# Scaled down LEF created by ScaleLEFMacro.pl
# Original LEF: 16nm/HD_1024X32M8B2.lef
# Don't forget to change metal layer LEF separately!

# Copyright (c) 1993 - 2021 ARM Limited. All Rights Reserved.
# Use of this Software is subject to the terms and conditions of the
# applicable license agreement with ARM Limited.

# PhyVGen V 8.22.0
# ARM Version r3p2
# Creation Date: Thu Sep  9 16:08:25 2021


# Memory Configuration:
# ~~~~~~~~~~~~~~~~~~~~~
#  -activity_factor 50 -atf off -back_biasing off -bits 32 -bmux on
# -bus_notation on -check_instname on -compiler_type sp -diodes on -drive 6
# -ema on -flexible_banking 2 -frequency 1000 -instname HD_1024X32M8B2
# -left_bus_delim "[" -lren_bankmask off -metal_stack 2Xa1Xd -mux 8 -mvt LP
# -name_case upper -pipeline off -power_gating off -power_type otc -prefix ""
# -pwr_gnd_rename vddpe:VDDPE,vddce:VDDCE,vsse:VSSE -rcols 2 -redundancy off
# -retention on -right_bus_delim "]" -rows_p_bl 256 -rrows 0 -scan on -ser none
# -site_def off -top_layer m5-m10 -vmin_assist on -words 1024 -write_mask on
# -write_thru off -corners
# ffgnp_0p88v_0p88v_0c,ffgnp_0p88v_0p88v_125c,ffgnp_0p88v_0p88v_m40c,ssgnp_0p72v_0p72v_0c,ssgnp_0p72v_0p72v_125c,ssgnp_0p72v_0p72v_m40c,tt_0p72v_0p72v_0c,tt_0p80v_0p80v_25c,tt_0p80v_0p80v_85c
# 

VERSION 5.7 ;
BUSBITCHARS "[]" ;
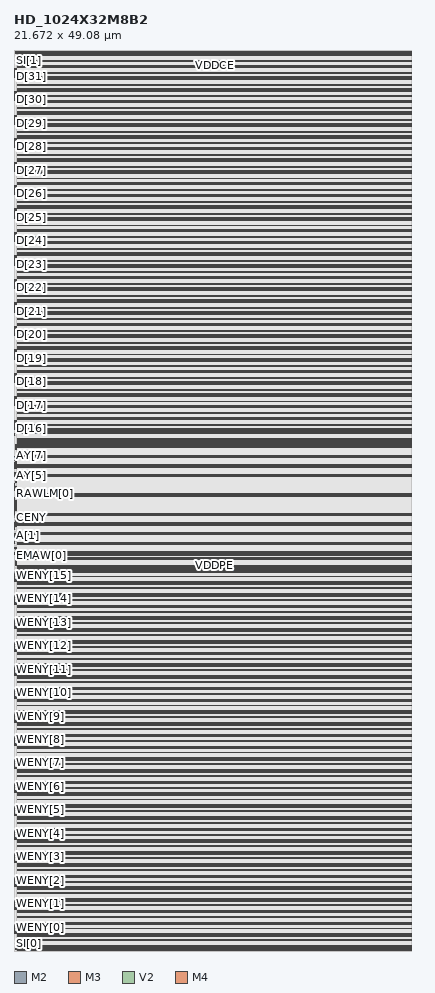
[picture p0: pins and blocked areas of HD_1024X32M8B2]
MACRO HD_1024X32M8B2
	FOREIGN HD_1024X32M8B2 0 0 ;
	SYMMETRY X Y ;
	SIZE 21.672 BY 49.08 ;
	CLASS BLOCK ;
	PIN AY[0]
		USE SIGNAL ;
		DIRECTION OUTPUT ;
		SHAPE ABUTMENT ;
		PORT
			 LAYER M2 ;
			RECT 0.0714 24.0314 0.1097 24.069 ;
			 LAYER M3 ;
			RECT 0.0714 24.0314 0.1097 24.1318 ;
			 LAYER V2 ;
			RECT 0.0831 24.0435 0.098 24.0561 ;
		END

		ANTENNADIFFAREA 0.00194719 ;
		ANTENNAPARTIALMETALAREA 0.00195671 ;
	END AY[0]

	PIN AY[1]
		USE SIGNAL ;
		DIRECTION OUTPUT ;
		SHAPE ABUTMENT ;
		PORT
			 LAYER M2 ;
			RECT 0.0714 24.3325 0.1097 24.3702 ;
			 LAYER M3 ;
			RECT 0.0714 24.3325 0.1097 24.4329 ;
			 LAYER V2 ;
			RECT 0.0831 24.3447 0.098 24.3573 ;
		END

		ANTENNADIFFAREA 0.00194719 ;
		ANTENNAPARTIALMETALAREA 0.00195671 ;
	END AY[1]

	PIN AY[2]
		USE SIGNAL ;
		DIRECTION OUTPUT ;
		SHAPE ABUTMENT ;
		PORT
			 LAYER M2 ;
			RECT 0.0714 24.4831 0.1097 24.5208 ;
			 LAYER M3 ;
			RECT 0.0714 24.4831 0.1097 24.5835 ;
			 LAYER V2 ;
			RECT 0.0831 24.4953 0.098 24.5078 ;
		END

		ANTENNADIFFAREA 0.00194719 ;
		ANTENNAPARTIALMETALAREA 0.00195671 ;
	END AY[2]

	PIN AY[3]
		USE SIGNAL ;
		DIRECTION OUTPUT ;
		SHAPE ABUTMENT ;
		PORT
			 LAYER M2 ;
			RECT 0.0098 25.1482 0.0481 25.1859 ;
			 LAYER M3 ;
			RECT 0.0098 25.0855 0.0481 25.1859 ;
			 LAYER V2 ;
			RECT 0.0215 25.1604 0.0364 25.1729 ;
		END

		ANTENNADIFFAREA 0.00194719 ;
		ANTENNAPARTIALMETALAREA 0.00195671 ;
	END AY[3]

	PIN AY[4]
		USE SIGNAL ;
		DIRECTION OUTPUT ;
		SHAPE ABUTMENT ;
		PORT
			 LAYER M2 ;
			RECT 0.0098 24.2447 0.0481 24.2824 ;
			 LAYER M3 ;
			RECT 0.0098 24.182 0.0481 24.2824 ;
			 LAYER V2 ;
			RECT 0.0215 24.2569 0.0364 24.2694 ;
		END

		ANTENNADIFFAREA 0.00194719 ;
		ANTENNAPARTIALMETALAREA 0.00195671 ;
	END AY[4]

	PIN AY[5]
		USE SIGNAL ;
		DIRECTION OUTPUT ;
		SHAPE ABUTMENT ;
		PORT
			 LAYER M2 ;
			RECT 0.0098 25.9012 0.0481 25.9388 ;
		END

		ANTENNADIFFAREA 0.00194719 ;
		ANTENNAPARTIALMETALAREA 0.00195671 ;
	END AY[5]

	PIN AY[6]
		USE SIGNAL ;
		DIRECTION OUTPUT ;
		SHAPE ABUTMENT ;
		PORT
			 LAYER M2 ;
			RECT 0.0714 25.6878 0.1097 25.7255 ;
			 LAYER M3 ;
			RECT 0.0714 25.6878 0.1097 25.7882 ;
			 LAYER V2 ;
			RECT 0.0831 25.7 0.098 25.7125 ;
		END

		ANTENNADIFFAREA 0.00194719 ;
		ANTENNAPARTIALMETALAREA 0.00195671 ;
	END AY[6]

	PIN AY[7]
		USE SIGNAL ;
		DIRECTION OUTPUT ;
		SHAPE ABUTMENT ;
		PORT
			 LAYER M2 ;
			RECT 0.0098 26.5914 0.0481 26.629 ;
		END

		ANTENNADIFFAREA 0.00194719 ;
		ANTENNAPARTIALMETALAREA 0.00195671 ;
	END AY[7]

	PIN AY[8]
		USE SIGNAL ;
		DIRECTION OUTPUT ;
		SHAPE ABUTMENT ;
		PORT
			 LAYER M2 ;
			RECT 0.0714 26.8925 0.1097 26.9302 ;
			 LAYER M3 ;
			RECT 0.0714 26.8925 0.1097 26.9929 ;
			 LAYER V2 ;
			RECT 0.0831 26.9047 0.098 26.9173 ;
		END

		ANTENNADIFFAREA 0.00194719 ;
		ANTENNAPARTIALMETALAREA 0.00195671 ;
	END AY[8]

	PIN AY[9]
		USE SIGNAL ;
		DIRECTION OUTPUT ;
		SHAPE ABUTMENT ;
		PORT
			 LAYER M3 ;
			RECT 0.0714 26.5914 0.1097 26.6918 ;
		END

		ANTENNADIFFAREA 0.00194719 ;
		ANTENNAPARTIALMETALAREA 0.00195671 ;
	END AY[9]

	PIN A[0]
		USE SIGNAL ;
		DIRECTION INPUT ;
		SHAPE ABUTMENT ;
		PORT
			 LAYER M2 ;
			RECT 0.0098 23.7929 0.0481 23.8306 ;
			 LAYER M3 ;
			RECT 0.0098 23.7302 0.0481 23.8306 ;
			 LAYER V2 ;
			RECT 0.0215 23.8051 0.0364 23.8176 ;
		END

		ANTENNAGATEAREA 0.00027817 ;
		ANTENNADIFFAREA 0.00194719 ;
		ANTENNAPARTIALMETALAREA 0.00195671 ;
	END A[0]

	PIN A[1]
		USE SIGNAL ;
		DIRECTION INPUT ;
		SHAPE ABUTMENT ;
		PORT
			 LAYER M2 ;
			RECT 0.0098 23.04 0.0481 23.0776 ;
			 LAYER M3 ;
			RECT 0.0098 22.9773 0.0481 23.0776 ;
			 LAYER V2 ;
			RECT 0.0215 23.0522 0.0364 23.0647 ;
		END

		ANTENNAGATEAREA 0.00027817 ;
		ANTENNADIFFAREA 0.00194719 ;
		ANTENNAPARTIALMETALAREA 0.00195671 ;
	END A[1]

	PIN A[2]
		USE SIGNAL ;
		DIRECTION INPUT ;
		SHAPE ABUTMENT ;
		PORT
			 LAYER M2 ;
			RECT 0.0714 26.4408 0.1097 26.4784 ;
			 LAYER M3 ;
			RECT 0.0714 26.4408 0.1097 26.5412 ;
			 LAYER V2 ;
			RECT 0.0831 26.4529 0.098 26.4655 ;
		END

		ANTENNAGATEAREA 0.00027817 ;
		ANTENNADIFFAREA 0.00194719 ;
		ANTENNAPARTIALMETALAREA 0.00195671 ;
	END A[2]

	PIN A[3]
		USE SIGNAL ;
		DIRECTION INPUT ;
		SHAPE ABUTMENT ;
		PORT
			 LAYER M2 ;
			RECT 0.0098 25.2988 0.0481 25.3365 ;
			 LAYER M3 ;
			RECT 0.0098 25.2361 0.0481 25.3365 ;
			 LAYER V2 ;
			RECT 0.0215 25.311 0.0364 25.3235 ;
		END

		ANTENNAGATEAREA 0.00027817 ;
		ANTENNADIFFAREA 0.00194719 ;
		ANTENNAPARTIALMETALAREA 0.00195671 ;
	END A[3]

	PIN A[4]
		USE SIGNAL ;
		DIRECTION INPUT ;
		SHAPE ABUTMENT ;
		PORT
			 LAYER M2 ;
			RECT 0.0098 24.6965 0.0481 24.7341 ;
			 LAYER M3 ;
			RECT 0.0098 24.6337 0.0481 24.7341 ;
			 LAYER V2 ;
			RECT 0.0215 24.7086 0.0364 24.7212 ;
		END

		ANTENNAGATEAREA 0.00027817 ;
		ANTENNADIFFAREA 0.00194719 ;
		ANTENNAPARTIALMETALAREA 0.00195671 ;
	END A[4]

	PIN A[5]
		USE SIGNAL ;
		DIRECTION INPUT ;
		SHAPE ABUTMENT ;
		PORT
			 LAYER M2 ;
			RECT 0.0098 25.4494 0.0481 25.4871 ;
			 LAYER M3 ;
			RECT 0.0098 25.3867 0.0481 25.4871 ;
			 LAYER V2 ;
			RECT 0.0215 25.4616 0.0364 25.4741 ;
		END

		ANTENNAGATEAREA 0.00027817 ;
		ANTENNADIFFAREA 0.00194719 ;
		ANTENNAPARTIALMETALAREA 0.00195671 ;
	END A[5]

	PIN A[6]
		USE SIGNAL ;
		DIRECTION INPUT ;
		SHAPE ABUTMENT ;
		PORT
			 LAYER M2 ;
			RECT 0.0098 26.0518 0.0481 26.0894 ;
		END

		ANTENNAGATEAREA 0.00027817 ;
		ANTENNADIFFAREA 0.00194719 ;
		ANTENNAPARTIALMETALAREA 0.00195671 ;
	END A[6]

	PIN A[7]
		USE SIGNAL ;
		DIRECTION INPUT ;
		SHAPE ABUTMENT ;
		PORT
			 LAYER M2 ;
			RECT 0.0098 26.3529 0.0481 26.3906 ;
			 LAYER M3 ;
			RECT 0.0098 26.2902 0.0481 26.3906 ;
			 LAYER V2 ;
			RECT 0.0215 26.3651 0.0364 26.3776 ;
		END

		ANTENNAGATEAREA 0.00027817 ;
		ANTENNADIFFAREA 0.00194719 ;
		ANTENNAPARTIALMETALAREA 0.00195671 ;
	END A[7]

	PIN A[8]
		USE SIGNAL ;
		DIRECTION INPUT ;
		SHAPE ABUTMENT ;
		PORT
			 LAYER M2 ;
			RECT 0.0098 26.5035 0.0481 26.5412 ;
			 LAYER M3 ;
			RECT 0.0098 26.4408 0.0481 26.5412 ;
			 LAYER V2 ;
			RECT 0.0215 26.5157 0.0364 26.5282 ;
		END

		ANTENNAGATEAREA 0.00027817 ;
		ANTENNADIFFAREA 0.00194719 ;
		ANTENNAPARTIALMETALAREA 0.00195671 ;
	END A[8]

	PIN A[9]
		USE SIGNAL ;
		DIRECTION INPUT ;
		SHAPE ABUTMENT ;
		PORT
			 LAYER M2 ;
			RECT 0.0098 26.9553 0.0481 26.9929 ;
			 LAYER M3 ;
			RECT 0.0098 26.8925 0.0481 26.9929 ;
			 LAYER V2 ;
			RECT 0.0215 26.9675 0.0364 26.98 ;
		END

		ANTENNAGATEAREA 0.00027817 ;
		ANTENNADIFFAREA 0.00194719 ;
		ANTENNAPARTIALMETALAREA 0.00195671 ;
	END A[9]

	PIN CEN
		USE SIGNAL ;
		DIRECTION INPUT ;
		SHAPE ABUTMENT ;
		PORT
			 LAYER M2 ;
			RECT 0.0714 27.4949 0.1097 27.5325 ;
			 LAYER M3 ;
			RECT 0.0714 27.4949 0.1097 27.5953 ;
			 LAYER V2 ;
			RECT 0.0831 27.5071 0.098 27.5196 ;
		END

		ANTENNAGATEAREA 0.00027817 ;
		ANTENNADIFFAREA 0.00194719 ;
		ANTENNAPARTIALMETALAREA 0.00195671 ;
	END CEN

	PIN CENY
		USE SIGNAL ;
		DIRECTION OUTPUT ;
		SHAPE ABUTMENT ;
		PORT
			 LAYER M2 ;
			RECT 0.0098 23.6424 0.0481 23.68 ;
		END

		ANTENNADIFFAREA 0.00194719 ;
		ANTENNAPARTIALMETALAREA 0.00195671 ;
	END CENY

	PIN CLK
		USE SIGNAL ;
		DIRECTION INPUT ;
		SHAPE ABUTMENT ;
		PORT
			 LAYER M2 ;
			RECT 0.0098 24.0941 0.0481 24.1318 ;
			 LAYER M3 ;
			RECT 0.0098 24.0314 0.0481 24.1318 ;
			 LAYER V2 ;
			RECT 0.0215 24.1063 0.0364 24.1188 ;
		END

		ANTENNAGATEAREA 0.00027817 ;
		ANTENNADIFFAREA 0.00194719 ;
		ANTENNAPARTIALMETALAREA 0.00195671 ;
	END CLK

	PIN DFTRAMBYP
		USE SIGNAL ;
		DIRECTION INPUT ;
		SHAPE ABUTMENT ;
		PORT
			 LAYER M2 ;
			RECT 0.0714 22.5255 0.1097 22.5631 ;
			 LAYER M3 ;
			RECT 0.0714 22.5255 0.1097 22.6259 ;
			 LAYER V2 ;
			RECT 0.0831 22.5376 0.098 22.5502 ;
		END

		ANTENNAGATEAREA 0.00027817 ;
		ANTENNADIFFAREA 0.00194719 ;
		ANTENNAPARTIALMETALAREA 0.00195671 ;
	END DFTRAMBYP

	PIN D[0]
		USE SIGNAL ;
		DIRECTION INPUT ;
		SHAPE ABUTMENT ;
		PORT
			 LAYER M2 ;
			RECT 0.0098 1.3678 0.0481 1.4055 ;
			 LAYER M3 ;
			RECT 0.0098 1.3678 0.0481 1.4682 ;
			 LAYER V2 ;
			RECT 0.0215 1.3808 0.0364 1.3933 ;
		END

		ANTENNAGATEAREA 0.00027817 ;
		ANTENNADIFFAREA 0.00194719 ;
		ANTENNAPARTIALMETALAREA 0.00195671 ;
	END D[0]

	PIN D[10]
		USE SIGNAL ;
		DIRECTION INPUT ;
		SHAPE ABUTMENT ;
		PORT
			 LAYER M2 ;
			RECT 0.0098 14.1678 0.0481 14.2055 ;
			 LAYER M3 ;
			RECT 0.0098 14.1678 0.0481 14.2682 ;
			 LAYER V2 ;
			RECT 0.0215 14.1808 0.0364 14.1933 ;
		END

		ANTENNAGATEAREA 0.00027817 ;
		ANTENNADIFFAREA 0.00194719 ;
		ANTENNAPARTIALMETALAREA 0.00195671 ;
	END D[10]

	PIN D[11]
		USE SIGNAL ;
		DIRECTION INPUT ;
		SHAPE ABUTMENT ;
		PORT
			 LAYER M2 ;
			RECT 0.0098 15.4478 0.0481 15.4855 ;
			 LAYER M3 ;
			RECT 0.0098 15.4478 0.0481 15.5482 ;
			 LAYER V2 ;
			RECT 0.0215 15.4608 0.0364 15.4733 ;
		END

		ANTENNAGATEAREA 0.00027817 ;
		ANTENNADIFFAREA 0.00194719 ;
		ANTENNAPARTIALMETALAREA 0.00195671 ;
	END D[11]

	PIN D[12]
		USE SIGNAL ;
		DIRECTION INPUT ;
		SHAPE ABUTMENT ;
		PORT
			 LAYER M2 ;
			RECT 0.0098 16.7278 0.0481 16.7655 ;
			 LAYER M3 ;
			RECT 0.0098 16.7278 0.0481 16.8282 ;
			 LAYER V2 ;
			RECT 0.0215 16.7408 0.0364 16.7533 ;
		END

		ANTENNAGATEAREA 0.00027817 ;
		ANTENNADIFFAREA 0.00194719 ;
		ANTENNAPARTIALMETALAREA 0.00195671 ;
	END D[12]

	PIN D[13]
		USE SIGNAL ;
		DIRECTION INPUT ;
		SHAPE ABUTMENT ;
		PORT
			 LAYER M2 ;
			RECT 0.0098 18.0078 0.0481 18.0455 ;
			 LAYER M3 ;
			RECT 0.0098 18.0078 0.0481 18.1082 ;
			 LAYER V2 ;
			RECT 0.0215 18.0208 0.0364 18.0333 ;
		END

		ANTENNAGATEAREA 0.00027817 ;
		ANTENNADIFFAREA 0.00194719 ;
		ANTENNAPARTIALMETALAREA 0.00195671 ;
	END D[13]

	PIN D[14]
		USE SIGNAL ;
		DIRECTION INPUT ;
		SHAPE ABUTMENT ;
		PORT
			 LAYER M2 ;
			RECT 0.0098 19.2878 0.0481 19.3255 ;
			 LAYER M3 ;
			RECT 0.0098 19.2878 0.0481 19.3882 ;
			 LAYER V2 ;
			RECT 0.0215 19.3008 0.0364 19.3133 ;
		END

		ANTENNAGATEAREA 0.00027817 ;
		ANTENNADIFFAREA 0.00194719 ;
		ANTENNAPARTIALMETALAREA 0.00195671 ;
	END D[14]

	PIN D[15]
		USE SIGNAL ;
		DIRECTION INPUT ;
		SHAPE ABUTMENT ;
		PORT
			 LAYER M2 ;
			RECT 0.0098 20.5678 0.0481 20.6055 ;
			 LAYER M3 ;
			RECT 0.0098 20.5678 0.0481 20.6682 ;
			 LAYER V2 ;
			RECT 0.0215 20.5808 0.0364 20.5933 ;
		END

		ANTENNAGATEAREA 0.00027817 ;
		ANTENNADIFFAREA 0.00194719 ;
		ANTENNAPARTIALMETALAREA 0.00195671 ;
	END D[15]

	PIN D[16]
		USE SIGNAL ;
		DIRECTION INPUT ;
		SHAPE ABUTMENT ;
		PORT
			 LAYER M2 ;
			RECT 0.0098 28.5051 0.0481 28.5427 ;
			 LAYER M3 ;
			RECT 0.0098 28.4424 0.0481 28.5427 ;
			 LAYER V2 ;
			RECT 0.0215 28.5173 0.0364 28.5298 ;
		END

		ANTENNAGATEAREA 0.00027817 ;
		ANTENNADIFFAREA 0.00194719 ;
		ANTENNAPARTIALMETALAREA 0.00195671 ;
	END D[16]

	PIN D[17]
		USE SIGNAL ;
		DIRECTION INPUT ;
		SHAPE ABUTMENT ;
		PORT
			 LAYER M2 ;
			RECT 0.0098 29.7851 0.0481 29.8227 ;
			 LAYER M3 ;
			RECT 0.0098 29.7224 0.0481 29.8227 ;
			 LAYER V2 ;
			RECT 0.0215 29.7973 0.0364 29.8098 ;
		END

		ANTENNAGATEAREA 0.00027817 ;
		ANTENNADIFFAREA 0.00194719 ;
		ANTENNAPARTIALMETALAREA 0.00195671 ;
	END D[17]

	PIN D[18]
		USE SIGNAL ;
		DIRECTION INPUT ;
		SHAPE ABUTMENT ;
		PORT
			 LAYER M2 ;
			RECT 0.0098 31.0651 0.0481 31.1027 ;
			 LAYER M3 ;
			RECT 0.0098 31.0024 0.0481 31.1027 ;
			 LAYER V2 ;
			RECT 0.0215 31.0773 0.0364 31.0898 ;
		END

		ANTENNAGATEAREA 0.00027817 ;
		ANTENNADIFFAREA 0.00194719 ;
		ANTENNAPARTIALMETALAREA 0.00195671 ;
	END D[18]

	PIN D[19]
		USE SIGNAL ;
		DIRECTION INPUT ;
		SHAPE ABUTMENT ;
		PORT
			 LAYER M2 ;
			RECT 0.0098 32.3451 0.0481 32.3827 ;
			 LAYER M3 ;
			RECT 0.0098 32.2824 0.0481 32.3827 ;
			 LAYER V2 ;
			RECT 0.0215 32.3573 0.0364 32.3698 ;
		END

		ANTENNAGATEAREA 0.00027817 ;
		ANTENNADIFFAREA 0.00194719 ;
		ANTENNAPARTIALMETALAREA 0.00195671 ;
	END D[19]

	PIN D[1]
		USE SIGNAL ;
		DIRECTION INPUT ;
		SHAPE ABUTMENT ;
		PORT
			 LAYER M2 ;
			RECT 0.0098 2.6478 0.0481 2.6855 ;
			 LAYER M3 ;
			RECT 0.0098 2.6478 0.0481 2.7482 ;
			 LAYER V2 ;
			RECT 0.0215 2.6608 0.0364 2.6733 ;
		END

		ANTENNAGATEAREA 0.00027817 ;
		ANTENNADIFFAREA 0.00194719 ;
		ANTENNAPARTIALMETALAREA 0.00195671 ;
	END D[1]

	PIN D[20]
		USE SIGNAL ;
		DIRECTION INPUT ;
		SHAPE ABUTMENT ;
		PORT
			 LAYER M2 ;
			RECT 0.0098 33.6251 0.0481 33.6627 ;
			 LAYER M3 ;
			RECT 0.0098 33.5624 0.0481 33.6627 ;
			 LAYER V2 ;
			RECT 0.0215 33.6373 0.0364 33.6498 ;
		END

		ANTENNAGATEAREA 0.00027817 ;
		ANTENNADIFFAREA 0.00194719 ;
		ANTENNAPARTIALMETALAREA 0.00195671 ;
	END D[20]

	PIN D[21]
		USE SIGNAL ;
		DIRECTION INPUT ;
		SHAPE ABUTMENT ;
		PORT
			 LAYER M2 ;
			RECT 0.0098 34.9051 0.0481 34.9427 ;
			 LAYER M3 ;
			RECT 0.0098 34.8424 0.0481 34.9427 ;
			 LAYER V2 ;
			RECT 0.0215 34.9173 0.0364 34.9298 ;
		END

		ANTENNAGATEAREA 0.00027817 ;
		ANTENNADIFFAREA 0.00194719 ;
		ANTENNAPARTIALMETALAREA 0.00195671 ;
	END D[21]

	PIN D[22]
		USE SIGNAL ;
		DIRECTION INPUT ;
		SHAPE ABUTMENT ;
		PORT
			 LAYER M2 ;
			RECT 0.0098 36.1851 0.0481 36.2227 ;
			 LAYER M3 ;
			RECT 0.0098 36.1224 0.0481 36.2227 ;
			 LAYER V2 ;
			RECT 0.0215 36.1973 0.0364 36.2098 ;
		END

		ANTENNAGATEAREA 0.00027817 ;
		ANTENNADIFFAREA 0.00194719 ;
		ANTENNAPARTIALMETALAREA 0.00195671 ;
	END D[22]

	PIN D[23]
		USE SIGNAL ;
		DIRECTION INPUT ;
		SHAPE ABUTMENT ;
		PORT
			 LAYER M2 ;
			RECT 0.0098 37.4651 0.0481 37.5027 ;
			 LAYER M3 ;
			RECT 0.0098 37.4024 0.0481 37.5027 ;
			 LAYER V2 ;
			RECT 0.0215 37.4773 0.0364 37.4898 ;
		END

		ANTENNAGATEAREA 0.00027817 ;
		ANTENNADIFFAREA 0.00194719 ;
		ANTENNAPARTIALMETALAREA 0.00195671 ;
	END D[23]

	PIN D[24]
		USE SIGNAL ;
		DIRECTION INPUT ;
		SHAPE ABUTMENT ;
		PORT
			 LAYER M2 ;
			RECT 0.0098 38.7451 0.0481 38.7827 ;
			 LAYER M3 ;
			RECT 0.0098 38.6824 0.0481 38.7827 ;
			 LAYER V2 ;
			RECT 0.0215 38.7573 0.0364 38.7698 ;
		END

		ANTENNAGATEAREA 0.00027817 ;
		ANTENNADIFFAREA 0.00194719 ;
		ANTENNAPARTIALMETALAREA 0.00195671 ;
	END D[24]

	PIN D[25]
		USE SIGNAL ;
		DIRECTION INPUT ;
		SHAPE ABUTMENT ;
		PORT
			 LAYER M2 ;
			RECT 0.0098 40.0251 0.0481 40.0627 ;
			 LAYER M3 ;
			RECT 0.0098 39.9624 0.0481 40.0627 ;
			 LAYER V2 ;
			RECT 0.0215 40.0373 0.0364 40.0498 ;
		END

		ANTENNAGATEAREA 0.00027817 ;
		ANTENNADIFFAREA 0.00194719 ;
		ANTENNAPARTIALMETALAREA 0.00195671 ;
	END D[25]

	PIN D[26]
		USE SIGNAL ;
		DIRECTION INPUT ;
		SHAPE ABUTMENT ;
		PORT
			 LAYER M2 ;
			RECT 0.0098 41.3051 0.0481 41.3427 ;
			 LAYER M3 ;
			RECT 0.0098 41.2424 0.0481 41.3427 ;
			 LAYER V2 ;
			RECT 0.0215 41.3173 0.0364 41.3298 ;
		END

		ANTENNAGATEAREA 0.00027817 ;
		ANTENNADIFFAREA 0.00194719 ;
		ANTENNAPARTIALMETALAREA 0.00195671 ;
	END D[26]

	PIN D[27]
		USE SIGNAL ;
		DIRECTION INPUT ;
		SHAPE ABUTMENT ;
		PORT
			 LAYER M2 ;
			RECT 0.0098 42.5851 0.0481 42.6227 ;
			 LAYER M3 ;
			RECT 0.0098 42.5224 0.0481 42.6227 ;
			 LAYER V2 ;
			RECT 0.0215 42.5973 0.0364 42.6098 ;
		END

		ANTENNAGATEAREA 0.00027817 ;
		ANTENNADIFFAREA 0.00194719 ;
		ANTENNAPARTIALMETALAREA 0.00195671 ;
	END D[27]

	PIN D[28]
		USE SIGNAL ;
		DIRECTION INPUT ;
		SHAPE ABUTMENT ;
		PORT
			 LAYER M2 ;
			RECT 0.0098 43.8651 0.0481 43.9027 ;
			 LAYER M3 ;
			RECT 0.0098 43.8024 0.0481 43.9027 ;
			 LAYER V2 ;
			RECT 0.0215 43.8773 0.0364 43.8898 ;
		END

		ANTENNAGATEAREA 0.00027817 ;
		ANTENNADIFFAREA 0.00194719 ;
		ANTENNAPARTIALMETALAREA 0.00195671 ;
	END D[28]

	PIN D[29]
		USE SIGNAL ;
		DIRECTION INPUT ;
		SHAPE ABUTMENT ;
		PORT
			 LAYER M2 ;
			RECT 0.0098 45.1451 0.0481 45.1827 ;
			 LAYER M3 ;
			RECT 0.0098 45.0824 0.0481 45.1827 ;
			 LAYER V2 ;
			RECT 0.0215 45.1573 0.0364 45.1698 ;
		END

		ANTENNAGATEAREA 0.00027817 ;
		ANTENNADIFFAREA 0.00194719 ;
		ANTENNAPARTIALMETALAREA 0.00195671 ;
	END D[29]

	PIN D[2]
		USE SIGNAL ;
		DIRECTION INPUT ;
		SHAPE ABUTMENT ;
		PORT
			 LAYER M2 ;
			RECT 0.0098 3.9278 0.0481 3.9655 ;
			 LAYER M3 ;
			RECT 0.0098 3.9278 0.0481 4.0282 ;
			 LAYER V2 ;
			RECT 0.0215 3.9408 0.0364 3.9533 ;
		END

		ANTENNAGATEAREA 0.00027817 ;
		ANTENNADIFFAREA 0.00194719 ;
		ANTENNAPARTIALMETALAREA 0.00195671 ;
	END D[2]

	PIN D[30]
		USE SIGNAL ;
		DIRECTION INPUT ;
		SHAPE ABUTMENT ;
		PORT
			 LAYER M2 ;
			RECT 0.0098 46.4251 0.0481 46.4627 ;
			 LAYER M3 ;
			RECT 0.0098 46.3624 0.0481 46.4627 ;
			 LAYER V2 ;
			RECT 0.0215 46.4373 0.0364 46.4498 ;
		END

		ANTENNAGATEAREA 0.00027817 ;
		ANTENNADIFFAREA 0.00194719 ;
		ANTENNAPARTIALMETALAREA 0.00195671 ;
	END D[30]

	PIN D[31]
		USE SIGNAL ;
		DIRECTION INPUT ;
		SHAPE ABUTMENT ;
		PORT
			 LAYER M2 ;
			RECT 0.0098 47.7051 0.0481 47.7427 ;
			 LAYER M3 ;
			RECT 0.0098 47.6424 0.0481 47.7427 ;
			 LAYER V2 ;
			RECT 0.0215 47.7173 0.0364 47.7298 ;
		END

		ANTENNAGATEAREA 0.00027817 ;
		ANTENNADIFFAREA 0.00194719 ;
		ANTENNAPARTIALMETALAREA 0.00195671 ;
	END D[31]

	PIN D[3]
		USE SIGNAL ;
		DIRECTION INPUT ;
		SHAPE ABUTMENT ;
		PORT
			 LAYER M2 ;
			RECT 0.0098 5.2078 0.0481 5.2455 ;
			 LAYER M3 ;
			RECT 0.0098 5.2078 0.0481 5.3082 ;
			 LAYER V2 ;
			RECT 0.0215 5.2208 0.0364 5.2333 ;
		END

		ANTENNAGATEAREA 0.00027817 ;
		ANTENNADIFFAREA 0.00194719 ;
		ANTENNAPARTIALMETALAREA 0.00195671 ;
	END D[3]

	PIN D[4]
		USE SIGNAL ;
		DIRECTION INPUT ;
		SHAPE ABUTMENT ;
		PORT
			 LAYER M2 ;
			RECT 0.0098 6.4878 0.0481 6.5255 ;
			 LAYER M3 ;
			RECT 0.0098 6.4878 0.0481 6.5882 ;
			 LAYER V2 ;
			RECT 0.0215 6.5008 0.0364 6.5133 ;
		END

		ANTENNAGATEAREA 0.00027817 ;
		ANTENNADIFFAREA 0.00194719 ;
		ANTENNAPARTIALMETALAREA 0.00195671 ;
	END D[4]

	PIN D[5]
		USE SIGNAL ;
		DIRECTION INPUT ;
		SHAPE ABUTMENT ;
		PORT
			 LAYER M2 ;
			RECT 0.0098 7.7678 0.0481 7.8055 ;
			 LAYER M3 ;
			RECT 0.0098 7.7678 0.0481 7.8682 ;
			 LAYER V2 ;
			RECT 0.0215 7.7808 0.0364 7.7933 ;
		END

		ANTENNAGATEAREA 0.00027817 ;
		ANTENNADIFFAREA 0.00194719 ;
		ANTENNAPARTIALMETALAREA 0.00195671 ;
	END D[5]

	PIN D[6]
		USE SIGNAL ;
		DIRECTION INPUT ;
		SHAPE ABUTMENT ;
		PORT
			 LAYER M2 ;
			RECT 0.0098 9.0478 0.0481 9.0855 ;
			 LAYER M3 ;
			RECT 0.0098 9.0478 0.0481 9.1482 ;
			 LAYER V2 ;
			RECT 0.0215 9.0608 0.0364 9.0733 ;
		END

		ANTENNAGATEAREA 0.00027817 ;
		ANTENNADIFFAREA 0.00194719 ;
		ANTENNAPARTIALMETALAREA 0.00195671 ;
	END D[6]

	PIN D[7]
		USE SIGNAL ;
		DIRECTION INPUT ;
		SHAPE ABUTMENT ;
		PORT
			 LAYER M2 ;
			RECT 0.0098 10.3278 0.0481 10.3655 ;
			 LAYER M3 ;
			RECT 0.0098 10.3278 0.0481 10.4282 ;
			 LAYER V2 ;
			RECT 0.0215 10.3408 0.0364 10.3533 ;
		END

		ANTENNAGATEAREA 0.00027817 ;
		ANTENNADIFFAREA 0.00194719 ;
		ANTENNAPARTIALMETALAREA 0.00195671 ;
	END D[7]

	PIN D[8]
		USE SIGNAL ;
		DIRECTION INPUT ;
		SHAPE ABUTMENT ;
		PORT
			 LAYER M2 ;
			RECT 0.0098 11.6078 0.0481 11.6455 ;
			 LAYER M3 ;
			RECT 0.0098 11.6078 0.0481 11.7082 ;
			 LAYER V2 ;
			RECT 0.0215 11.6208 0.0364 11.6333 ;
		END

		ANTENNAGATEAREA 0.00027817 ;
		ANTENNADIFFAREA 0.00194719 ;
		ANTENNAPARTIALMETALAREA 0.00195671 ;
	END D[8]

	PIN D[9]
		USE SIGNAL ;
		DIRECTION INPUT ;
		SHAPE ABUTMENT ;
		PORT
			 LAYER M2 ;
			RECT 0.0098 12.8878 0.0481 12.9255 ;
			 LAYER M3 ;
			RECT 0.0098 12.8878 0.0481 12.9882 ;
			 LAYER V2 ;
			RECT 0.0215 12.9008 0.0364 12.9133 ;
		END

		ANTENNAGATEAREA 0.00027817 ;
		ANTENNADIFFAREA 0.00194719 ;
		ANTENNAPARTIALMETALAREA 0.00195671 ;
	END D[9]

	PIN EMAS
		USE SIGNAL ;
		DIRECTION INPUT ;
		SHAPE ABUTMENT ;
		PORT
			 LAYER M2 ;
			RECT 0.0714 23.1278 0.1097 23.1655 ;
			 LAYER M3 ;
			RECT 0.0714 23.1278 0.1097 23.2282 ;
			 LAYER V2 ;
			RECT 0.0831 23.14 0.098 23.1525 ;
		END

		ANTENNAGATEAREA 0.00027817 ;
		ANTENNADIFFAREA 0.00194719 ;
		ANTENNAPARTIALMETALAREA 0.00195671 ;
	END EMAS

	PIN EMAW[0]
		USE SIGNAL ;
		DIRECTION INPUT ;
		SHAPE ABUTMENT ;
		PORT
			 LAYER M2 ;
			RECT 0.0714 21.9231 0.1097 21.9608 ;
			 LAYER M3 ;
			RECT 0.0714 21.9231 0.1097 22.0235 ;
			 LAYER V2 ;
			RECT 0.0831 21.9353 0.098 21.9478 ;
		END

		ANTENNAGATEAREA 0.00027817 ;
		ANTENNADIFFAREA 0.00194719 ;
		ANTENNAPARTIALMETALAREA 0.00195671 ;
	END EMAW[0]

	PIN EMAW[1]
		USE SIGNAL ;
		DIRECTION INPUT ;
		SHAPE ABUTMENT ;
		PORT
			 LAYER M2 ;
			RECT 0.0098 21.9859 0.0481 22.0235 ;
			 LAYER M3 ;
			RECT 0.0098 21.9231 0.0481 22.0235 ;
			 LAYER V2 ;
			RECT 0.0215 21.998 0.0364 22.0106 ;
		END

		ANTENNAGATEAREA 0.00027817 ;
		ANTENNADIFFAREA 0.00194719 ;
		ANTENNAPARTIALMETALAREA 0.00195671 ;
	END EMAW[1]

	PIN EMA[0]
		USE SIGNAL ;
		DIRECTION INPUT ;
		SHAPE ABUTMENT ;
		PORT
			 LAYER M2 ;
			RECT 0.0098 21.6847 0.0481 21.7224 ;
			 LAYER M3 ;
			RECT 0.0098 21.622 0.0481 21.7224 ;
			 LAYER V2 ;
			RECT 0.0215 21.6969 0.0364 21.7094 ;
		END

		ANTENNAGATEAREA 0.00027817 ;
		ANTENNADIFFAREA 0.00194719 ;
		ANTENNAPARTIALMETALAREA 0.00195671 ;
	END EMA[0]

	PIN EMA[1]
		USE SIGNAL ;
		DIRECTION INPUT ;
		SHAPE ABUTMENT ;
		PORT
			 LAYER M2 ;
			RECT 0.0714 21.7725 0.1097 21.8102 ;
			 LAYER M3 ;
			RECT 0.0714 21.7725 0.1097 21.8729 ;
			 LAYER V2 ;
			RECT 0.0831 21.7847 0.098 21.7973 ;
		END

		ANTENNAGATEAREA 0.00027817 ;
		ANTENNADIFFAREA 0.00194719 ;
		ANTENNAPARTIALMETALAREA 0.00195671 ;
	END EMA[1]

	PIN EMA[2]
		USE SIGNAL ;
		DIRECTION INPUT ;
		SHAPE ABUTMENT ;
		PORT
			 LAYER M2 ;
			RECT 0.0714 22.6761 0.1097 22.7137 ;
			 LAYER M3 ;
			RECT 0.0714 22.6761 0.1097 22.7765 ;
			 LAYER V2 ;
			RECT 0.0831 22.6882 0.098 22.7008 ;
		END

		ANTENNAGATEAREA 0.00027817 ;
		ANTENNADIFFAREA 0.00194719 ;
		ANTENNAPARTIALMETALAREA 0.00195671 ;
	END EMA[2]

	PIN GWEN
		USE SIGNAL ;
		DIRECTION INPUT ;
		SHAPE ABUTMENT ;
		PORT
			 LAYER M2 ;
			RECT 0.0098 22.5882 0.0481 22.6259 ;
			 LAYER M3 ;
			RECT 0.0098 22.5255 0.0481 22.6259 ;
			 LAYER V2 ;
			RECT 0.0215 22.6004 0.0364 22.6129 ;
		END

		ANTENNAGATEAREA 0.00027817 ;
		ANTENNADIFFAREA 0.00194719 ;
		ANTENNAPARTIALMETALAREA 0.00195671 ;
	END GWEN

	PIN GWENY
		USE SIGNAL ;
		DIRECTION OUTPUT ;
		SHAPE ABUTMENT ;
		PORT
			 LAYER M2 ;
			RECT 0.0714 23.2784 0.1097 23.3161 ;
			 LAYER M3 ;
			RECT 0.0714 23.2784 0.1097 23.3788 ;
			 LAYER V2 ;
			RECT 0.0831 23.2906 0.098 23.3031 ;
		END

		ANTENNADIFFAREA 0.00194719 ;
		ANTENNAPARTIALMETALAREA 0.00195671 ;
	END GWENY

	PIN Q[0]
		USE SIGNAL ;
		DIRECTION OUTPUT ;
		SHAPE ABUTMENT ;
		PORT
			 LAYER M2 ;
			RECT 0.0098 1.0918 0.0481 1.1922 ;
			 LAYER M3 ;
			RECT 0.0098 1.0918 0.0481 1.1922 ;
			 LAYER V2 ;
			RECT 0.021 1.1667 0.0359 1.1792 ;
		END

		ANTENNADIFFAREA 0.00194719 ;
		ANTENNAPARTIALMETALAREA 0.00195671 ;
	END Q[0]

	PIN Q[10]
		USE SIGNAL ;
		DIRECTION OUTPUT ;
		SHAPE ABUTMENT ;
		PORT
			 LAYER M2 ;
			RECT 0.0098 13.8918 0.0481 13.9922 ;
			 LAYER M3 ;
			RECT 0.0098 13.8918 0.0481 13.9922 ;
			 LAYER V2 ;
			RECT 0.021 13.9667 0.0359 13.9792 ;
		END

		ANTENNADIFFAREA 0.00194719 ;
		ANTENNAPARTIALMETALAREA 0.00195671 ;
	END Q[10]

	PIN Q[11]
		USE SIGNAL ;
		DIRECTION OUTPUT ;
		SHAPE ABUTMENT ;
		PORT
			 LAYER M2 ;
			RECT 0.0098 15.1718 0.0481 15.2722 ;
			 LAYER M3 ;
			RECT 0.0098 15.1718 0.0481 15.2722 ;
			 LAYER V2 ;
			RECT 0.021 15.2467 0.0359 15.2592 ;
		END

		ANTENNADIFFAREA 0.00194719 ;
		ANTENNAPARTIALMETALAREA 0.00195671 ;
	END Q[11]

	PIN Q[12]
		USE SIGNAL ;
		DIRECTION OUTPUT ;
		SHAPE ABUTMENT ;
		PORT
			 LAYER M2 ;
			RECT 0.0098 16.4518 0.0481 16.5522 ;
			 LAYER M3 ;
			RECT 0.0098 16.4518 0.0481 16.5522 ;
			 LAYER V2 ;
			RECT 0.021 16.5267 0.0359 16.5392 ;
		END

		ANTENNADIFFAREA 0.00194719 ;
		ANTENNAPARTIALMETALAREA 0.00195671 ;
	END Q[12]

	PIN Q[13]
		USE SIGNAL ;
		DIRECTION OUTPUT ;
		SHAPE ABUTMENT ;
		PORT
			 LAYER M2 ;
			RECT 0.0098 17.7318 0.0481 17.8322 ;
			 LAYER M3 ;
			RECT 0.0098 17.7318 0.0481 17.8322 ;
			 LAYER V2 ;
			RECT 0.021 17.8067 0.0359 17.8192 ;
		END

		ANTENNADIFFAREA 0.00194719 ;
		ANTENNAPARTIALMETALAREA 0.00195671 ;
	END Q[13]

	PIN Q[14]
		USE SIGNAL ;
		DIRECTION OUTPUT ;
		SHAPE ABUTMENT ;
		PORT
			 LAYER M2 ;
			RECT 0.0098 19.0118 0.0481 19.1122 ;
			 LAYER M3 ;
			RECT 0.0098 19.0118 0.0481 19.1122 ;
			 LAYER V2 ;
			RECT 0.021 19.0867 0.0359 19.0992 ;
		END

		ANTENNADIFFAREA 0.00194719 ;
		ANTENNAPARTIALMETALAREA 0.00195671 ;
	END Q[14]

	PIN Q[15]
		USE SIGNAL ;
		DIRECTION OUTPUT ;
		SHAPE ABUTMENT ;
		PORT
			 LAYER M2 ;
			RECT 0.0098 20.2918 0.0481 20.3922 ;
			 LAYER M3 ;
			RECT 0.0098 20.2918 0.0481 20.3922 ;
			 LAYER V2 ;
			RECT 0.021 20.3667 0.0359 20.3792 ;
		END

		ANTENNADIFFAREA 0.00194719 ;
		ANTENNAPARTIALMETALAREA 0.00195671 ;
	END Q[15]

	PIN Q[16]
		USE SIGNAL ;
		DIRECTION OUTPUT ;
		SHAPE ABUTMENT ;
		PORT
			 LAYER M2 ;
			RECT 0.0098 28.7184 0.0481 28.8188 ;
			 LAYER M3 ;
			RECT 0.0098 28.7184 0.0481 28.8188 ;
			 LAYER V2 ;
			RECT 0.021 28.7314 0.0359 28.7439 ;
		END

		ANTENNADIFFAREA 0.00194719 ;
		ANTENNAPARTIALMETALAREA 0.00195671 ;
	END Q[16]

	PIN Q[17]
		USE SIGNAL ;
		DIRECTION OUTPUT ;
		SHAPE ABUTMENT ;
		PORT
			 LAYER M2 ;
			RECT 0.0098 29.9984 0.0481 30.0988 ;
			 LAYER M3 ;
			RECT 0.0098 29.9984 0.0481 30.0988 ;
			 LAYER V2 ;
			RECT 0.021 30.0114 0.0359 30.0239 ;
		END

		ANTENNADIFFAREA 0.00194719 ;
		ANTENNAPARTIALMETALAREA 0.00195671 ;
	END Q[17]

	PIN Q[18]
		USE SIGNAL ;
		DIRECTION OUTPUT ;
		SHAPE ABUTMENT ;
		PORT
			 LAYER M2 ;
			RECT 0.0098 31.2784 0.0481 31.3788 ;
			 LAYER M3 ;
			RECT 0.0098 31.2784 0.0481 31.3788 ;
			 LAYER V2 ;
			RECT 0.021 31.2914 0.0359 31.3039 ;
		END

		ANTENNADIFFAREA 0.00194719 ;
		ANTENNAPARTIALMETALAREA 0.00195671 ;
	END Q[18]

	PIN Q[19]
		USE SIGNAL ;
		DIRECTION OUTPUT ;
		SHAPE ABUTMENT ;
		PORT
			 LAYER M2 ;
			RECT 0.0098 32.5584 0.0481 32.6588 ;
			 LAYER M3 ;
			RECT 0.0098 32.5584 0.0481 32.6588 ;
			 LAYER V2 ;
			RECT 0.021 32.5714 0.0359 32.5839 ;
		END

		ANTENNADIFFAREA 0.00194719 ;
		ANTENNAPARTIALMETALAREA 0.00195671 ;
	END Q[19]

	PIN Q[1]
		USE SIGNAL ;
		DIRECTION OUTPUT ;
		SHAPE ABUTMENT ;
		PORT
			 LAYER M2 ;
			RECT 0.0098 2.3718 0.0481 2.4722 ;
			 LAYER M3 ;
			RECT 0.0098 2.3718 0.0481 2.4722 ;
			 LAYER V2 ;
			RECT 0.021 2.4467 0.0359 2.4592 ;
		END

		ANTENNADIFFAREA 0.00194719 ;
		ANTENNAPARTIALMETALAREA 0.00195671 ;
	END Q[1]

	PIN Q[20]
		USE SIGNAL ;
		DIRECTION OUTPUT ;
		SHAPE ABUTMENT ;
		PORT
			 LAYER M2 ;
			RECT 0.0098 33.8384 0.0481 33.9388 ;
			 LAYER M3 ;
			RECT 0.0098 33.8384 0.0481 33.9388 ;
			 LAYER V2 ;
			RECT 0.021 33.8514 0.0359 33.8639 ;
		END

		ANTENNADIFFAREA 0.00194719 ;
		ANTENNAPARTIALMETALAREA 0.00195671 ;
	END Q[20]

	PIN Q[21]
		USE SIGNAL ;
		DIRECTION OUTPUT ;
		SHAPE ABUTMENT ;
		PORT
			 LAYER M2 ;
			RECT 0.0098 35.1184 0.0481 35.2188 ;
			 LAYER M3 ;
			RECT 0.0098 35.1184 0.0481 35.2188 ;
			 LAYER V2 ;
			RECT 0.021 35.1314 0.0359 35.1439 ;
		END

		ANTENNADIFFAREA 0.00194719 ;
		ANTENNAPARTIALMETALAREA 0.00195671 ;
	END Q[21]

	PIN Q[22]
		USE SIGNAL ;
		DIRECTION OUTPUT ;
		SHAPE ABUTMENT ;
		PORT
			 LAYER M2 ;
			RECT 0.0098 36.3984 0.0481 36.4988 ;
			 LAYER M3 ;
			RECT 0.0098 36.3984 0.0481 36.4988 ;
			 LAYER V2 ;
			RECT 0.021 36.4114 0.0359 36.4239 ;
		END

		ANTENNADIFFAREA 0.00194719 ;
		ANTENNAPARTIALMETALAREA 0.00195671 ;
	END Q[22]

	PIN Q[23]
		USE SIGNAL ;
		DIRECTION OUTPUT ;
		SHAPE ABUTMENT ;
		PORT
			 LAYER M2 ;
			RECT 0.0098 37.6784 0.0481 37.7788 ;
			 LAYER M3 ;
			RECT 0.0098 37.6784 0.0481 37.7788 ;
			 LAYER V2 ;
			RECT 0.021 37.6914 0.0359 37.7039 ;
		END

		ANTENNADIFFAREA 0.00194719 ;
		ANTENNAPARTIALMETALAREA 0.00195671 ;
	END Q[23]

	PIN Q[24]
		USE SIGNAL ;
		DIRECTION OUTPUT ;
		SHAPE ABUTMENT ;
		PORT
			 LAYER M2 ;
			RECT 0.0098 38.9584 0.0481 39.0588 ;
			 LAYER M3 ;
			RECT 0.0098 38.9584 0.0481 39.0588 ;
			 LAYER V2 ;
			RECT 0.021 38.9714 0.0359 38.9839 ;
		END

		ANTENNADIFFAREA 0.00194719 ;
		ANTENNAPARTIALMETALAREA 0.00195671 ;
	END Q[24]

	PIN Q[25]
		USE SIGNAL ;
		DIRECTION OUTPUT ;
		SHAPE ABUTMENT ;
		PORT
			 LAYER M2 ;
			RECT 0.0098 40.2384 0.0481 40.3388 ;
			 LAYER M3 ;
			RECT 0.0098 40.2384 0.0481 40.3388 ;
			 LAYER V2 ;
			RECT 0.021 40.2514 0.0359 40.2639 ;
		END

		ANTENNADIFFAREA 0.00194719 ;
		ANTENNAPARTIALMETALAREA 0.00195671 ;
	END Q[25]

	PIN Q[26]
		USE SIGNAL ;
		DIRECTION OUTPUT ;
		SHAPE ABUTMENT ;
		PORT
			 LAYER M2 ;
			RECT 0.0098 41.5184 0.0481 41.6188 ;
			 LAYER M3 ;
			RECT 0.0098 41.5184 0.0481 41.6188 ;
			 LAYER V2 ;
			RECT 0.021 41.5314 0.0359 41.5439 ;
		END

		ANTENNADIFFAREA 0.00194719 ;
		ANTENNAPARTIALMETALAREA 0.00195671 ;
	END Q[26]

	PIN Q[27]
		USE SIGNAL ;
		DIRECTION OUTPUT ;
		SHAPE ABUTMENT ;
		PORT
			 LAYER M2 ;
			RECT 0.0098 42.7984 0.0481 42.8988 ;
			 LAYER M3 ;
			RECT 0.0098 42.7984 0.0481 42.8988 ;
			 LAYER V2 ;
			RECT 0.021 42.8114 0.0359 42.8239 ;
		END

		ANTENNADIFFAREA 0.00194719 ;
		ANTENNAPARTIALMETALAREA 0.00195671 ;
	END Q[27]

	PIN Q[28]
		USE SIGNAL ;
		DIRECTION OUTPUT ;
		SHAPE ABUTMENT ;
		PORT
			 LAYER M2 ;
			RECT 0.0098 44.0784 0.0481 44.1788 ;
			 LAYER M3 ;
			RECT 0.0098 44.0784 0.0481 44.1788 ;
			 LAYER V2 ;
			RECT 0.021 44.0914 0.0359 44.1039 ;
		END

		ANTENNADIFFAREA 0.00194719 ;
		ANTENNAPARTIALMETALAREA 0.00195671 ;
	END Q[28]

	PIN Q[29]
		USE SIGNAL ;
		DIRECTION OUTPUT ;
		SHAPE ABUTMENT ;
		PORT
			 LAYER M2 ;
			RECT 0.0098 45.3584 0.0481 45.4588 ;
			 LAYER M3 ;
			RECT 0.0098 45.3584 0.0481 45.4588 ;
			 LAYER V2 ;
			RECT 0.021 45.3714 0.0359 45.3839 ;
		END

		ANTENNADIFFAREA 0.00194719 ;
		ANTENNAPARTIALMETALAREA 0.00195671 ;
	END Q[29]

	PIN Q[2]
		USE SIGNAL ;
		DIRECTION OUTPUT ;
		SHAPE ABUTMENT ;
		PORT
			 LAYER M2 ;
			RECT 0.0098 3.6518 0.0481 3.7522 ;
			 LAYER M3 ;
			RECT 0.0098 3.6518 0.0481 3.7522 ;
			 LAYER V2 ;
			RECT 0.021 3.7267 0.0359 3.7392 ;
		END

		ANTENNADIFFAREA 0.00194719 ;
		ANTENNAPARTIALMETALAREA 0.00195671 ;
	END Q[2]

	PIN Q[30]
		USE SIGNAL ;
		DIRECTION OUTPUT ;
		SHAPE ABUTMENT ;
		PORT
			 LAYER M2 ;
			RECT 0.0098 46.6384 0.0481 46.7388 ;
			 LAYER M3 ;
			RECT 0.0098 46.6384 0.0481 46.7388 ;
			 LAYER V2 ;
			RECT 0.021 46.6514 0.0359 46.6639 ;
		END

		ANTENNADIFFAREA 0.00194719 ;
		ANTENNAPARTIALMETALAREA 0.00195671 ;
	END Q[30]

	PIN Q[31]
		USE SIGNAL ;
		DIRECTION OUTPUT ;
		SHAPE ABUTMENT ;
		PORT
			 LAYER M2 ;
			RECT 0.0098 47.9184 0.0481 48.0188 ;
			 LAYER M3 ;
			RECT 0.0098 47.9184 0.0481 48.0188 ;
			 LAYER V2 ;
			RECT 0.021 47.9314 0.0359 47.9439 ;
		END

		ANTENNADIFFAREA 0.00194719 ;
		ANTENNAPARTIALMETALAREA 0.00195671 ;
	END Q[31]

	PIN Q[3]
		USE SIGNAL ;
		DIRECTION OUTPUT ;
		SHAPE ABUTMENT ;
		PORT
			 LAYER M2 ;
			RECT 0.0098 4.9318 0.0481 5.0322 ;
			 LAYER M3 ;
			RECT 0.0098 4.9318 0.0481 5.0322 ;
			 LAYER V2 ;
			RECT 0.021 5.0067 0.0359 5.0192 ;
		END

		ANTENNADIFFAREA 0.00194719 ;
		ANTENNAPARTIALMETALAREA 0.00195671 ;
	END Q[3]

	PIN Q[4]
		USE SIGNAL ;
		DIRECTION OUTPUT ;
		SHAPE ABUTMENT ;
		PORT
			 LAYER M2 ;
			RECT 0.0098 6.2118 0.0481 6.3122 ;
			 LAYER M3 ;
			RECT 0.0098 6.2118 0.0481 6.3122 ;
			 LAYER V2 ;
			RECT 0.021 6.2867 0.0359 6.2992 ;
		END

		ANTENNADIFFAREA 0.00194719 ;
		ANTENNAPARTIALMETALAREA 0.00195671 ;
	END Q[4]

	PIN Q[5]
		USE SIGNAL ;
		DIRECTION OUTPUT ;
		SHAPE ABUTMENT ;
		PORT
			 LAYER M2 ;
			RECT 0.0098 7.4918 0.0481 7.5922 ;
			 LAYER M3 ;
			RECT 0.0098 7.4918 0.0481 7.5922 ;
			 LAYER V2 ;
			RECT 0.021 7.5667 0.0359 7.5792 ;
		END

		ANTENNADIFFAREA 0.00194719 ;
		ANTENNAPARTIALMETALAREA 0.00195671 ;
	END Q[5]

	PIN Q[6]
		USE SIGNAL ;
		DIRECTION OUTPUT ;
		SHAPE ABUTMENT ;
		PORT
			 LAYER M2 ;
			RECT 0.0098 8.7718 0.0481 8.8722 ;
			 LAYER M3 ;
			RECT 0.0098 8.7718 0.0481 8.8722 ;
			 LAYER V2 ;
			RECT 0.021 8.8467 0.0359 8.8592 ;
		END

		ANTENNADIFFAREA 0.00194719 ;
		ANTENNAPARTIALMETALAREA 0.00195671 ;
	END Q[6]

	PIN Q[7]
		USE SIGNAL ;
		DIRECTION OUTPUT ;
		SHAPE ABUTMENT ;
		PORT
			 LAYER M2 ;
			RECT 0.0098 10.0518 0.0481 10.1522 ;
			 LAYER M3 ;
			RECT 0.0098 10.0518 0.0481 10.1522 ;
			 LAYER V2 ;
			RECT 0.021 10.1267 0.0359 10.1392 ;
		END

		ANTENNADIFFAREA 0.00194719 ;
		ANTENNAPARTIALMETALAREA 0.00195671 ;
	END Q[7]

	PIN Q[8]
		USE SIGNAL ;
		DIRECTION OUTPUT ;
		SHAPE ABUTMENT ;
		PORT
			 LAYER M2 ;
			RECT 0.0098 11.3318 0.0481 11.4322 ;
			 LAYER M3 ;
			RECT 0.0098 11.3318 0.0481 11.4322 ;
			 LAYER V2 ;
			RECT 0.021 11.4067 0.0359 11.4192 ;
		END

		ANTENNADIFFAREA 0.00194719 ;
		ANTENNAPARTIALMETALAREA 0.00195671 ;
	END Q[8]

	PIN Q[9]
		USE SIGNAL ;
		DIRECTION OUTPUT ;
		SHAPE ABUTMENT ;
		PORT
			 LAYER M2 ;
			RECT 0.0098 12.6118 0.0481 12.7122 ;
			 LAYER M3 ;
			RECT 0.0098 12.6118 0.0481 12.7122 ;
			 LAYER V2 ;
			RECT 0.021 12.6867 0.0359 12.6992 ;
		END

		ANTENNADIFFAREA 0.00194719 ;
		ANTENNAPARTIALMETALAREA 0.00195671 ;
	END Q[9]

	PIN RAWL
		USE SIGNAL ;
		DIRECTION INPUT ;
		SHAPE ABUTMENT ;
		PORT
			 LAYER M2 ;
			RECT 0.0714 21.1702 0.1097 21.2078 ;
			 LAYER M3 ;
			RECT 0.0714 21.1702 0.1097 21.2706 ;
			 LAYER V2 ;
			RECT 0.0831 21.1824 0.098 21.1949 ;
		END

		ANTENNAGATEAREA 0.00027817 ;
		ANTENNADIFFAREA 0.00194719 ;
		ANTENNAPARTIALMETALAREA 0.00195671 ;
	END RAWL

	PIN RAWLM[0]
		USE SIGNAL ;
		DIRECTION INPUT ;
		SHAPE ABUTMENT ;
		PORT
			 LAYER M2 ;
			RECT 0.0098 24.9349 0.0481 24.9725 ;
		END

		ANTENNAGATEAREA 0.00027817 ;
		ANTENNADIFFAREA 0.00194719 ;
		ANTENNAPARTIALMETALAREA 0.00195671 ;
	END RAWLM[0]

	PIN RAWLM[1]
		USE SIGNAL ;
		DIRECTION INPUT ;
		SHAPE ABUTMENT ;
		PORT
			 LAYER M3 ;
			RECT 0.0714 25.8384 0.1097 25.9388 ;
		END

		ANTENNAGATEAREA 0.00027817 ;
		ANTENNADIFFAREA 0.00194719 ;
		ANTENNAPARTIALMETALAREA 0.00195671 ;
	END RAWLM[1]

	PIN RET1N
		USE SIGNAL ;
		DIRECTION INPUT ;
		SHAPE ABUTMENT ;
		PORT
			 LAYER M2 ;
			RECT 0.0098 22.7388 0.0481 22.7765 ;
			 LAYER M3 ;
			RECT 0.0098 22.6761 0.0481 22.7765 ;
			 LAYER V2 ;
			RECT 0.0215 22.751 0.0364 22.7635 ;
		END

		ANTENNAGATEAREA 0.00027817 ;
		ANTENNADIFFAREA 0.00194719 ;
		ANTENNAPARTIALMETALAREA 0.00195671 ;
	END RET1N

	PIN SE
		USE SIGNAL ;
		DIRECTION INPUT ;
		SHAPE ABUTMENT ;
		PORT
			 LAYER M3 ;
			RECT 0.0714 25.989 0.1097 26.0894 ;
		END

		ANTENNAGATEAREA 0.00027817 ;
		ANTENNADIFFAREA 0.00194719 ;
		ANTENNAPARTIALMETALAREA 0.00195671 ;
	END SE

	PIN SI[0]
		USE SIGNAL ;
		DIRECTION INPUT ;
		SHAPE ABUTMENT ;
		PORT
			 LAYER M2 ;
			RECT 0.0714 0.0627 0.1097 0.1004 ;
			 LAYER M3 ;
			RECT 0.0714 0.0627 0.1097 0.1631 ;
			 LAYER V2 ;
			RECT 0.0831 0.0749 0.098 0.0875 ;
		END

		ANTENNAGATEAREA 0.00027817 ;
		ANTENNADIFFAREA 0.00194719 ;
		ANTENNAPARTIALMETALAREA 0.00195671 ;
	END SI[0]

	PIN SI[1]
		USE SIGNAL ;
		DIRECTION INPUT ;
		SHAPE ABUTMENT ;
		PORT
			 LAYER M2 ;
			RECT 0.0714 49.0102 0.1097 49.0478 ;
			 LAYER M3 ;
			RECT 0.0714 48.9475 0.1097 49.0478 ;
			 LAYER V2 ;
			RECT 0.0831 49.0231 0.098 49.0357 ;
		END

		ANTENNAGATEAREA 0.00027817 ;
		ANTENNADIFFAREA 0.00194719 ;
		ANTENNAPARTIALMETALAREA 0.00195671 ;
	END SI[1]

	PIN SO[0]
		USE SIGNAL ;
		DIRECTION OUTPUT ;
		SHAPE ABUTMENT ;
		PORT
			 LAYER M2 ;
			RECT 0.0714 26.742 0.1097 26.7796 ;
			 LAYER M3 ;
			RECT 0.0714 26.742 0.1097 26.8424 ;
			 LAYER V2 ;
			RECT 0.0831 26.7541 0.098 26.7667 ;
		END

		ANTENNADIFFAREA 0.00194719 ;
		ANTENNAPARTIALMETALAREA 0.00195671 ;
	END SO[0]

	PIN SO[1]
		USE SIGNAL ;
		DIRECTION OUTPUT ;
		SHAPE ABUTMENT ;
		PORT
			 LAYER M2 ;
			RECT 0.0714 24.7843 0.1097 24.822 ;
			 LAYER M3 ;
			RECT 0.0714 24.7843 0.1097 24.8847 ;
			 LAYER V2 ;
			RECT 0.0831 24.7965 0.098 24.809 ;
		END

		ANTENNADIFFAREA 0.00194719 ;
		ANTENNAPARTIALMETALAREA 0.00195671 ;
	END SO[1]

	PIN STOV
		USE SIGNAL ;
		DIRECTION INPUT ;
		SHAPE ABUTMENT ;
		PORT
			 LAYER M2 ;
			RECT 0.0098 23.1906 0.0481 23.2282 ;
			 LAYER M3 ;
			RECT 0.0098 23.1278 0.0481 23.2282 ;
			 LAYER V2 ;
			RECT 0.0215 23.2027 0.0364 23.2153 ;
		END

		ANTENNAGATEAREA 0.00027817 ;
		ANTENNADIFFAREA 0.00194719 ;
		ANTENNAPARTIALMETALAREA 0.00195671 ;
	END STOV

	PIN TA[0]
		USE SIGNAL ;
		DIRECTION INPUT ;
		SHAPE ABUTMENT ;
		PORT
			 LAYER M2 ;
			RECT 0.0098 23.9435 0.0481 23.9812 ;
			 LAYER M3 ;
			RECT 0.0098 23.8808 0.0481 23.9812 ;
			 LAYER V2 ;
			RECT 0.0215 23.9557 0.0364 23.9682 ;
		END

		ANTENNAGATEAREA 0.00027817 ;
		ANTENNADIFFAREA 0.00194719 ;
		ANTENNAPARTIALMETALAREA 0.00195671 ;
	END TA[0]

	PIN TA[1]
		USE SIGNAL ;
		DIRECTION INPUT ;
		SHAPE ABUTMENT ;
		PORT
			 LAYER M2 ;
			RECT 0.0714 24.182 0.1097 24.2196 ;
			 LAYER M3 ;
			RECT 0.0714 24.182 0.1097 24.2824 ;
			 LAYER V2 ;
			RECT 0.0831 24.1941 0.098 24.2067 ;
		END

		ANTENNAGATEAREA 0.00027817 ;
		ANTENNADIFFAREA 0.00194719 ;
		ANTENNAPARTIALMETALAREA 0.00195671 ;
	END TA[1]

	PIN TA[2]
		USE SIGNAL ;
		DIRECTION INPUT ;
		SHAPE ABUTMENT ;
		PORT
			 LAYER M2 ;
			RECT 0.0098 24.5459 0.0481 24.5835 ;
			 LAYER M3 ;
			RECT 0.0098 24.4831 0.0481 24.5835 ;
			 LAYER V2 ;
			RECT 0.0215 24.558 0.0364 24.5706 ;
		END

		ANTENNAGATEAREA 0.00027817 ;
		ANTENNADIFFAREA 0.00194719 ;
		ANTENNAPARTIALMETALAREA 0.00195671 ;
	END TA[2]

	PIN TA[3]
		USE SIGNAL ;
		DIRECTION INPUT ;
		SHAPE ABUTMENT ;
		PORT
			 LAYER M2 ;
			RECT 0.0714 25.2361 0.1097 25.2737 ;
			 LAYER M3 ;
			RECT 0.0714 25.2361 0.1097 25.3365 ;
			 LAYER V2 ;
			RECT 0.0831 25.2482 0.098 25.2608 ;
		END

		ANTENNAGATEAREA 0.00027817 ;
		ANTENNADIFFAREA 0.00194719 ;
		ANTENNAPARTIALMETALAREA 0.00195671 ;
	END TA[3]

	PIN TA[4]
		USE SIGNAL ;
		DIRECTION INPUT ;
		SHAPE ABUTMENT ;
		PORT
			 LAYER M2 ;
			RECT 0.0098 24.3953 0.0481 24.4329 ;
			 LAYER M3 ;
			RECT 0.0098 24.3325 0.0481 24.4329 ;
			 LAYER V2 ;
			RECT 0.0215 24.4075 0.0364 24.42 ;
		END

		ANTENNAGATEAREA 0.00027817 ;
		ANTENNADIFFAREA 0.00194719 ;
		ANTENNAPARTIALMETALAREA 0.00195671 ;
	END TA[4]

	PIN TA[5]
		USE SIGNAL ;
		DIRECTION INPUT ;
		SHAPE ABUTMENT ;
		PORT
			 LAYER M2 ;
			RECT 0.0098 25.5373 0.0481 25.5749 ;
		END

		ANTENNAGATEAREA 0.00027817 ;
		ANTENNADIFFAREA 0.00194719 ;
		ANTENNAPARTIALMETALAREA 0.00195671 ;
	END TA[5]

	PIN TA[6]
		USE SIGNAL ;
		DIRECTION INPUT ;
		SHAPE ABUTMENT ;
		PORT
			 LAYER M2 ;
			RECT 0.0098 25.989 0.0481 26.0267 ;
		END

		ANTENNAGATEAREA 0.00027817 ;
		ANTENNADIFFAREA 0.00194719 ;
		ANTENNAPARTIALMETALAREA 0.00195671 ;
	END TA[6]

	PIN TA[7]
		USE SIGNAL ;
		DIRECTION INPUT ;
		SHAPE ABUTMENT ;
		PORT
			 LAYER M2 ;
			RECT 0.0098 26.8047 0.0481 26.8424 ;
			 LAYER M3 ;
			RECT 0.0098 26.742 0.0481 26.8424 ;
			 LAYER V2 ;
			RECT 0.0215 26.8169 0.0364 26.8294 ;
		END

		ANTENNAGATEAREA 0.00027817 ;
		ANTENNADIFFAREA 0.00194719 ;
		ANTENNAPARTIALMETALAREA 0.00195671 ;
	END TA[7]

	PIN TA[8]
		USE SIGNAL ;
		DIRECTION INPUT ;
		SHAPE ABUTMENT ;
		PORT
			 LAYER M2 ;
			RECT 0.0714 26.2902 0.1097 26.3278 ;
			 LAYER M3 ;
			RECT 0.0714 26.2902 0.1097 26.3906 ;
			 LAYER V2 ;
			RECT 0.0831 26.3024 0.098 26.3149 ;
		END

		ANTENNAGATEAREA 0.00027817 ;
		ANTENNADIFFAREA 0.00194719 ;
		ANTENNAPARTIALMETALAREA 0.00195671 ;
	END TA[8]

	PIN TA[9]
		USE SIGNAL ;
		DIRECTION INPUT ;
		SHAPE ABUTMENT ;
		PORT
			 LAYER M2 ;
			RECT 0.0714 27.3443 0.1097 27.382 ;
			 LAYER M3 ;
			RECT 0.0714 27.3443 0.1097 27.4447 ;
			 LAYER V2 ;
			RECT 0.0831 27.3565 0.098 27.369 ;
		END

		ANTENNAGATEAREA 0.00027817 ;
		ANTENNADIFFAREA 0.00194719 ;
		ANTENNAPARTIALMETALAREA 0.00195671 ;
	END TA[9]

	PIN TCEN
		USE SIGNAL ;
		DIRECTION INPUT ;
		SHAPE ABUTMENT ;
		PORT
			 LAYER M2 ;
			RECT 0.0098 23.3412 0.0481 23.3788 ;
			 LAYER M3 ;
			RECT 0.0098 23.2784 0.0481 23.3788 ;
			 LAYER V2 ;
			RECT 0.0215 23.3533 0.0364 23.3659 ;
		END

		ANTENNAGATEAREA 0.00027817 ;
		ANTENNADIFFAREA 0.00194719 ;
		ANTENNAPARTIALMETALAREA 0.00195671 ;
	END TCEN

	PIN TD[0]
		USE SIGNAL ;
		DIRECTION INPUT ;
		SHAPE ABUTMENT ;
		PORT
			 LAYER M2 ;
			RECT 0.0098 0.9663 0.0481 1.0039 ;
			 LAYER M3 ;
			RECT 0.0098 0.9663 0.0481 1.0667 ;
			 LAYER V2 ;
			RECT 0.0215 0.9792 0.0364 0.9918 ;
		END

		ANTENNAGATEAREA 0.00027817 ;
		ANTENNADIFFAREA 0.00194719 ;
		ANTENNAPARTIALMETALAREA 0.00195671 ;
	END TD[0]

	PIN TD[10]
		USE SIGNAL ;
		DIRECTION INPUT ;
		SHAPE ABUTMENT ;
		PORT
			 LAYER M2 ;
			RECT 0.0098 13.7663 0.0481 13.8039 ;
			 LAYER M3 ;
			RECT 0.0098 13.7663 0.0481 13.8667 ;
			 LAYER V2 ;
			RECT 0.0215 13.7792 0.0364 13.7918 ;
		END

		ANTENNAGATEAREA 0.00027817 ;
		ANTENNADIFFAREA 0.00194719 ;
		ANTENNAPARTIALMETALAREA 0.00195671 ;
	END TD[10]

	PIN TD[11]
		USE SIGNAL ;
		DIRECTION INPUT ;
		SHAPE ABUTMENT ;
		PORT
			 LAYER M2 ;
			RECT 0.0098 15.0463 0.0481 15.0839 ;
			 LAYER M3 ;
			RECT 0.0098 15.0463 0.0481 15.1467 ;
			 LAYER V2 ;
			RECT 0.0215 15.0592 0.0364 15.0718 ;
		END

		ANTENNAGATEAREA 0.00027817 ;
		ANTENNADIFFAREA 0.00194719 ;
		ANTENNAPARTIALMETALAREA 0.00195671 ;
	END TD[11]

	PIN TD[12]
		USE SIGNAL ;
		DIRECTION INPUT ;
		SHAPE ABUTMENT ;
		PORT
			 LAYER M2 ;
			RECT 0.0098 16.3263 0.0481 16.3639 ;
			 LAYER M3 ;
			RECT 0.0098 16.3263 0.0481 16.4267 ;
			 LAYER V2 ;
			RECT 0.0215 16.3392 0.0364 16.3518 ;
		END

		ANTENNAGATEAREA 0.00027817 ;
		ANTENNADIFFAREA 0.00194719 ;
		ANTENNAPARTIALMETALAREA 0.00195671 ;
	END TD[12]

	PIN TD[13]
		USE SIGNAL ;
		DIRECTION INPUT ;
		SHAPE ABUTMENT ;
		PORT
			 LAYER M2 ;
			RECT 0.0098 17.6063 0.0481 17.6439 ;
			 LAYER M3 ;
			RECT 0.0098 17.6063 0.0481 17.7067 ;
			 LAYER V2 ;
			RECT 0.0215 17.6192 0.0364 17.6318 ;
		END

		ANTENNAGATEAREA 0.00027817 ;
		ANTENNADIFFAREA 0.00194719 ;
		ANTENNAPARTIALMETALAREA 0.00195671 ;
	END TD[13]

	PIN TD[14]
		USE SIGNAL ;
		DIRECTION INPUT ;
		SHAPE ABUTMENT ;
		PORT
			 LAYER M2 ;
			RECT 0.0098 18.8863 0.0481 18.9239 ;
			 LAYER M3 ;
			RECT 0.0098 18.8863 0.0481 18.9867 ;
			 LAYER V2 ;
			RECT 0.0215 18.8992 0.0364 18.9118 ;
		END

		ANTENNAGATEAREA 0.00027817 ;
		ANTENNADIFFAREA 0.00194719 ;
		ANTENNAPARTIALMETALAREA 0.00195671 ;
	END TD[14]

	PIN TD[15]
		USE SIGNAL ;
		DIRECTION INPUT ;
		SHAPE ABUTMENT ;
		PORT
			 LAYER M2 ;
			RECT 0.0098 20.1663 0.0481 20.2039 ;
			 LAYER M3 ;
			RECT 0.0098 20.1663 0.0481 20.2667 ;
			 LAYER V2 ;
			RECT 0.0215 20.1792 0.0364 20.1918 ;
		END

		ANTENNAGATEAREA 0.00027817 ;
		ANTENNADIFFAREA 0.00194719 ;
		ANTENNAPARTIALMETALAREA 0.00195671 ;
	END TD[15]

	PIN TD[16]
		USE SIGNAL ;
		DIRECTION INPUT ;
		SHAPE ABUTMENT ;
		PORT
			 LAYER M2 ;
			RECT 0.0098 28.9067 0.0481 28.9443 ;
			 LAYER M3 ;
			RECT 0.0098 28.8439 0.0481 28.9443 ;
			 LAYER V2 ;
			RECT 0.0215 28.9188 0.0364 28.9314 ;
		END

		ANTENNAGATEAREA 0.00027817 ;
		ANTENNADIFFAREA 0.00194719 ;
		ANTENNAPARTIALMETALAREA 0.00195671 ;
	END TD[16]

	PIN TD[17]
		USE SIGNAL ;
		DIRECTION INPUT ;
		SHAPE ABUTMENT ;
		PORT
			 LAYER M2 ;
			RECT 0.0098 30.1867 0.0481 30.2243 ;
			 LAYER M3 ;
			RECT 0.0098 30.1239 0.0481 30.2243 ;
			 LAYER V2 ;
			RECT 0.0215 30.1988 0.0364 30.2114 ;
		END

		ANTENNAGATEAREA 0.00027817 ;
		ANTENNADIFFAREA 0.00194719 ;
		ANTENNAPARTIALMETALAREA 0.00195671 ;
	END TD[17]

	PIN TD[18]
		USE SIGNAL ;
		DIRECTION INPUT ;
		SHAPE ABUTMENT ;
		PORT
			 LAYER M2 ;
			RECT 0.0098 31.4667 0.0481 31.5043 ;
			 LAYER M3 ;
			RECT 0.0098 31.4039 0.0481 31.5043 ;
			 LAYER V2 ;
			RECT 0.0215 31.4788 0.0364 31.4914 ;
		END

		ANTENNAGATEAREA 0.00027817 ;
		ANTENNADIFFAREA 0.00194719 ;
		ANTENNAPARTIALMETALAREA 0.00195671 ;
	END TD[18]

	PIN TD[19]
		USE SIGNAL ;
		DIRECTION INPUT ;
		SHAPE ABUTMENT ;
		PORT
			 LAYER M2 ;
			RECT 0.0098 32.7467 0.0481 32.7843 ;
			 LAYER M3 ;
			RECT 0.0098 32.6839 0.0481 32.7843 ;
			 LAYER V2 ;
			RECT 0.0215 32.7588 0.0364 32.7714 ;
		END

		ANTENNAGATEAREA 0.00027817 ;
		ANTENNADIFFAREA 0.00194719 ;
		ANTENNAPARTIALMETALAREA 0.00195671 ;
	END TD[19]

	PIN TD[1]
		USE SIGNAL ;
		DIRECTION INPUT ;
		SHAPE ABUTMENT ;
		PORT
			 LAYER M2 ;
			RECT 0.0098 2.2463 0.0481 2.2839 ;
			 LAYER M3 ;
			RECT 0.0098 2.2463 0.0481 2.3467 ;
			 LAYER V2 ;
			RECT 0.0215 2.2592 0.0364 2.2718 ;
		END

		ANTENNAGATEAREA 0.00027817 ;
		ANTENNADIFFAREA 0.00194719 ;
		ANTENNAPARTIALMETALAREA 0.00195671 ;
	END TD[1]

	PIN TD[20]
		USE SIGNAL ;
		DIRECTION INPUT ;
		SHAPE ABUTMENT ;
		PORT
			 LAYER M2 ;
			RECT 0.0098 34.0267 0.0481 34.0643 ;
			 LAYER M3 ;
			RECT 0.0098 33.9639 0.0481 34.0643 ;
			 LAYER V2 ;
			RECT 0.0215 34.0388 0.0364 34.0514 ;
		END

		ANTENNAGATEAREA 0.00027817 ;
		ANTENNADIFFAREA 0.00194719 ;
		ANTENNAPARTIALMETALAREA 0.00195671 ;
	END TD[20]

	PIN TD[21]
		USE SIGNAL ;
		DIRECTION INPUT ;
		SHAPE ABUTMENT ;
		PORT
			 LAYER M2 ;
			RECT 0.0098 35.3067 0.0481 35.3443 ;
			 LAYER M3 ;
			RECT 0.0098 35.2439 0.0481 35.3443 ;
			 LAYER V2 ;
			RECT 0.0215 35.3188 0.0364 35.3314 ;
		END

		ANTENNAGATEAREA 0.00027817 ;
		ANTENNADIFFAREA 0.00194719 ;
		ANTENNAPARTIALMETALAREA 0.00195671 ;
	END TD[21]

	PIN TD[22]
		USE SIGNAL ;
		DIRECTION INPUT ;
		SHAPE ABUTMENT ;
		PORT
			 LAYER M2 ;
			RECT 0.0098 36.5867 0.0481 36.6243 ;
			 LAYER M3 ;
			RECT 0.0098 36.5239 0.0481 36.6243 ;
			 LAYER V2 ;
			RECT 0.0215 36.5988 0.0364 36.6114 ;
		END

		ANTENNAGATEAREA 0.00027817 ;
		ANTENNADIFFAREA 0.00194719 ;
		ANTENNAPARTIALMETALAREA 0.00195671 ;
	END TD[22]

	PIN TD[23]
		USE SIGNAL ;
		DIRECTION INPUT ;
		SHAPE ABUTMENT ;
		PORT
			 LAYER M2 ;
			RECT 0.0098 37.8667 0.0481 37.9043 ;
			 LAYER M3 ;
			RECT 0.0098 37.8039 0.0481 37.9043 ;
			 LAYER V2 ;
			RECT 0.0215 37.8788 0.0364 37.8914 ;
		END

		ANTENNAGATEAREA 0.00027817 ;
		ANTENNADIFFAREA 0.00194719 ;
		ANTENNAPARTIALMETALAREA 0.00195671 ;
	END TD[23]

	PIN TD[24]
		USE SIGNAL ;
		DIRECTION INPUT ;
		SHAPE ABUTMENT ;
		PORT
			 LAYER M2 ;
			RECT 0.0098 39.1467 0.0481 39.1843 ;
			 LAYER M3 ;
			RECT 0.0098 39.0839 0.0481 39.1843 ;
			 LAYER V2 ;
			RECT 0.0215 39.1588 0.0364 39.1714 ;
		END

		ANTENNAGATEAREA 0.00027817 ;
		ANTENNADIFFAREA 0.00194719 ;
		ANTENNAPARTIALMETALAREA 0.00195671 ;
	END TD[24]

	PIN TD[25]
		USE SIGNAL ;
		DIRECTION INPUT ;
		SHAPE ABUTMENT ;
		PORT
			 LAYER M2 ;
			RECT 0.0098 40.4267 0.0481 40.4643 ;
			 LAYER M3 ;
			RECT 0.0098 40.3639 0.0481 40.4643 ;
			 LAYER V2 ;
			RECT 0.0215 40.4388 0.0364 40.4514 ;
		END

		ANTENNAGATEAREA 0.00027817 ;
		ANTENNADIFFAREA 0.00194719 ;
		ANTENNAPARTIALMETALAREA 0.00195671 ;
	END TD[25]

	PIN TD[26]
		USE SIGNAL ;
		DIRECTION INPUT ;
		SHAPE ABUTMENT ;
		PORT
			 LAYER M2 ;
			RECT 0.0098 41.7067 0.0481 41.7443 ;
			 LAYER M3 ;
			RECT 0.0098 41.6439 0.0481 41.7443 ;
			 LAYER V2 ;
			RECT 0.0215 41.7188 0.0364 41.7314 ;
		END

		ANTENNAGATEAREA 0.00027817 ;
		ANTENNADIFFAREA 0.00194719 ;
		ANTENNAPARTIALMETALAREA 0.00195671 ;
	END TD[26]

	PIN TD[27]
		USE SIGNAL ;
		DIRECTION INPUT ;
		SHAPE ABUTMENT ;
		PORT
			 LAYER M2 ;
			RECT 0.0098 42.9867 0.0481 43.0243 ;
			 LAYER M3 ;
			RECT 0.0098 42.9239 0.0481 43.0243 ;
			 LAYER V2 ;
			RECT 0.0215 42.9988 0.0364 43.0114 ;
		END

		ANTENNAGATEAREA 0.00027817 ;
		ANTENNADIFFAREA 0.00194719 ;
		ANTENNAPARTIALMETALAREA 0.00195671 ;
	END TD[27]

	PIN TD[28]
		USE SIGNAL ;
		DIRECTION INPUT ;
		SHAPE ABUTMENT ;
		PORT
			 LAYER M2 ;
			RECT 0.0098 44.2667 0.0481 44.3043 ;
			 LAYER M3 ;
			RECT 0.0098 44.2039 0.0481 44.3043 ;
			 LAYER V2 ;
			RECT 0.0215 44.2788 0.0364 44.2914 ;
		END

		ANTENNAGATEAREA 0.00027817 ;
		ANTENNADIFFAREA 0.00194719 ;
		ANTENNAPARTIALMETALAREA 0.00195671 ;
	END TD[28]

	PIN TD[29]
		USE SIGNAL ;
		DIRECTION INPUT ;
		SHAPE ABUTMENT ;
		PORT
			 LAYER M2 ;
			RECT 0.0098 45.5467 0.0481 45.5843 ;
			 LAYER M3 ;
			RECT 0.0098 45.4839 0.0481 45.5843 ;
			 LAYER V2 ;
			RECT 0.0215 45.5588 0.0364 45.5714 ;
		END

		ANTENNAGATEAREA 0.00027817 ;
		ANTENNADIFFAREA 0.00194719 ;
		ANTENNAPARTIALMETALAREA 0.00195671 ;
	END TD[29]

	PIN TD[2]
		USE SIGNAL ;
		DIRECTION INPUT ;
		SHAPE ABUTMENT ;
		PORT
			 LAYER M2 ;
			RECT 0.0098 3.5263 0.0481 3.5639 ;
			 LAYER M3 ;
			RECT 0.0098 3.5263 0.0481 3.6267 ;
			 LAYER V2 ;
			RECT 0.0215 3.5392 0.0364 3.5518 ;
		END

		ANTENNAGATEAREA 0.00027817 ;
		ANTENNADIFFAREA 0.00194719 ;
		ANTENNAPARTIALMETALAREA 0.00195671 ;
	END TD[2]

	PIN TD[30]
		USE SIGNAL ;
		DIRECTION INPUT ;
		SHAPE ABUTMENT ;
		PORT
			 LAYER M2 ;
			RECT 0.0098 46.8267 0.0481 46.8643 ;
			 LAYER M3 ;
			RECT 0.0098 46.7639 0.0481 46.8643 ;
			 LAYER V2 ;
			RECT 0.0215 46.8388 0.0364 46.8514 ;
		END

		ANTENNAGATEAREA 0.00027817 ;
		ANTENNADIFFAREA 0.00194719 ;
		ANTENNAPARTIALMETALAREA 0.00195671 ;
	END TD[30]

	PIN TD[31]
		USE SIGNAL ;
		DIRECTION INPUT ;
		SHAPE ABUTMENT ;
		PORT
			 LAYER M2 ;
			RECT 0.0098 48.1067 0.0481 48.1443 ;
			 LAYER M3 ;
			RECT 0.0098 48.0439 0.0481 48.1443 ;
			 LAYER V2 ;
			RECT 0.0215 48.1188 0.0364 48.1314 ;
		END

		ANTENNAGATEAREA 0.00027817 ;
		ANTENNADIFFAREA 0.00194719 ;
		ANTENNAPARTIALMETALAREA 0.00195671 ;
	END TD[31]

	PIN TD[3]
		USE SIGNAL ;
		DIRECTION INPUT ;
		SHAPE ABUTMENT ;
		PORT
			 LAYER M2 ;
			RECT 0.0098 4.8063 0.0481 4.8439 ;
			 LAYER M3 ;
			RECT 0.0098 4.8063 0.0481 4.9067 ;
			 LAYER V2 ;
			RECT 0.0215 4.8192 0.0364 4.8318 ;
		END

		ANTENNAGATEAREA 0.00027817 ;
		ANTENNADIFFAREA 0.00194719 ;
		ANTENNAPARTIALMETALAREA 0.00195671 ;
	END TD[3]

	PIN TD[4]
		USE SIGNAL ;
		DIRECTION INPUT ;
		SHAPE ABUTMENT ;
		PORT
			 LAYER M2 ;
			RECT 0.0098 6.0863 0.0481 6.1239 ;
			 LAYER M3 ;
			RECT 0.0098 6.0863 0.0481 6.1867 ;
			 LAYER V2 ;
			RECT 0.0215 6.0992 0.0364 6.1118 ;
		END

		ANTENNAGATEAREA 0.00027817 ;
		ANTENNADIFFAREA 0.00194719 ;
		ANTENNAPARTIALMETALAREA 0.00195671 ;
	END TD[4]

	PIN TD[5]
		USE SIGNAL ;
		DIRECTION INPUT ;
		SHAPE ABUTMENT ;
		PORT
			 LAYER M2 ;
			RECT 0.0098 7.3663 0.0481 7.4039 ;
			 LAYER M3 ;
			RECT 0.0098 7.3663 0.0481 7.4667 ;
			 LAYER V2 ;
			RECT 0.0215 7.3792 0.0364 7.3918 ;
		END

		ANTENNAGATEAREA 0.00027817 ;
		ANTENNADIFFAREA 0.00194719 ;
		ANTENNAPARTIALMETALAREA 0.00195671 ;
	END TD[5]

	PIN TD[6]
		USE SIGNAL ;
		DIRECTION INPUT ;
		SHAPE ABUTMENT ;
		PORT
			 LAYER M2 ;
			RECT 0.0098 8.6463 0.0481 8.6839 ;
			 LAYER M3 ;
			RECT 0.0098 8.6463 0.0481 8.7467 ;
			 LAYER V2 ;
			RECT 0.0215 8.6592 0.0364 8.6718 ;
		END

		ANTENNAGATEAREA 0.00027817 ;
		ANTENNADIFFAREA 0.00194719 ;
		ANTENNAPARTIALMETALAREA 0.00195671 ;
	END TD[6]

	PIN TD[7]
		USE SIGNAL ;
		DIRECTION INPUT ;
		SHAPE ABUTMENT ;
		PORT
			 LAYER M2 ;
			RECT 0.0098 9.9263 0.0481 9.9639 ;
			 LAYER M3 ;
			RECT 0.0098 9.9263 0.0481 10.0267 ;
			 LAYER V2 ;
			RECT 0.0215 9.9392 0.0364 9.9518 ;
		END

		ANTENNAGATEAREA 0.00027817 ;
		ANTENNADIFFAREA 0.00194719 ;
		ANTENNAPARTIALMETALAREA 0.00195671 ;
	END TD[7]

	PIN TD[8]
		USE SIGNAL ;
		DIRECTION INPUT ;
		SHAPE ABUTMENT ;
		PORT
			 LAYER M2 ;
			RECT 0.0098 11.2063 0.0481 11.2439 ;
			 LAYER M3 ;
			RECT 0.0098 11.2063 0.0481 11.3067 ;
			 LAYER V2 ;
			RECT 0.0215 11.2192 0.0364 11.2318 ;
		END

		ANTENNAGATEAREA 0.00027817 ;
		ANTENNADIFFAREA 0.00194719 ;
		ANTENNAPARTIALMETALAREA 0.00195671 ;
	END TD[8]

	PIN TD[9]
		USE SIGNAL ;
		DIRECTION INPUT ;
		SHAPE ABUTMENT ;
		PORT
			 LAYER M2 ;
			RECT 0.0098 12.4863 0.0481 12.5239 ;
			 LAYER M3 ;
			RECT 0.0098 12.4863 0.0481 12.5867 ;
			 LAYER V2 ;
			RECT 0.0215 12.4992 0.0364 12.5118 ;
		END

		ANTENNAGATEAREA 0.00027817 ;
		ANTENNADIFFAREA 0.00194719 ;
		ANTENNAPARTIALMETALAREA 0.00195671 ;
	END TD[9]

	PIN TEN
		USE SIGNAL ;
		DIRECTION INPUT ;
		SHAPE ABUTMENT ;
		PORT
			 LAYER M2 ;
			RECT 0.0098 22.2871 0.0481 22.3247 ;
			 LAYER M3 ;
			RECT 0.0098 22.2243 0.0481 22.3247 ;
			 LAYER V2 ;
			RECT 0.0215 22.2992 0.0364 22.3118 ;
		END

		ANTENNAGATEAREA 0.00027817 ;
		ANTENNADIFFAREA 0.00194719 ;
		ANTENNAPARTIALMETALAREA 0.00195671 ;
	END TEN

	PIN TGWEN
		USE SIGNAL ;
		DIRECTION INPUT ;
		SHAPE ABUTMENT ;
		PORT
			 LAYER M2 ;
			RECT 0.0714 23.429 0.1097 23.4667 ;
			 LAYER M3 ;
			RECT 0.0714 23.429 0.1097 23.5294 ;
			 LAYER V2 ;
			RECT 0.0831 23.4412 0.098 23.4537 ;
		END

		ANTENNAGATEAREA 0.00027817 ;
		ANTENNADIFFAREA 0.00194719 ;
		ANTENNAPARTIALMETALAREA 0.00195671 ;
	END TGWEN

	PIN TWEN[0]
		USE SIGNAL ;
		DIRECTION INPUT ;
		SHAPE ABUTMENT ;
		PORT
			 LAYER M2 ;
			RECT 0.0714 1.4306 0.1097 1.4682 ;
			 LAYER M3 ;
			RECT 0.0714 1.3678 0.1097 1.4682 ;
			 LAYER V2 ;
			RECT 0.0831 1.4435 0.098 1.4561 ;
		END

		ANTENNAGATEAREA 0.00027817 ;
		ANTENNADIFFAREA 0.00194719 ;
		ANTENNAPARTIALMETALAREA 0.00195671 ;
	END TWEN[0]

	PIN TWEN[10]
		USE SIGNAL ;
		DIRECTION INPUT ;
		SHAPE ABUTMENT ;
		PORT
			 LAYER M2 ;
			RECT 0.0714 14.2306 0.1097 14.2682 ;
			 LAYER M3 ;
			RECT 0.0714 14.1678 0.1097 14.2682 ;
			 LAYER V2 ;
			RECT 0.0831 14.2435 0.098 14.2561 ;
		END

		ANTENNAGATEAREA 0.00027817 ;
		ANTENNADIFFAREA 0.00194719 ;
		ANTENNAPARTIALMETALAREA 0.00195671 ;
	END TWEN[10]

	PIN TWEN[11]
		USE SIGNAL ;
		DIRECTION INPUT ;
		SHAPE ABUTMENT ;
		PORT
			 LAYER M2 ;
			RECT 0.0714 15.5106 0.1097 15.5482 ;
			 LAYER M3 ;
			RECT 0.0714 15.4478 0.1097 15.5482 ;
			 LAYER V2 ;
			RECT 0.0831 15.5235 0.098 15.5361 ;
		END

		ANTENNAGATEAREA 0.00027817 ;
		ANTENNADIFFAREA 0.00194719 ;
		ANTENNAPARTIALMETALAREA 0.00195671 ;
	END TWEN[11]

	PIN TWEN[12]
		USE SIGNAL ;
		DIRECTION INPUT ;
		SHAPE ABUTMENT ;
		PORT
			 LAYER M2 ;
			RECT 0.0714 16.7906 0.1097 16.8282 ;
			 LAYER M3 ;
			RECT 0.0714 16.7278 0.1097 16.8282 ;
			 LAYER V2 ;
			RECT 0.0831 16.8035 0.098 16.8161 ;
		END

		ANTENNAGATEAREA 0.00027817 ;
		ANTENNADIFFAREA 0.00194719 ;
		ANTENNAPARTIALMETALAREA 0.00195671 ;
	END TWEN[12]

	PIN TWEN[13]
		USE SIGNAL ;
		DIRECTION INPUT ;
		SHAPE ABUTMENT ;
		PORT
			 LAYER M2 ;
			RECT 0.0714 18.0706 0.1097 18.1082 ;
			 LAYER M3 ;
			RECT 0.0714 18.0078 0.1097 18.1082 ;
			 LAYER V2 ;
			RECT 0.0831 18.0835 0.098 18.0961 ;
		END

		ANTENNAGATEAREA 0.00027817 ;
		ANTENNADIFFAREA 0.00194719 ;
		ANTENNAPARTIALMETALAREA 0.00195671 ;
	END TWEN[13]

	PIN TWEN[14]
		USE SIGNAL ;
		DIRECTION INPUT ;
		SHAPE ABUTMENT ;
		PORT
			 LAYER M2 ;
			RECT 0.0714 19.3506 0.1097 19.3882 ;
			 LAYER M3 ;
			RECT 0.0714 19.2878 0.1097 19.3882 ;
			 LAYER V2 ;
			RECT 0.0831 19.3635 0.098 19.3761 ;
		END

		ANTENNAGATEAREA 0.00027817 ;
		ANTENNADIFFAREA 0.00194719 ;
		ANTENNAPARTIALMETALAREA 0.00195671 ;
	END TWEN[14]

	PIN TWEN[15]
		USE SIGNAL ;
		DIRECTION INPUT ;
		SHAPE ABUTMENT ;
		PORT
			 LAYER M2 ;
			RECT 0.0714 20.6306 0.1097 20.6682 ;
			 LAYER M3 ;
			RECT 0.0714 20.5678 0.1097 20.6682 ;
			 LAYER V2 ;
			RECT 0.0831 20.6435 0.098 20.6561 ;
		END

		ANTENNAGATEAREA 0.00027817 ;
		ANTENNADIFFAREA 0.00194719 ;
		ANTENNAPARTIALMETALAREA 0.00195671 ;
	END TWEN[15]

	PIN TWEN[16]
		USE SIGNAL ;
		DIRECTION INPUT ;
		SHAPE ABUTMENT ;
		PORT
			 LAYER M2 ;
			RECT 0.0714 28.4424 0.1097 28.48 ;
			 LAYER M3 ;
			RECT 0.0714 28.4424 0.1097 28.5427 ;
			 LAYER V2 ;
			RECT 0.0831 28.4545 0.098 28.4671 ;
		END

		ANTENNAGATEAREA 0.00027817 ;
		ANTENNADIFFAREA 0.00194719 ;
		ANTENNAPARTIALMETALAREA 0.00195671 ;
	END TWEN[16]

	PIN TWEN[17]
		USE SIGNAL ;
		DIRECTION INPUT ;
		SHAPE ABUTMENT ;
		PORT
			 LAYER M2 ;
			RECT 0.0714 29.7224 0.1097 29.76 ;
			 LAYER M3 ;
			RECT 0.0714 29.7224 0.1097 29.8227 ;
			 LAYER V2 ;
			RECT 0.0831 29.7345 0.098 29.7471 ;
		END

		ANTENNAGATEAREA 0.00027817 ;
		ANTENNADIFFAREA 0.00194719 ;
		ANTENNAPARTIALMETALAREA 0.00195671 ;
	END TWEN[17]

	PIN TWEN[18]
		USE SIGNAL ;
		DIRECTION INPUT ;
		SHAPE ABUTMENT ;
		PORT
			 LAYER M2 ;
			RECT 0.0714 31.0024 0.1097 31.04 ;
			 LAYER M3 ;
			RECT 0.0714 31.0024 0.1097 31.1027 ;
			 LAYER V2 ;
			RECT 0.0831 31.0145 0.098 31.0271 ;
		END

		ANTENNAGATEAREA 0.00027817 ;
		ANTENNADIFFAREA 0.00194719 ;
		ANTENNAPARTIALMETALAREA 0.00195671 ;
	END TWEN[18]

	PIN TWEN[19]
		USE SIGNAL ;
		DIRECTION INPUT ;
		SHAPE ABUTMENT ;
		PORT
			 LAYER M2 ;
			RECT 0.0714 32.2824 0.1097 32.32 ;
			 LAYER M3 ;
			RECT 0.0714 32.2824 0.1097 32.3827 ;
			 LAYER V2 ;
			RECT 0.0831 32.2945 0.098 32.3071 ;
		END

		ANTENNAGATEAREA 0.00027817 ;
		ANTENNADIFFAREA 0.00194719 ;
		ANTENNAPARTIALMETALAREA 0.00195671 ;
	END TWEN[19]

	PIN TWEN[1]
		USE SIGNAL ;
		DIRECTION INPUT ;
		SHAPE ABUTMENT ;
		PORT
			 LAYER M2 ;
			RECT 0.0714 2.7106 0.1097 2.7482 ;
			 LAYER M3 ;
			RECT 0.0714 2.6478 0.1097 2.7482 ;
			 LAYER V2 ;
			RECT 0.0831 2.7235 0.098 2.7361 ;
		END

		ANTENNAGATEAREA 0.00027817 ;
		ANTENNADIFFAREA 0.00194719 ;
		ANTENNAPARTIALMETALAREA 0.00195671 ;
	END TWEN[1]

	PIN TWEN[20]
		USE SIGNAL ;
		DIRECTION INPUT ;
		SHAPE ABUTMENT ;
		PORT
			 LAYER M2 ;
			RECT 0.0714 33.5624 0.1097 33.6 ;
			 LAYER M3 ;
			RECT 0.0714 33.5624 0.1097 33.6627 ;
			 LAYER V2 ;
			RECT 0.0831 33.5745 0.098 33.5871 ;
		END

		ANTENNAGATEAREA 0.00027817 ;
		ANTENNADIFFAREA 0.00194719 ;
		ANTENNAPARTIALMETALAREA 0.00195671 ;
	END TWEN[20]

	PIN TWEN[21]
		USE SIGNAL ;
		DIRECTION INPUT ;
		SHAPE ABUTMENT ;
		PORT
			 LAYER M2 ;
			RECT 0.0714 34.8424 0.1097 34.88 ;
			 LAYER M3 ;
			RECT 0.0714 34.8424 0.1097 34.9427 ;
			 LAYER V2 ;
			RECT 0.0831 34.8545 0.098 34.8671 ;
		END

		ANTENNAGATEAREA 0.00027817 ;
		ANTENNADIFFAREA 0.00194719 ;
		ANTENNAPARTIALMETALAREA 0.00195671 ;
	END TWEN[21]

	PIN TWEN[22]
		USE SIGNAL ;
		DIRECTION INPUT ;
		SHAPE ABUTMENT ;
		PORT
			 LAYER M2 ;
			RECT 0.0714 36.1224 0.1097 36.16 ;
			 LAYER M3 ;
			RECT 0.0714 36.1224 0.1097 36.2227 ;
			 LAYER V2 ;
			RECT 0.0831 36.1345 0.098 36.1471 ;
		END

		ANTENNAGATEAREA 0.00027817 ;
		ANTENNADIFFAREA 0.00194719 ;
		ANTENNAPARTIALMETALAREA 0.00195671 ;
	END TWEN[22]

	PIN TWEN[23]
		USE SIGNAL ;
		DIRECTION INPUT ;
		SHAPE ABUTMENT ;
		PORT
			 LAYER M2 ;
			RECT 0.0714 37.4024 0.1097 37.44 ;
			 LAYER M3 ;
			RECT 0.0714 37.4024 0.1097 37.5027 ;
			 LAYER V2 ;
			RECT 0.0831 37.4145 0.098 37.4271 ;
		END

		ANTENNAGATEAREA 0.00027817 ;
		ANTENNADIFFAREA 0.00194719 ;
		ANTENNAPARTIALMETALAREA 0.00195671 ;
	END TWEN[23]

	PIN TWEN[24]
		USE SIGNAL ;
		DIRECTION INPUT ;
		SHAPE ABUTMENT ;
		PORT
			 LAYER M2 ;
			RECT 0.0714 38.6824 0.1097 38.72 ;
			 LAYER M3 ;
			RECT 0.0714 38.6824 0.1097 38.7827 ;
			 LAYER V2 ;
			RECT 0.0831 38.6945 0.098 38.7071 ;
		END

		ANTENNAGATEAREA 0.00027817 ;
		ANTENNADIFFAREA 0.00194719 ;
		ANTENNAPARTIALMETALAREA 0.00195671 ;
	END TWEN[24]

	PIN TWEN[25]
		USE SIGNAL ;
		DIRECTION INPUT ;
		SHAPE ABUTMENT ;
		PORT
			 LAYER M2 ;
			RECT 0.0714 39.9624 0.1097 40 ;
			 LAYER M3 ;
			RECT 0.0714 39.9624 0.1097 40.0627 ;
			 LAYER V2 ;
			RECT 0.0831 39.9745 0.098 39.9871 ;
		END

		ANTENNAGATEAREA 0.00027817 ;
		ANTENNADIFFAREA 0.00194719 ;
		ANTENNAPARTIALMETALAREA 0.00195671 ;
	END TWEN[25]

	PIN TWEN[26]
		USE SIGNAL ;
		DIRECTION INPUT ;
		SHAPE ABUTMENT ;
		PORT
			 LAYER M2 ;
			RECT 0.0714 41.2424 0.1097 41.28 ;
			 LAYER M3 ;
			RECT 0.0714 41.2424 0.1097 41.3427 ;
			 LAYER V2 ;
			RECT 0.0831 41.2545 0.098 41.2671 ;
		END

		ANTENNAGATEAREA 0.00027817 ;
		ANTENNADIFFAREA 0.00194719 ;
		ANTENNAPARTIALMETALAREA 0.00195671 ;
	END TWEN[26]

	PIN TWEN[27]
		USE SIGNAL ;
		DIRECTION INPUT ;
		SHAPE ABUTMENT ;
		PORT
			 LAYER M2 ;
			RECT 0.0714 42.5224 0.1097 42.56 ;
			 LAYER M3 ;
			RECT 0.0714 42.5224 0.1097 42.6227 ;
			 LAYER V2 ;
			RECT 0.0831 42.5345 0.098 42.5471 ;
		END

		ANTENNAGATEAREA 0.00027817 ;
		ANTENNADIFFAREA 0.00194719 ;
		ANTENNAPARTIALMETALAREA 0.00195671 ;
	END TWEN[27]

	PIN TWEN[28]
		USE SIGNAL ;
		DIRECTION INPUT ;
		SHAPE ABUTMENT ;
		PORT
			 LAYER M2 ;
			RECT 0.0714 43.8024 0.1097 43.84 ;
			 LAYER M3 ;
			RECT 0.0714 43.8024 0.1097 43.9027 ;
			 LAYER V2 ;
			RECT 0.0831 43.8145 0.098 43.8271 ;
		END

		ANTENNAGATEAREA 0.00027817 ;
		ANTENNADIFFAREA 0.00194719 ;
		ANTENNAPARTIALMETALAREA 0.00195671 ;
	END TWEN[28]

	PIN TWEN[29]
		USE SIGNAL ;
		DIRECTION INPUT ;
		SHAPE ABUTMENT ;
		PORT
			 LAYER M2 ;
			RECT 0.0714 45.0824 0.1097 45.12 ;
			 LAYER M3 ;
			RECT 0.0714 45.0824 0.1097 45.1827 ;
			 LAYER V2 ;
			RECT 0.0831 45.0945 0.098 45.1071 ;
		END

		ANTENNAGATEAREA 0.00027817 ;
		ANTENNADIFFAREA 0.00194719 ;
		ANTENNAPARTIALMETALAREA 0.00195671 ;
	END TWEN[29]

	PIN TWEN[2]
		USE SIGNAL ;
		DIRECTION INPUT ;
		SHAPE ABUTMENT ;
		PORT
			 LAYER M2 ;
			RECT 0.0714 3.9906 0.1097 4.0282 ;
			 LAYER M3 ;
			RECT 0.0714 3.9278 0.1097 4.0282 ;
			 LAYER V2 ;
			RECT 0.0831 4.0035 0.098 4.0161 ;
		END

		ANTENNAGATEAREA 0.00027817 ;
		ANTENNADIFFAREA 0.00194719 ;
		ANTENNAPARTIALMETALAREA 0.00195671 ;
	END TWEN[2]

	PIN TWEN[30]
		USE SIGNAL ;
		DIRECTION INPUT ;
		SHAPE ABUTMENT ;
		PORT
			 LAYER M2 ;
			RECT 0.0714 46.3624 0.1097 46.4 ;
			 LAYER M3 ;
			RECT 0.0714 46.3624 0.1097 46.4627 ;
			 LAYER V2 ;
			RECT 0.0831 46.3745 0.098 46.3871 ;
		END

		ANTENNAGATEAREA 0.00027817 ;
		ANTENNADIFFAREA 0.00194719 ;
		ANTENNAPARTIALMETALAREA 0.00195671 ;
	END TWEN[30]

	PIN TWEN[31]
		USE SIGNAL ;
		DIRECTION INPUT ;
		SHAPE ABUTMENT ;
		PORT
			 LAYER M2 ;
			RECT 0.0714 47.6424 0.1097 47.68 ;
			 LAYER M3 ;
			RECT 0.0714 47.6424 0.1097 47.7427 ;
			 LAYER V2 ;
			RECT 0.0831 47.6545 0.098 47.6671 ;
		END

		ANTENNAGATEAREA 0.00027817 ;
		ANTENNADIFFAREA 0.00194719 ;
		ANTENNAPARTIALMETALAREA 0.00195671 ;
	END TWEN[31]

	PIN TWEN[3]
		USE SIGNAL ;
		DIRECTION INPUT ;
		SHAPE ABUTMENT ;
		PORT
			 LAYER M2 ;
			RECT 0.0714 5.2706 0.1097 5.3082 ;
			 LAYER M3 ;
			RECT 0.0714 5.2078 0.1097 5.3082 ;
			 LAYER V2 ;
			RECT 0.0831 5.2835 0.098 5.2961 ;
		END

		ANTENNAGATEAREA 0.00027817 ;
		ANTENNADIFFAREA 0.00194719 ;
		ANTENNAPARTIALMETALAREA 0.00195671 ;
	END TWEN[3]

	PIN TWEN[4]
		USE SIGNAL ;
		DIRECTION INPUT ;
		SHAPE ABUTMENT ;
		PORT
			 LAYER M2 ;
			RECT 0.0714 6.5506 0.1097 6.5882 ;
			 LAYER M3 ;
			RECT 0.0714 6.4878 0.1097 6.5882 ;
			 LAYER V2 ;
			RECT 0.0831 6.5635 0.098 6.5761 ;
		END

		ANTENNAGATEAREA 0.00027817 ;
		ANTENNADIFFAREA 0.00194719 ;
		ANTENNAPARTIALMETALAREA 0.00195671 ;
	END TWEN[4]

	PIN TWEN[5]
		USE SIGNAL ;
		DIRECTION INPUT ;
		SHAPE ABUTMENT ;
		PORT
			 LAYER M2 ;
			RECT 0.0714 7.8306 0.1097 7.8682 ;
			 LAYER M3 ;
			RECT 0.0714 7.7678 0.1097 7.8682 ;
			 LAYER V2 ;
			RECT 0.0831 7.8435 0.098 7.8561 ;
		END

		ANTENNAGATEAREA 0.00027817 ;
		ANTENNADIFFAREA 0.00194719 ;
		ANTENNAPARTIALMETALAREA 0.00195671 ;
	END TWEN[5]

	PIN TWEN[6]
		USE SIGNAL ;
		DIRECTION INPUT ;
		SHAPE ABUTMENT ;
		PORT
			 LAYER M2 ;
			RECT 0.0714 9.1106 0.1097 9.1482 ;
			 LAYER M3 ;
			RECT 0.0714 9.0478 0.1097 9.1482 ;
			 LAYER V2 ;
			RECT 0.0831 9.1235 0.098 9.1361 ;
		END

		ANTENNAGATEAREA 0.00027817 ;
		ANTENNADIFFAREA 0.00194719 ;
		ANTENNAPARTIALMETALAREA 0.00195671 ;
	END TWEN[6]

	PIN TWEN[7]
		USE SIGNAL ;
		DIRECTION INPUT ;
		SHAPE ABUTMENT ;
		PORT
			 LAYER M2 ;
			RECT 0.0714 10.3906 0.1097 10.4282 ;
			 LAYER M3 ;
			RECT 0.0714 10.3278 0.1097 10.4282 ;
			 LAYER V2 ;
			RECT 0.0831 10.4035 0.098 10.4161 ;
		END

		ANTENNAGATEAREA 0.00027817 ;
		ANTENNADIFFAREA 0.00194719 ;
		ANTENNAPARTIALMETALAREA 0.00195671 ;
	END TWEN[7]

	PIN TWEN[8]
		USE SIGNAL ;
		DIRECTION INPUT ;
		SHAPE ABUTMENT ;
		PORT
			 LAYER M2 ;
			RECT 0.0714 11.6706 0.1097 11.7082 ;
			 LAYER M3 ;
			RECT 0.0714 11.6078 0.1097 11.7082 ;
			 LAYER V2 ;
			RECT 0.0831 11.6835 0.098 11.6961 ;
		END

		ANTENNAGATEAREA 0.00027817 ;
		ANTENNADIFFAREA 0.00194719 ;
		ANTENNAPARTIALMETALAREA 0.00195671 ;
	END TWEN[8]

	PIN TWEN[9]
		USE SIGNAL ;
		DIRECTION INPUT ;
		SHAPE ABUTMENT ;
		PORT
			 LAYER M2 ;
			RECT 0.0714 12.9506 0.1097 12.9882 ;
			 LAYER M3 ;
			RECT 0.0714 12.8878 0.1097 12.9882 ;
			 LAYER V2 ;
			RECT 0.0831 12.9635 0.098 12.9761 ;
		END

		ANTENNAGATEAREA 0.00027817 ;
		ANTENNADIFFAREA 0.00194719 ;
		ANTENNAPARTIALMETALAREA 0.00195671 ;
	END TWEN[9]

	PIN VDDCE
		USE POWER ;
		DIRECTION INOUT ;
		PORT
			 LAYER M4 ;
			RECT 0.2105 48.269 21.693 48.3161 ;
		END

		PORT
			 LAYER M4 ;
			RECT 0.2105 46.989 21.693 47.0361 ;
		END

		PORT
			 LAYER M4 ;
			RECT 0.2105 20.6345 21.693 20.6816 ;
		END

		PORT
			 LAYER M4 ;
			RECT 0.2105 19.9945 21.693 20.0416 ;
		END

		PORT
			 LAYER M4 ;
			RECT 0.2105 46.349 21.693 46.3961 ;
		END

		PORT
			 LAYER M4 ;
			RECT 0.2105 19.3545 21.693 19.4016 ;
		END

		PORT
			 LAYER M4 ;
			RECT 0.2105 18.7145 21.693 18.7616 ;
		END

		PORT
			 LAYER M4 ;
			RECT 0.2105 18.0745 21.693 18.1216 ;
		END

		PORT
			 LAYER M4 ;
			RECT 0.2105 17.4345 21.693 17.4816 ;
		END

		PORT
			 LAYER M4 ;
			RECT 0.2105 16.7945 21.693 16.8416 ;
		END

		PORT
			 LAYER M4 ;
			RECT 0.2105 16.1545 21.693 16.2016 ;
		END

		PORT
			 LAYER M4 ;
			RECT 0.2105 15.5145 21.693 15.5616 ;
		END

		PORT
			 LAYER M4 ;
			RECT 0.2105 14.8745 21.693 14.9216 ;
		END

		PORT
			 LAYER M4 ;
			RECT 0.2105 14.2345 21.693 14.2816 ;
		END

		PORT
			 LAYER M4 ;
			RECT 0.2105 13.5945 21.693 13.6416 ;
		END

		PORT
			 LAYER M4 ;
			RECT 0.2105 45.709 21.693 45.7561 ;
		END

		PORT
			 LAYER M4 ;
			RECT 0.2105 12.9545 21.693 13.0016 ;
		END

		PORT
			 LAYER M4 ;
			RECT 0.2105 12.3145 21.693 12.3616 ;
		END

		PORT
			 LAYER M4 ;
			RECT 0.2105 11.6745 21.693 11.7216 ;
		END

		PORT
			 LAYER M4 ;
			RECT 0.2105 11.0345 21.693 11.0816 ;
		END

		PORT
			 LAYER M4 ;
			RECT 0.2105 10.3945 21.693 10.4416 ;
		END

		PORT
			 LAYER M4 ;
			RECT 0.2105 9.7545 21.693 9.8016 ;
		END

		PORT
			 LAYER M4 ;
			RECT 0.2105 9.1145 21.693 9.1616 ;
		END

		PORT
			 LAYER M4 ;
			RECT 0.2105 8.4745 21.693 8.5216 ;
		END

		PORT
			 LAYER M4 ;
			RECT 0.2105 7.8345 21.693 7.8816 ;
		END

		PORT
			 LAYER M4 ;
			RECT 0.2105 7.1945 21.693 7.2416 ;
		END

		PORT
			 LAYER M4 ;
			RECT 0.2105 45.069 21.693 45.1161 ;
		END

		PORT
			 LAYER M4 ;
			RECT 0.2105 6.5545 21.693 6.6016 ;
		END

		PORT
			 LAYER M4 ;
			RECT 0.2105 5.9145 21.693 5.9616 ;
		END

		PORT
			 LAYER M4 ;
			RECT 0.2105 5.2745 21.693 5.3216 ;
		END

		PORT
			 LAYER M4 ;
			RECT 0.2105 4.6345 21.693 4.6816 ;
		END

		PORT
			 LAYER M4 ;
			RECT 0.2105 3.9945 21.693 4.0416 ;
		END

		PORT
			 LAYER M4 ;
			RECT 0.2105 3.3545 21.693 3.4016 ;
		END

		PORT
			 LAYER M4 ;
			RECT 0.2105 2.7145 21.693 2.7616 ;
		END

		PORT
			 LAYER M4 ;
			RECT 0.2105 2.0745 21.693 2.1216 ;
		END

		PORT
			 LAYER M4 ;
			RECT 0.2105 1.4345 21.693 1.4816 ;
		END

		PORT
			 LAYER M4 ;
			RECT 0.2105 0.7945 21.693 0.8416 ;
		END

		PORT
			 LAYER M4 ;
			RECT 0.2105 44.429 21.693 44.4761 ;
		END

		PORT
			 LAYER M4 ;
			RECT 0.2105 43.789 21.693 43.8361 ;
		END

		PORT
			 LAYER M4 ;
			RECT 0.2105 43.149 21.693 43.1961 ;
		END

		PORT
			 LAYER M4 ;
			RECT 0.2105 42.509 21.693 42.5561 ;
		END

		PORT
			 LAYER M4 ;
			RECT 0.2105 41.869 21.693 41.9161 ;
		END

		PORT
			 LAYER M4 ;
			RECT 0.2105 41.229 21.693 41.2761 ;
		END

		PORT
			 LAYER M4 ;
			RECT 0.2105 40.589 21.693 40.6361 ;
		END

		PORT
			 LAYER M4 ;
			RECT 0.2105 39.949 21.693 39.9961 ;
		END

		PORT
			 LAYER M4 ;
			RECT 0.2105 39.309 21.693 39.3561 ;
		END

		PORT
			 LAYER M4 ;
			RECT 0.2105 38.669 21.693 38.7161 ;
		END

		PORT
			 LAYER M4 ;
			RECT 0.2105 38.029 21.693 38.0761 ;
		END

		PORT
			 LAYER M4 ;
			RECT 0.2105 37.389 21.693 37.4361 ;
		END

		PORT
			 LAYER M4 ;
			RECT 0.2105 36.749 21.693 36.7961 ;
		END

		PORT
			 LAYER M4 ;
			RECT 0.2105 36.109 21.693 36.1561 ;
		END

		PORT
			 LAYER M4 ;
			RECT 0.2105 35.469 21.693 35.5161 ;
		END

		PORT
			 LAYER M4 ;
			RECT 0.2105 34.829 21.693 34.8761 ;
		END

		PORT
			 LAYER M4 ;
			RECT 0.2105 34.189 21.693 34.2361 ;
		END

		PORT
			 LAYER M4 ;
			RECT 0.2105 33.549 21.693 33.5961 ;
		END

		PORT
			 LAYER M4 ;
			RECT 0.2105 32.909 21.693 32.9561 ;
		END

		PORT
			 LAYER M4 ;
			RECT 0.2105 47.629 21.693 47.6761 ;
		END

		PORT
			 LAYER M4 ;
			RECT 0.2105 32.269 21.693 32.3161 ;
		END

		PORT
			 LAYER M4 ;
			RECT 0.2105 31.629 21.693 31.6761 ;
		END

		PORT
			 LAYER M4 ;
			RECT 0.2105 30.989 21.693 31.0361 ;
		END

		PORT
			 LAYER M4 ;
			RECT 0.2105 30.349 21.693 30.3961 ;
		END

		PORT
			 LAYER M4 ;
			RECT 0.2105 29.709 21.693 29.7561 ;
		END

		PORT
			 LAYER M4 ;
			RECT 0.2105 29.069 21.693 29.1161 ;
		END

		PORT
			 LAYER M4 ;
			RECT 0.2105 28.429 21.693 28.4761 ;
		END

		PORT
			 LAYER M4 ;
			RECT 0.2105 49.0259 21.693 49.0573 ;
		END

		PORT
			 LAYER M4 ;
			RECT 0.2105 0.0533 21.693 0.0847 ;
		END

		PORT
			 LAYER M4 ;
			RECT 0.2105 21.3475 21.693 21.3945 ;
		END

		PORT
			 LAYER M4 ;
			RECT 0.2105 21.6392 21.693 21.6863 ;
		END

		PORT
			 LAYER M4 ;
			RECT 0.2105 27.5937 21.693 27.6408 ;
		END

		PORT
			 LAYER M4 ;
			RECT 0.2105 27.8855 21.693 27.9325 ;
		END

		PORT
			 LAYER M4 ;
			RECT 0.2105 20.7843 21.693 20.8157 ;
		END

		PORT
			 LAYER M4 ;
			RECT 0.2105 28.2984 21.693 28.3298 ;
		END

		PORT
			 LAYER M4 ;
			RECT 0.2105 48.9004 21.693 48.9318 ;
		END

		PORT
			 LAYER M4 ;
			RECT 0.2105 0.1788 21.693 0.2102 ;
		END

	END VDDCE

	PIN VDDPE
		USE POWER ;
		DIRECTION INOUT ;
		PORT
			 LAYER M4 ;
			RECT 0.2105 48.502 21.693 48.549 ;
		END

		PORT
			 LAYER M4 ;
			RECT 0.2105 47.222 21.693 47.269 ;
		END

		PORT
			 LAYER M4 ;
			RECT 0.2105 46.582 21.693 46.629 ;
		END

		PORT
			 LAYER M4 ;
			RECT 0.2105 20.4016 21.693 20.4486 ;
		END

		PORT
			 LAYER M4 ;
			RECT 0.2105 19.7616 21.693 19.8086 ;
		END

		PORT
			 LAYER M4 ;
			RECT 0.2105 19.1216 21.693 19.1686 ;
		END

		PORT
			 LAYER M4 ;
			RECT 0.2105 18.4816 21.693 18.5286 ;
		END

		PORT
			 LAYER M4 ;
			RECT 0.2105 17.8416 21.693 17.8886 ;
		END

		PORT
			 LAYER M4 ;
			RECT 0.2105 17.2016 21.693 17.2486 ;
		END

		PORT
			 LAYER M4 ;
			RECT 0.2105 16.5616 21.693 16.6086 ;
		END

		PORT
			 LAYER M4 ;
			RECT 0.2105 15.9216 21.693 15.9686 ;
		END

		PORT
			 LAYER M4 ;
			RECT 0.2105 15.2816 21.693 15.3286 ;
		END

		PORT
			 LAYER M4 ;
			RECT 0.2105 45.942 21.693 45.989 ;
		END

		PORT
			 LAYER M4 ;
			RECT 0.2105 14.6416 21.693 14.6886 ;
		END

		PORT
			 LAYER M4 ;
			RECT 0.2105 14.0016 21.693 14.0486 ;
		END

		PORT
			 LAYER M4 ;
			RECT 0.2105 13.3616 21.693 13.4086 ;
		END

		PORT
			 LAYER M4 ;
			RECT 0.2105 12.7216 21.693 12.7686 ;
		END

		PORT
			 LAYER M4 ;
			RECT 0.2105 12.0816 21.693 12.1286 ;
		END

		PORT
			 LAYER M4 ;
			RECT 0.2105 11.4416 21.693 11.4886 ;
		END

		PORT
			 LAYER M4 ;
			RECT 0.2105 10.8016 21.693 10.8486 ;
		END

		PORT
			 LAYER M4 ;
			RECT 0.2105 10.1616 21.693 10.2086 ;
		END

		PORT
			 LAYER M4 ;
			RECT 0.2105 9.5216 21.693 9.5686 ;
		END

		PORT
			 LAYER M4 ;
			RECT 0.2105 8.8816 21.693 8.9286 ;
		END

		PORT
			 LAYER M4 ;
			RECT 0.2105 45.302 21.693 45.349 ;
		END

		PORT
			 LAYER M4 ;
			RECT 0.2105 8.2416 21.693 8.2886 ;
		END

		PORT
			 LAYER M4 ;
			RECT 0.2105 7.6016 21.693 7.6486 ;
		END

		PORT
			 LAYER M4 ;
			RECT 0.2105 6.9616 21.693 7.0086 ;
		END

		PORT
			 LAYER M4 ;
			RECT 0.2105 6.3216 21.693 6.3686 ;
		END

		PORT
			 LAYER M4 ;
			RECT 0.2105 5.6816 21.693 5.7286 ;
		END

		PORT
			 LAYER M4 ;
			RECT 0.2105 5.0416 21.693 5.0886 ;
		END

		PORT
			 LAYER M4 ;
			RECT 0.2105 4.4016 21.693 4.4486 ;
		END

		PORT
			 LAYER M4 ;
			RECT 0.2105 3.7616 21.693 3.8086 ;
		END

		PORT
			 LAYER M4 ;
			RECT 0.2105 3.1216 21.693 3.1686 ;
		END

		PORT
			 LAYER M4 ;
			RECT 0.2105 2.4816 21.693 2.5286 ;
		END

		PORT
			 LAYER M4 ;
			RECT 0.2105 44.662 21.693 44.709 ;
		END

		PORT
			 LAYER M4 ;
			RECT 0.2105 1.8416 21.693 1.8886 ;
		END

		PORT
			 LAYER M4 ;
			RECT 0.2105 1.2016 21.693 1.2486 ;
		END

		PORT
			 LAYER M4 ;
			RECT 0.2105 0.5616 21.693 0.6086 ;
		END

		PORT
			 LAYER M4 ;
			RECT 0.2105 44.022 21.693 44.069 ;
		END

		PORT
			 LAYER M4 ;
			RECT 0.2105 43.382 21.693 43.429 ;
		END

		PORT
			 LAYER M4 ;
			RECT 0.2105 42.742 21.693 42.789 ;
		END

		PORT
			 LAYER M4 ;
			RECT 0.2105 42.102 21.693 42.149 ;
		END

		PORT
			 LAYER M4 ;
			RECT 0.2105 41.462 21.693 41.509 ;
		END

		PORT
			 LAYER M4 ;
			RECT 0.2105 40.822 21.693 40.869 ;
		END

		PORT
			 LAYER M4 ;
			RECT 0.2105 40.182 21.693 40.229 ;
		END

		PORT
			 LAYER M4 ;
			RECT 0.2105 39.542 21.693 39.589 ;
		END

		PORT
			 LAYER M4 ;
			RECT 0.2105 38.902 21.693 38.949 ;
		END

		PORT
			 LAYER M4 ;
			RECT 0.2105 38.262 21.693 38.309 ;
		END

		PORT
			 LAYER M4 ;
			RECT 0.2105 37.622 21.693 37.669 ;
		END

		PORT
			 LAYER M4 ;
			RECT 0.2105 36.982 21.693 37.029 ;
		END

		PORT
			 LAYER M4 ;
			RECT 0.2105 36.342 21.693 36.389 ;
		END

		PORT
			 LAYER M4 ;
			RECT 0.2105 35.702 21.693 35.749 ;
		END

		PORT
			 LAYER M4 ;
			RECT 0.2105 35.062 21.693 35.109 ;
		END

		PORT
			 LAYER M4 ;
			RECT 0.2105 47.862 21.693 47.909 ;
		END

		PORT
			 LAYER M4 ;
			RECT 0.2105 34.422 21.693 34.469 ;
		END

		PORT
			 LAYER M4 ;
			RECT 0.2105 33.782 21.693 33.829 ;
		END

		PORT
			 LAYER M4 ;
			RECT 0.2105 33.142 21.693 33.189 ;
		END

		PORT
			 LAYER M4 ;
			RECT 0.2105 32.502 21.693 32.549 ;
		END

		PORT
			 LAYER M4 ;
			RECT 0.2105 31.862 21.693 31.909 ;
		END

		PORT
			 LAYER M4 ;
			RECT 0.2105 31.222 21.693 31.269 ;
		END

		PORT
			 LAYER M4 ;
			RECT 0.2105 30.582 21.693 30.629 ;
		END

		PORT
			 LAYER M4 ;
			RECT 0.2105 29.942 21.693 29.989 ;
		END

		PORT
			 LAYER M4 ;
			RECT 0.2105 29.302 21.693 29.349 ;
		END

		PORT
			 LAYER M4 ;
			RECT 0.2105 28.662 21.693 28.709 ;
		END

		PORT
			 LAYER M4 ;
			RECT 0.2105 20.9882 21.693 21.0353 ;
		END

		PORT
			 LAYER M4 ;
			RECT 0.2105 21.4259 21.693 21.4729 ;
		END

		PORT
			 LAYER M4 ;
			RECT 0.2105 21.7176 21.693 21.7647 ;
		END

		PORT
			 LAYER M4 ;
			RECT 0.2105 22.2447 21.693 22.2918 ;
		END

		PORT
			 LAYER M4 ;
			RECT 0.2105 22.7718 21.693 22.8188 ;
		END

		PORT
			 LAYER M4 ;
			RECT 0.2105 23.2988 21.693 23.3459 ;
		END

		PORT
			 LAYER M4 ;
			RECT 0.2105 23.8259 21.693 23.8729 ;
		END

		PORT
			 LAYER M4 ;
			RECT 0.2105 24.88 21.693 24.9271 ;
		END

		PORT
			 LAYER M4 ;
			RECT 0.2105 25.9341 21.693 25.9812 ;
		END

		PORT
			 LAYER M4 ;
			RECT 0.2105 26.4612 21.693 26.5082 ;
		END

		PORT
			 LAYER M4 ;
			RECT 0.2105 26.9882 21.693 27.0353 ;
		END

		PORT
			 LAYER M4 ;
			RECT 0.2105 27.5153 21.693 27.5624 ;
		END

		PORT
			 LAYER M4 ;
			RECT 0.2105 27.8071 21.693 27.8541 ;
		END

		PORT
			 LAYER M4 ;
			RECT 0.2105 20.8471 21.693 20.8784 ;
		END

		PORT
			 LAYER M4 ;
			RECT 0.2105 28.2357 21.693 28.2671 ;
		END

	END VDDPE

	PIN VSSE
		USE GROUND ;
		DIRECTION INOUT ;
		PORT
			 LAYER M4 ;
			RECT 0.2105 20.7216 21.693 20.7529 ;
		END

		PORT
			 LAYER M4 ;
			RECT 0.2105 28.3612 21.693 28.3925 ;
		END

		PORT
			 LAYER M4 ;
			RECT 0.2105 48.9631 21.693 48.9945 ;
		END

		PORT
			 LAYER M4 ;
			RECT 0.2105 0.1161 21.693 0.1475 ;
		END

		PORT
			 LAYER M4 ;
			RECT 0.2105 27.6722 21.693 27.7192 ;
		END

		PORT
			 LAYER M4 ;
			RECT 0.2105 20.9098 21.693 20.9569 ;
		END

		PORT
			 LAYER M4 ;
			RECT 0.2105 21.5608 21.693 21.6078 ;
		END

		PORT
			 LAYER M4 ;
			RECT 0.2105 22.1663 21.693 22.2133 ;
		END

		PORT
			 LAYER M4 ;
			RECT 0.2105 22.6933 21.693 22.7404 ;
		END

		PORT
			 LAYER M4 ;
			RECT 0.2105 23.2204 21.693 23.2675 ;
		END

		PORT
			 LAYER M4 ;
			RECT 0.2105 23.7475 21.693 23.7945 ;
		END

		PORT
			 LAYER M4 ;
			RECT 0.2105 24.8016 21.693 24.8486 ;
		END

		PORT
			 LAYER M4 ;
			RECT 0.2105 25.8557 21.693 25.9027 ;
		END

		PORT
			 LAYER M4 ;
			RECT 0.2105 26.3827 21.693 26.4298 ;
		END

		PORT
			 LAYER M4 ;
			RECT 0.2105 26.9098 21.693 26.9569 ;
		END

		PORT
			 LAYER M4 ;
			RECT 0.2105 27.4369 21.693 27.4839 ;
		END

		PORT
			 LAYER M4 ;
			RECT 0.2105 48.8133 21.693 48.8604 ;
		END

		PORT
			 LAYER M4 ;
			RECT 0.2105 46.8933 21.693 46.9404 ;
		END

		PORT
			 LAYER M4 ;
			RECT 0.2105 20.0902 21.693 20.1373 ;
		END

		PORT
			 LAYER M4 ;
			RECT 0.2105 19.4502 21.693 19.4973 ;
		END

		PORT
			 LAYER M4 ;
			RECT 0.2105 18.8102 21.693 18.8573 ;
		END

		PORT
			 LAYER M4 ;
			RECT 0.2105 18.1702 21.693 18.2173 ;
		END

		PORT
			 LAYER M4 ;
			RECT 0.2105 17.5302 21.693 17.5773 ;
		END

		PORT
			 LAYER M4 ;
			RECT 0.2105 46.2533 21.693 46.3004 ;
		END

		PORT
			 LAYER M4 ;
			RECT 0.2105 16.8902 21.693 16.9373 ;
		END

		PORT
			 LAYER M4 ;
			RECT 0.2105 16.2502 21.693 16.2973 ;
		END

		PORT
			 LAYER M4 ;
			RECT 0.2105 15.6102 21.693 15.6573 ;
		END

		PORT
			 LAYER M4 ;
			RECT 0.2105 14.9702 21.693 15.0173 ;
		END

		PORT
			 LAYER M4 ;
			RECT 0.2105 14.3302 21.693 14.3773 ;
		END

		PORT
			 LAYER M4 ;
			RECT 0.2105 13.6902 21.693 13.7373 ;
		END

		PORT
			 LAYER M4 ;
			RECT 0.2105 13.0502 21.693 13.0973 ;
		END

		PORT
			 LAYER M4 ;
			RECT 0.2105 12.4102 21.693 12.4573 ;
		END

		PORT
			 LAYER M4 ;
			RECT 0.2105 11.7702 21.693 11.8173 ;
		END

		PORT
			 LAYER M4 ;
			RECT 0.2105 11.1302 21.693 11.1773 ;
		END

		PORT
			 LAYER M4 ;
			RECT 0.2105 45.6133 21.693 45.6604 ;
		END

		PORT
			 LAYER M4 ;
			RECT 0.2105 10.4902 21.693 10.5373 ;
		END

		PORT
			 LAYER M4 ;
			RECT 0.2105 9.8502 21.693 9.8973 ;
		END

		PORT
			 LAYER M4 ;
			RECT 0.2105 9.2102 21.693 9.2573 ;
		END

		PORT
			 LAYER M4 ;
			RECT 0.2105 8.5702 21.693 8.6173 ;
		END

		PORT
			 LAYER M4 ;
			RECT 0.2105 7.9302 21.693 7.9773 ;
		END

		PORT
			 LAYER M4 ;
			RECT 0.2105 7.2902 21.693 7.3373 ;
		END

		PORT
			 LAYER M4 ;
			RECT 0.2105 6.6502 21.693 6.6973 ;
		END

		PORT
			 LAYER M4 ;
			RECT 0.2105 6.0102 21.693 6.0573 ;
		END

		PORT
			 LAYER M4 ;
			RECT 0.2105 5.3702 21.693 5.4173 ;
		END

		PORT
			 LAYER M4 ;
			RECT 0.2105 4.7302 21.693 4.7773 ;
		END

		PORT
			 LAYER M4 ;
			RECT 0.2105 44.9733 21.693 45.0204 ;
		END

		PORT
			 LAYER M4 ;
			RECT 0.2105 4.0902 21.693 4.1373 ;
		END

		PORT
			 LAYER M4 ;
			RECT 0.2105 3.4502 21.693 3.4973 ;
		END

		PORT
			 LAYER M4 ;
			RECT 0.2105 2.8102 21.693 2.8573 ;
		END

		PORT
			 LAYER M4 ;
			RECT 0.2105 2.1702 21.693 2.2173 ;
		END

		PORT
			 LAYER M4 ;
			RECT 0.2105 1.5302 21.693 1.5773 ;
		END

		PORT
			 LAYER M4 ;
			RECT 0.2105 0.8902 21.693 0.9373 ;
		END

		PORT
			 LAYER M4 ;
			RECT 0.2105 0.2502 21.693 0.2973 ;
		END

		PORT
			 LAYER M4 ;
			RECT 0.2105 44.3333 21.693 44.3804 ;
		END

		PORT
			 LAYER M4 ;
			RECT 0.2105 43.6933 21.693 43.7404 ;
		END

		PORT
			 LAYER M4 ;
			RECT 0.2105 43.0533 21.693 43.1004 ;
		END

		PORT
			 LAYER M4 ;
			RECT 0.2105 42.4133 21.693 42.4604 ;
		END

		PORT
			 LAYER M4 ;
			RECT 0.2105 41.7733 21.693 41.8204 ;
		END

		PORT
			 LAYER M4 ;
			RECT 0.2105 41.1333 21.693 41.1804 ;
		END

		PORT
			 LAYER M4 ;
			RECT 0.2105 40.4933 21.693 40.5404 ;
		END

		PORT
			 LAYER M4 ;
			RECT 0.2105 39.8533 21.693 39.9004 ;
		END

		PORT
			 LAYER M4 ;
			RECT 0.2105 39.2133 21.693 39.2604 ;
		END

		PORT
			 LAYER M4 ;
			RECT 0.2105 38.5733 21.693 38.6204 ;
		END

		PORT
			 LAYER M4 ;
			RECT 0.2105 37.9333 21.693 37.9804 ;
		END

		PORT
			 LAYER M4 ;
			RECT 0.2105 37.2933 21.693 37.3404 ;
		END

		PORT
			 LAYER M4 ;
			RECT 0.2105 48.1733 21.693 48.2204 ;
		END

		PORT
			 LAYER M4 ;
			RECT 0.2105 36.6533 21.693 36.7004 ;
		END

		PORT
			 LAYER M4 ;
			RECT 0.2105 36.0133 21.693 36.0604 ;
		END

		PORT
			 LAYER M4 ;
			RECT 0.2105 35.3733 21.693 35.4204 ;
		END

		PORT
			 LAYER M4 ;
			RECT 0.2105 34.7333 21.693 34.7804 ;
		END

		PORT
			 LAYER M4 ;
			RECT 0.2105 34.0933 21.693 34.1404 ;
		END

		PORT
			 LAYER M4 ;
			RECT 0.2105 33.4533 21.693 33.5004 ;
		END

		PORT
			 LAYER M4 ;
			RECT 0.2105 32.8133 21.693 32.8604 ;
		END

		PORT
			 LAYER M4 ;
			RECT 0.2105 32.1733 21.693 32.2204 ;
		END

		PORT
			 LAYER M4 ;
			RECT 0.2105 31.5333 21.693 31.5804 ;
		END

		PORT
			 LAYER M4 ;
			RECT 0.2105 30.8933 21.693 30.9404 ;
		END

		PORT
			 LAYER M4 ;
			RECT 0.2105 47.5333 21.693 47.5804 ;
		END

		PORT
			 LAYER M4 ;
			RECT 0.2105 30.2533 21.693 30.3004 ;
		END

		PORT
			 LAYER M4 ;
			RECT 0.2105 29.6133 21.693 29.6604 ;
		END

		PORT
			 LAYER M4 ;
			RECT 0.2105 28.9733 21.693 29.0204 ;
		END

	END VSSE

	PIN WABL
		USE SIGNAL ;
		DIRECTION INPUT ;
		SHAPE ABUTMENT ;
		PORT
			 LAYER M2 ;
			RECT 0.0098 28.16 0.0481 28.1976 ;
			 LAYER M3 ;
			RECT 0.0098 28.0973 0.0481 28.1976 ;
			 LAYER V2 ;
			RECT 0.0215 28.1722 0.0364 28.1847 ;
		END

		ANTENNAGATEAREA 0.00027817 ;
		ANTENNADIFFAREA 0.00194719 ;
		ANTENNAPARTIALMETALAREA 0.00195671 ;
	END WABL

	PIN WABLM[0]
		USE SIGNAL ;
		DIRECTION INPUT ;
		SHAPE ABUTMENT ;
		PORT
			 LAYER M2 ;
			RECT 0.0714 21.0196 0.1097 21.0573 ;
			 LAYER M3 ;
			RECT 0.0714 21.0196 0.1097 21.12 ;
			 LAYER V2 ;
			RECT 0.0831 21.0318 0.098 21.0443 ;
		END

		ANTENNAGATEAREA 0.00027817 ;
		ANTENNADIFFAREA 0.00194719 ;
		ANTENNAPARTIALMETALAREA 0.00195671 ;
	END WABLM[0]

	PIN WABLM[1]
		USE SIGNAL ;
		DIRECTION INPUT ;
		SHAPE ABUTMENT ;
		PORT
			 LAYER M3 ;
			RECT 0.0714 25.5373 0.1097 25.6376 ;
		END

		ANTENNAGATEAREA 0.00027817 ;
		ANTENNADIFFAREA 0.00194719 ;
		ANTENNAPARTIALMETALAREA 0.00195671 ;
	END WABLM[1]

	PIN WENY[0]
		USE SIGNAL ;
		DIRECTION OUTPUT ;
		SHAPE ABUTMENT ;
		PORT
			 LAYER M2 ;
			RECT 0.0098 1.2424 0.0481 1.3427 ;
			 LAYER M3 ;
			RECT 0.0098 1.2424 0.0481 1.3427 ;
			 LAYER V2 ;
			RECT 0.021 1.2553 0.0359 1.2678 ;
		END

		ANTENNADIFFAREA 0.00194719 ;
		ANTENNAPARTIALMETALAREA 0.00195671 ;
	END WENY[0]

	PIN WENY[10]
		USE SIGNAL ;
		DIRECTION OUTPUT ;
		SHAPE ABUTMENT ;
		PORT
			 LAYER M2 ;
			RECT 0.0098 14.0424 0.0481 14.1427 ;
			 LAYER M3 ;
			RECT 0.0098 14.0424 0.0481 14.1427 ;
			 LAYER V2 ;
			RECT 0.021 14.0553 0.0359 14.0678 ;
		END

		ANTENNADIFFAREA 0.00194719 ;
		ANTENNAPARTIALMETALAREA 0.00195671 ;
	END WENY[10]

	PIN WENY[11]
		USE SIGNAL ;
		DIRECTION OUTPUT ;
		SHAPE ABUTMENT ;
		PORT
			 LAYER M2 ;
			RECT 0.0098 15.3224 0.0481 15.4227 ;
			 LAYER M3 ;
			RECT 0.0098 15.3224 0.0481 15.4227 ;
			 LAYER V2 ;
			RECT 0.021 15.3353 0.0359 15.3478 ;
		END

		ANTENNADIFFAREA 0.00194719 ;
		ANTENNAPARTIALMETALAREA 0.00195671 ;
	END WENY[11]

	PIN WENY[12]
		USE SIGNAL ;
		DIRECTION OUTPUT ;
		SHAPE ABUTMENT ;
		PORT
			 LAYER M2 ;
			RECT 0.0098 16.6024 0.0481 16.7027 ;
			 LAYER M3 ;
			RECT 0.0098 16.6024 0.0481 16.7027 ;
			 LAYER V2 ;
			RECT 0.021 16.6153 0.0359 16.6278 ;
		END

		ANTENNADIFFAREA 0.00194719 ;
		ANTENNAPARTIALMETALAREA 0.00195671 ;
	END WENY[12]

	PIN WENY[13]
		USE SIGNAL ;
		DIRECTION OUTPUT ;
		SHAPE ABUTMENT ;
		PORT
			 LAYER M2 ;
			RECT 0.0098 17.8824 0.0481 17.9827 ;
			 LAYER M3 ;
			RECT 0.0098 17.8824 0.0481 17.9827 ;
			 LAYER V2 ;
			RECT 0.021 17.8953 0.0359 17.9078 ;
		END

		ANTENNADIFFAREA 0.00194719 ;
		ANTENNAPARTIALMETALAREA 0.00195671 ;
	END WENY[13]

	PIN WENY[14]
		USE SIGNAL ;
		DIRECTION OUTPUT ;
		SHAPE ABUTMENT ;
		PORT
			 LAYER M2 ;
			RECT 0.0098 19.1624 0.0481 19.2627 ;
			 LAYER M3 ;
			RECT 0.0098 19.1624 0.0481 19.2627 ;
			 LAYER V2 ;
			RECT 0.021 19.1753 0.0359 19.1878 ;
		END

		ANTENNADIFFAREA 0.00194719 ;
		ANTENNAPARTIALMETALAREA 0.00195671 ;
	END WENY[14]

	PIN WENY[15]
		USE SIGNAL ;
		DIRECTION OUTPUT ;
		SHAPE ABUTMENT ;
		PORT
			 LAYER M2 ;
			RECT 0.0098 20.4424 0.0481 20.5427 ;
			 LAYER M3 ;
			RECT 0.0098 20.4424 0.0481 20.5427 ;
			 LAYER V2 ;
			RECT 0.021 20.4553 0.0359 20.4678 ;
		END

		ANTENNADIFFAREA 0.00194719 ;
		ANTENNAPARTIALMETALAREA 0.00195671 ;
	END WENY[15]

	PIN WENY[16]
		USE SIGNAL ;
		DIRECTION OUTPUT ;
		SHAPE ABUTMENT ;
		PORT
			 LAYER M2 ;
			RECT 0.0098 28.5678 0.0481 28.6682 ;
			 LAYER M3 ;
			RECT 0.0098 28.5678 0.0481 28.6682 ;
			 LAYER V2 ;
			RECT 0.021 28.6427 0.0359 28.6553 ;
		END

		ANTENNADIFFAREA 0.00194719 ;
		ANTENNAPARTIALMETALAREA 0.00195671 ;
	END WENY[16]

	PIN WENY[17]
		USE SIGNAL ;
		DIRECTION OUTPUT ;
		SHAPE ABUTMENT ;
		PORT
			 LAYER M2 ;
			RECT 0.0098 29.8478 0.0481 29.9482 ;
			 LAYER M3 ;
			RECT 0.0098 29.8478 0.0481 29.9482 ;
			 LAYER V2 ;
			RECT 0.021 29.9227 0.0359 29.9353 ;
		END

		ANTENNADIFFAREA 0.00194719 ;
		ANTENNAPARTIALMETALAREA 0.00195671 ;
	END WENY[17]

	PIN WENY[18]
		USE SIGNAL ;
		DIRECTION OUTPUT ;
		SHAPE ABUTMENT ;
		PORT
			 LAYER M2 ;
			RECT 0.0098 31.1278 0.0481 31.2282 ;
			 LAYER M3 ;
			RECT 0.0098 31.1278 0.0481 31.2282 ;
			 LAYER V2 ;
			RECT 0.021 31.2027 0.0359 31.2153 ;
		END

		ANTENNADIFFAREA 0.00194719 ;
		ANTENNAPARTIALMETALAREA 0.00195671 ;
	END WENY[18]

	PIN WENY[19]
		USE SIGNAL ;
		DIRECTION OUTPUT ;
		SHAPE ABUTMENT ;
		PORT
			 LAYER M2 ;
			RECT 0.0098 32.4078 0.0481 32.5082 ;
			 LAYER M3 ;
			RECT 0.0098 32.4078 0.0481 32.5082 ;
			 LAYER V2 ;
			RECT 0.021 32.4827 0.0359 32.4953 ;
		END

		ANTENNADIFFAREA 0.00194719 ;
		ANTENNAPARTIALMETALAREA 0.00195671 ;
	END WENY[19]

	PIN WENY[1]
		USE SIGNAL ;
		DIRECTION OUTPUT ;
		SHAPE ABUTMENT ;
		PORT
			 LAYER M2 ;
			RECT 0.0098 2.5224 0.0481 2.6227 ;
			 LAYER M3 ;
			RECT 0.0098 2.5224 0.0481 2.6227 ;
			 LAYER V2 ;
			RECT 0.021 2.5353 0.0359 2.5478 ;
		END

		ANTENNADIFFAREA 0.00194719 ;
		ANTENNAPARTIALMETALAREA 0.00195671 ;
	END WENY[1]

	PIN WENY[20]
		USE SIGNAL ;
		DIRECTION OUTPUT ;
		SHAPE ABUTMENT ;
		PORT
			 LAYER M2 ;
			RECT 0.0098 33.6878 0.0481 33.7882 ;
			 LAYER M3 ;
			RECT 0.0098 33.6878 0.0481 33.7882 ;
			 LAYER V2 ;
			RECT 0.021 33.7627 0.0359 33.7753 ;
		END

		ANTENNADIFFAREA 0.00194719 ;
		ANTENNAPARTIALMETALAREA 0.00195671 ;
	END WENY[20]

	PIN WENY[21]
		USE SIGNAL ;
		DIRECTION OUTPUT ;
		SHAPE ABUTMENT ;
		PORT
			 LAYER M2 ;
			RECT 0.0098 34.9678 0.0481 35.0682 ;
			 LAYER M3 ;
			RECT 0.0098 34.9678 0.0481 35.0682 ;
			 LAYER V2 ;
			RECT 0.021 35.0427 0.0359 35.0553 ;
		END

		ANTENNADIFFAREA 0.00194719 ;
		ANTENNAPARTIALMETALAREA 0.00195671 ;
	END WENY[21]

	PIN WENY[22]
		USE SIGNAL ;
		DIRECTION OUTPUT ;
		SHAPE ABUTMENT ;
		PORT
			 LAYER M2 ;
			RECT 0.0098 36.2478 0.0481 36.3482 ;
			 LAYER M3 ;
			RECT 0.0098 36.2478 0.0481 36.3482 ;
			 LAYER V2 ;
			RECT 0.021 36.3227 0.0359 36.3353 ;
		END

		ANTENNADIFFAREA 0.00194719 ;
		ANTENNAPARTIALMETALAREA 0.00195671 ;
	END WENY[22]

	PIN WENY[23]
		USE SIGNAL ;
		DIRECTION OUTPUT ;
		SHAPE ABUTMENT ;
		PORT
			 LAYER M2 ;
			RECT 0.0098 37.5278 0.0481 37.6282 ;
			 LAYER M3 ;
			RECT 0.0098 37.5278 0.0481 37.6282 ;
			 LAYER V2 ;
			RECT 0.021 37.6027 0.0359 37.6153 ;
		END

		ANTENNADIFFAREA 0.00194719 ;
		ANTENNAPARTIALMETALAREA 0.00195671 ;
	END WENY[23]

	PIN WENY[24]
		USE SIGNAL ;
		DIRECTION OUTPUT ;
		SHAPE ABUTMENT ;
		PORT
			 LAYER M2 ;
			RECT 0.0098 38.8078 0.0481 38.9082 ;
			 LAYER M3 ;
			RECT 0.0098 38.8078 0.0481 38.9082 ;
			 LAYER V2 ;
			RECT 0.021 38.8827 0.0359 38.8953 ;
		END

		ANTENNADIFFAREA 0.00194719 ;
		ANTENNAPARTIALMETALAREA 0.00195671 ;
	END WENY[24]

	PIN WENY[25]
		USE SIGNAL ;
		DIRECTION OUTPUT ;
		SHAPE ABUTMENT ;
		PORT
			 LAYER M2 ;
			RECT 0.0098 40.0878 0.0481 40.1882 ;
			 LAYER M3 ;
			RECT 0.0098 40.0878 0.0481 40.1882 ;
			 LAYER V2 ;
			RECT 0.021 40.1627 0.0359 40.1753 ;
		END

		ANTENNADIFFAREA 0.00194719 ;
		ANTENNAPARTIALMETALAREA 0.00195671 ;
	END WENY[25]

	PIN WENY[26]
		USE SIGNAL ;
		DIRECTION OUTPUT ;
		SHAPE ABUTMENT ;
		PORT
			 LAYER M2 ;
			RECT 0.0098 41.3678 0.0481 41.4682 ;
			 LAYER M3 ;
			RECT 0.0098 41.3678 0.0481 41.4682 ;
			 LAYER V2 ;
			RECT 0.021 41.4427 0.0359 41.4553 ;
		END

		ANTENNADIFFAREA 0.00194719 ;
		ANTENNAPARTIALMETALAREA 0.00195671 ;
	END WENY[26]

	PIN WENY[27]
		USE SIGNAL ;
		DIRECTION OUTPUT ;
		SHAPE ABUTMENT ;
		PORT
			 LAYER M2 ;
			RECT 0.0098 42.6478 0.0481 42.7482 ;
			 LAYER M3 ;
			RECT 0.0098 42.6478 0.0481 42.7482 ;
			 LAYER V2 ;
			RECT 0.021 42.7227 0.0359 42.7353 ;
		END

		ANTENNADIFFAREA 0.00194719 ;
		ANTENNAPARTIALMETALAREA 0.00195671 ;
	END WENY[27]

	PIN WENY[28]
		USE SIGNAL ;
		DIRECTION OUTPUT ;
		SHAPE ABUTMENT ;
		PORT
			 LAYER M2 ;
			RECT 0.0098 43.9278 0.0481 44.0282 ;
			 LAYER M3 ;
			RECT 0.0098 43.9278 0.0481 44.0282 ;
			 LAYER V2 ;
			RECT 0.021 44.0027 0.0359 44.0153 ;
		END

		ANTENNADIFFAREA 0.00194719 ;
		ANTENNAPARTIALMETALAREA 0.00195671 ;
	END WENY[28]

	PIN WENY[29]
		USE SIGNAL ;
		DIRECTION OUTPUT ;
		SHAPE ABUTMENT ;
		PORT
			 LAYER M2 ;
			RECT 0.0098 45.2078 0.0481 45.3082 ;
			 LAYER M3 ;
			RECT 0.0098 45.2078 0.0481 45.3082 ;
			 LAYER V2 ;
			RECT 0.021 45.2827 0.0359 45.2953 ;
		END

		ANTENNADIFFAREA 0.00194719 ;
		ANTENNAPARTIALMETALAREA 0.00195671 ;
	END WENY[29]

	PIN WENY[2]
		USE SIGNAL ;
		DIRECTION OUTPUT ;
		SHAPE ABUTMENT ;
		PORT
			 LAYER M2 ;
			RECT 0.0098 3.8024 0.0481 3.9027 ;
			 LAYER M3 ;
			RECT 0.0098 3.8024 0.0481 3.9027 ;
			 LAYER V2 ;
			RECT 0.021 3.8153 0.0359 3.8278 ;
		END

		ANTENNADIFFAREA 0.00194719 ;
		ANTENNAPARTIALMETALAREA 0.00195671 ;
	END WENY[2]

	PIN WENY[30]
		USE SIGNAL ;
		DIRECTION OUTPUT ;
		SHAPE ABUTMENT ;
		PORT
			 LAYER M2 ;
			RECT 0.0098 46.4878 0.0481 46.5882 ;
			 LAYER M3 ;
			RECT 0.0098 46.4878 0.0481 46.5882 ;
			 LAYER V2 ;
			RECT 0.021 46.5627 0.0359 46.5753 ;
		END

		ANTENNADIFFAREA 0.00194719 ;
		ANTENNAPARTIALMETALAREA 0.00195671 ;
	END WENY[30]

	PIN WENY[31]
		USE SIGNAL ;
		DIRECTION OUTPUT ;
		SHAPE ABUTMENT ;
		PORT
			 LAYER M2 ;
			RECT 0.0098 47.7678 0.0481 47.8682 ;
			 LAYER M3 ;
			RECT 0.0098 47.7678 0.0481 47.8682 ;
			 LAYER V2 ;
			RECT 0.021 47.8427 0.0359 47.8553 ;
		END

		ANTENNADIFFAREA 0.00194719 ;
		ANTENNAPARTIALMETALAREA 0.00195671 ;
	END WENY[31]

	PIN WENY[3]
		USE SIGNAL ;
		DIRECTION OUTPUT ;
		SHAPE ABUTMENT ;
		PORT
			 LAYER M2 ;
			RECT 0.0098 5.0824 0.0481 5.1827 ;
			 LAYER M3 ;
			RECT 0.0098 5.0824 0.0481 5.1827 ;
			 LAYER V2 ;
			RECT 0.021 5.0953 0.0359 5.1078 ;
		END

		ANTENNADIFFAREA 0.00194719 ;
		ANTENNAPARTIALMETALAREA 0.00195671 ;
	END WENY[3]

	PIN WENY[4]
		USE SIGNAL ;
		DIRECTION OUTPUT ;
		SHAPE ABUTMENT ;
		PORT
			 LAYER M2 ;
			RECT 0.0098 6.3624 0.0481 6.4627 ;
			 LAYER M3 ;
			RECT 0.0098 6.3624 0.0481 6.4627 ;
			 LAYER V2 ;
			RECT 0.021 6.3753 0.0359 6.3878 ;
		END

		ANTENNADIFFAREA 0.00194719 ;
		ANTENNAPARTIALMETALAREA 0.00195671 ;
	END WENY[4]

	PIN WENY[5]
		USE SIGNAL ;
		DIRECTION OUTPUT ;
		SHAPE ABUTMENT ;
		PORT
			 LAYER M2 ;
			RECT 0.0098 7.6424 0.0481 7.7427 ;
			 LAYER M3 ;
			RECT 0.0098 7.6424 0.0481 7.7427 ;
			 LAYER V2 ;
			RECT 0.021 7.6553 0.0359 7.6678 ;
		END

		ANTENNADIFFAREA 0.00194719 ;
		ANTENNAPARTIALMETALAREA 0.00195671 ;
	END WENY[5]

	PIN WENY[6]
		USE SIGNAL ;
		DIRECTION OUTPUT ;
		SHAPE ABUTMENT ;
		PORT
			 LAYER M2 ;
			RECT 0.0098 8.9224 0.0481 9.0227 ;
			 LAYER M3 ;
			RECT 0.0098 8.9224 0.0481 9.0227 ;
			 LAYER V2 ;
			RECT 0.021 8.9353 0.0359 8.9478 ;
		END

		ANTENNADIFFAREA 0.00194719 ;
		ANTENNAPARTIALMETALAREA 0.00195671 ;
	END WENY[6]

	PIN WENY[7]
		USE SIGNAL ;
		DIRECTION OUTPUT ;
		SHAPE ABUTMENT ;
		PORT
			 LAYER M2 ;
			RECT 0.0098 10.2024 0.0481 10.3027 ;
			 LAYER M3 ;
			RECT 0.0098 10.2024 0.0481 10.3027 ;
			 LAYER V2 ;
			RECT 0.021 10.2153 0.0359 10.2278 ;
		END

		ANTENNADIFFAREA 0.00194719 ;
		ANTENNAPARTIALMETALAREA 0.00195671 ;
	END WENY[7]

	PIN WENY[8]
		USE SIGNAL ;
		DIRECTION OUTPUT ;
		SHAPE ABUTMENT ;
		PORT
			 LAYER M2 ;
			RECT 0.0098 11.4824 0.0481 11.5827 ;
			 LAYER M3 ;
			RECT 0.0098 11.4824 0.0481 11.5827 ;
			 LAYER V2 ;
			RECT 0.021 11.4953 0.0359 11.5078 ;
		END

		ANTENNADIFFAREA 0.00194719 ;
		ANTENNAPARTIALMETALAREA 0.00195671 ;
	END WENY[8]

	PIN WENY[9]
		USE SIGNAL ;
		DIRECTION OUTPUT ;
		SHAPE ABUTMENT ;
		PORT
			 LAYER M2 ;
			RECT 0.0098 12.7624 0.0481 12.8627 ;
			 LAYER M3 ;
			RECT 0.0098 12.7624 0.0481 12.8627 ;
			 LAYER V2 ;
			RECT 0.021 12.7753 0.0359 12.7878 ;
		END

		ANTENNADIFFAREA 0.00194719 ;
		ANTENNAPARTIALMETALAREA 0.00195671 ;
	END WENY[9]

	PIN WEN[0]
		USE SIGNAL ;
		DIRECTION INPUT ;
		SHAPE ABUTMENT ;
		PORT
			 LAYER M2 ;
			RECT 0.0714 1.029 0.1097 1.0667 ;
			 LAYER M3 ;
			RECT 0.0714 0.9663 0.1097 1.0667 ;
			 LAYER V2 ;
			RECT 0.0831 1.042 0.098 1.0545 ;
		END

		ANTENNAGATEAREA 0.00027817 ;
		ANTENNADIFFAREA 0.00194719 ;
		ANTENNAPARTIALMETALAREA 0.00195671 ;
	END WEN[0]

	PIN WEN[10]
		USE SIGNAL ;
		DIRECTION INPUT ;
		SHAPE ABUTMENT ;
		PORT
			 LAYER M2 ;
			RECT 0.0714 13.829 0.1097 13.8667 ;
			 LAYER M3 ;
			RECT 0.0714 13.7663 0.1097 13.8667 ;
			 LAYER V2 ;
			RECT 0.0831 13.842 0.098 13.8545 ;
		END

		ANTENNAGATEAREA 0.00027817 ;
		ANTENNADIFFAREA 0.00194719 ;
		ANTENNAPARTIALMETALAREA 0.00195671 ;
	END WEN[10]

	PIN WEN[11]
		USE SIGNAL ;
		DIRECTION INPUT ;
		SHAPE ABUTMENT ;
		PORT
			 LAYER M2 ;
			RECT 0.0714 15.109 0.1097 15.1467 ;
			 LAYER M3 ;
			RECT 0.0714 15.0463 0.1097 15.1467 ;
			 LAYER V2 ;
			RECT 0.0831 15.122 0.098 15.1345 ;
		END

		ANTENNAGATEAREA 0.00027817 ;
		ANTENNADIFFAREA 0.00194719 ;
		ANTENNAPARTIALMETALAREA 0.00195671 ;
	END WEN[11]

	PIN WEN[12]
		USE SIGNAL ;
		DIRECTION INPUT ;
		SHAPE ABUTMENT ;
		PORT
			 LAYER M2 ;
			RECT 0.0714 16.389 0.1097 16.4267 ;
			 LAYER M3 ;
			RECT 0.0714 16.3263 0.1097 16.4267 ;
			 LAYER V2 ;
			RECT 0.0831 16.402 0.098 16.4145 ;
		END

		ANTENNAGATEAREA 0.00027817 ;
		ANTENNADIFFAREA 0.00194719 ;
		ANTENNAPARTIALMETALAREA 0.00195671 ;
	END WEN[12]

	PIN WEN[13]
		USE SIGNAL ;
		DIRECTION INPUT ;
		SHAPE ABUTMENT ;
		PORT
			 LAYER M2 ;
			RECT 0.0714 17.669 0.1097 17.7067 ;
			 LAYER M3 ;
			RECT 0.0714 17.6063 0.1097 17.7067 ;
			 LAYER V2 ;
			RECT 0.0831 17.682 0.098 17.6945 ;
		END

		ANTENNAGATEAREA 0.00027817 ;
		ANTENNADIFFAREA 0.00194719 ;
		ANTENNAPARTIALMETALAREA 0.00195671 ;
	END WEN[13]

	PIN WEN[14]
		USE SIGNAL ;
		DIRECTION INPUT ;
		SHAPE ABUTMENT ;
		PORT
			 LAYER M2 ;
			RECT 0.0714 18.949 0.1097 18.9867 ;
			 LAYER M3 ;
			RECT 0.0714 18.8863 0.1097 18.9867 ;
			 LAYER V2 ;
			RECT 0.0831 18.962 0.098 18.9745 ;
		END

		ANTENNAGATEAREA 0.00027817 ;
		ANTENNADIFFAREA 0.00194719 ;
		ANTENNAPARTIALMETALAREA 0.00195671 ;
	END WEN[14]

	PIN WEN[15]
		USE SIGNAL ;
		DIRECTION INPUT ;
		SHAPE ABUTMENT ;
		PORT
			 LAYER M2 ;
			RECT 0.0714 20.229 0.1097 20.2667 ;
			 LAYER M3 ;
			RECT 0.0714 20.1663 0.1097 20.2667 ;
			 LAYER V2 ;
			RECT 0.0831 20.242 0.098 20.2545 ;
		END

		ANTENNAGATEAREA 0.00027817 ;
		ANTENNADIFFAREA 0.00194719 ;
		ANTENNAPARTIALMETALAREA 0.00195671 ;
	END WEN[15]

	PIN WEN[16]
		USE SIGNAL ;
		DIRECTION INPUT ;
		SHAPE ABUTMENT ;
		PORT
			 LAYER M2 ;
			RECT 0.0714 28.8439 0.1097 28.8816 ;
			 LAYER M3 ;
			RECT 0.0714 28.8439 0.1097 28.9443 ;
			 LAYER V2 ;
			RECT 0.0831 28.8561 0.098 28.8686 ;
		END

		ANTENNAGATEAREA 0.00027817 ;
		ANTENNADIFFAREA 0.00194719 ;
		ANTENNAPARTIALMETALAREA 0.00195671 ;
	END WEN[16]

	PIN WEN[17]
		USE SIGNAL ;
		DIRECTION INPUT ;
		SHAPE ABUTMENT ;
		PORT
			 LAYER M2 ;
			RECT 0.0714 30.1239 0.1097 30.1616 ;
			 LAYER M3 ;
			RECT 0.0714 30.1239 0.1097 30.2243 ;
			 LAYER V2 ;
			RECT 0.0831 30.1361 0.098 30.1486 ;
		END

		ANTENNAGATEAREA 0.00027817 ;
		ANTENNADIFFAREA 0.00194719 ;
		ANTENNAPARTIALMETALAREA 0.00195671 ;
	END WEN[17]

	PIN WEN[18]
		USE SIGNAL ;
		DIRECTION INPUT ;
		SHAPE ABUTMENT ;
		PORT
			 LAYER M2 ;
			RECT 0.0714 31.4039 0.1097 31.4416 ;
			 LAYER M3 ;
			RECT 0.0714 31.4039 0.1097 31.5043 ;
			 LAYER V2 ;
			RECT 0.0831 31.4161 0.098 31.4286 ;
		END

		ANTENNAGATEAREA 0.00027817 ;
		ANTENNADIFFAREA 0.00194719 ;
		ANTENNAPARTIALMETALAREA 0.00195671 ;
	END WEN[18]

	PIN WEN[19]
		USE SIGNAL ;
		DIRECTION INPUT ;
		SHAPE ABUTMENT ;
		PORT
			 LAYER M2 ;
			RECT 0.0714 32.6839 0.1097 32.7216 ;
			 LAYER M3 ;
			RECT 0.0714 32.6839 0.1097 32.7843 ;
			 LAYER V2 ;
			RECT 0.0831 32.6961 0.098 32.7086 ;
		END

		ANTENNAGATEAREA 0.00027817 ;
		ANTENNADIFFAREA 0.00194719 ;
		ANTENNAPARTIALMETALAREA 0.00195671 ;
	END WEN[19]

	PIN WEN[1]
		USE SIGNAL ;
		DIRECTION INPUT ;
		SHAPE ABUTMENT ;
		PORT
			 LAYER M2 ;
			RECT 0.0714 2.309 0.1097 2.3467 ;
			 LAYER M3 ;
			RECT 0.0714 2.2463 0.1097 2.3467 ;
			 LAYER V2 ;
			RECT 0.0831 2.322 0.098 2.3345 ;
		END

		ANTENNAGATEAREA 0.00027817 ;
		ANTENNADIFFAREA 0.00194719 ;
		ANTENNAPARTIALMETALAREA 0.00195671 ;
	END WEN[1]

	PIN WEN[20]
		USE SIGNAL ;
		DIRECTION INPUT ;
		SHAPE ABUTMENT ;
		PORT
			 LAYER M2 ;
			RECT 0.0714 33.9639 0.1097 34.0016 ;
			 LAYER M3 ;
			RECT 0.0714 33.9639 0.1097 34.0643 ;
			 LAYER V2 ;
			RECT 0.0831 33.9761 0.098 33.9886 ;
		END

		ANTENNAGATEAREA 0.00027817 ;
		ANTENNADIFFAREA 0.00194719 ;
		ANTENNAPARTIALMETALAREA 0.00195671 ;
	END WEN[20]

	PIN WEN[21]
		USE SIGNAL ;
		DIRECTION INPUT ;
		SHAPE ABUTMENT ;
		PORT
			 LAYER M2 ;
			RECT 0.0714 35.2439 0.1097 35.2816 ;
			 LAYER M3 ;
			RECT 0.0714 35.2439 0.1097 35.3443 ;
			 LAYER V2 ;
			RECT 0.0831 35.2561 0.098 35.2686 ;
		END

		ANTENNAGATEAREA 0.00027817 ;
		ANTENNADIFFAREA 0.00194719 ;
		ANTENNAPARTIALMETALAREA 0.00195671 ;
	END WEN[21]

	PIN WEN[22]
		USE SIGNAL ;
		DIRECTION INPUT ;
		SHAPE ABUTMENT ;
		PORT
			 LAYER M2 ;
			RECT 0.0714 36.5239 0.1097 36.5616 ;
			 LAYER M3 ;
			RECT 0.0714 36.5239 0.1097 36.6243 ;
			 LAYER V2 ;
			RECT 0.0831 36.5361 0.098 36.5486 ;
		END

		ANTENNAGATEAREA 0.00027817 ;
		ANTENNADIFFAREA 0.00194719 ;
		ANTENNAPARTIALMETALAREA 0.00195671 ;
	END WEN[22]

	PIN WEN[23]
		USE SIGNAL ;
		DIRECTION INPUT ;
		SHAPE ABUTMENT ;
		PORT
			 LAYER M2 ;
			RECT 0.0714 37.8039 0.1097 37.8416 ;
			 LAYER M3 ;
			RECT 0.0714 37.8039 0.1097 37.9043 ;
			 LAYER V2 ;
			RECT 0.0831 37.8161 0.098 37.8286 ;
		END

		ANTENNAGATEAREA 0.00027817 ;
		ANTENNADIFFAREA 0.00194719 ;
		ANTENNAPARTIALMETALAREA 0.00195671 ;
	END WEN[23]

	PIN WEN[24]
		USE SIGNAL ;
		DIRECTION INPUT ;
		SHAPE ABUTMENT ;
		PORT
			 LAYER M2 ;
			RECT 0.0714 39.0839 0.1097 39.1216 ;
			 LAYER M3 ;
			RECT 0.0714 39.0839 0.1097 39.1843 ;
			 LAYER V2 ;
			RECT 0.0831 39.0961 0.098 39.1086 ;
		END

		ANTENNAGATEAREA 0.00027817 ;
		ANTENNADIFFAREA 0.00194719 ;
		ANTENNAPARTIALMETALAREA 0.00195671 ;
	END WEN[24]

	PIN WEN[25]
		USE SIGNAL ;
		DIRECTION INPUT ;
		SHAPE ABUTMENT ;
		PORT
			 LAYER M2 ;
			RECT 0.0714 40.3639 0.1097 40.4016 ;
			 LAYER M3 ;
			RECT 0.0714 40.3639 0.1097 40.4643 ;
			 LAYER V2 ;
			RECT 0.0831 40.3761 0.098 40.3886 ;
		END

		ANTENNAGATEAREA 0.00027817 ;
		ANTENNADIFFAREA 0.00194719 ;
		ANTENNAPARTIALMETALAREA 0.00195671 ;
	END WEN[25]

	PIN WEN[26]
		USE SIGNAL ;
		DIRECTION INPUT ;
		SHAPE ABUTMENT ;
		PORT
			 LAYER M2 ;
			RECT 0.0714 41.6439 0.1097 41.6816 ;
			 LAYER M3 ;
			RECT 0.0714 41.6439 0.1097 41.7443 ;
			 LAYER V2 ;
			RECT 0.0831 41.6561 0.098 41.6686 ;
		END

		ANTENNAGATEAREA 0.00027817 ;
		ANTENNADIFFAREA 0.00194719 ;
		ANTENNAPARTIALMETALAREA 0.00195671 ;
	END WEN[26]

	PIN WEN[27]
		USE SIGNAL ;
		DIRECTION INPUT ;
		SHAPE ABUTMENT ;
		PORT
			 LAYER M2 ;
			RECT 0.0714 42.9239 0.1097 42.9616 ;
			 LAYER M3 ;
			RECT 0.0714 42.9239 0.1097 43.0243 ;
			 LAYER V2 ;
			RECT 0.0831 42.9361 0.098 42.9486 ;
		END

		ANTENNAGATEAREA 0.00027817 ;
		ANTENNADIFFAREA 0.00194719 ;
		ANTENNAPARTIALMETALAREA 0.00195671 ;
	END WEN[27]

	PIN WEN[28]
		USE SIGNAL ;
		DIRECTION INPUT ;
		SHAPE ABUTMENT ;
		PORT
			 LAYER M2 ;
			RECT 0.0714 44.2039 0.1097 44.2416 ;
			 LAYER M3 ;
			RECT 0.0714 44.2039 0.1097 44.3043 ;
			 LAYER V2 ;
			RECT 0.0831 44.2161 0.098 44.2286 ;
		END

		ANTENNAGATEAREA 0.00027817 ;
		ANTENNADIFFAREA 0.00194719 ;
		ANTENNAPARTIALMETALAREA 0.00195671 ;
	END WEN[28]

	PIN WEN[29]
		USE SIGNAL ;
		DIRECTION INPUT ;
		SHAPE ABUTMENT ;
		PORT
			 LAYER M2 ;
			RECT 0.0714 45.4839 0.1097 45.5216 ;
			 LAYER M3 ;
			RECT 0.0714 45.4839 0.1097 45.5843 ;
			 LAYER V2 ;
			RECT 0.0831 45.4961 0.098 45.5086 ;
		END

		ANTENNAGATEAREA 0.00027817 ;
		ANTENNADIFFAREA 0.00194719 ;
		ANTENNAPARTIALMETALAREA 0.00195671 ;
	END WEN[29]

	PIN WEN[2]
		USE SIGNAL ;
		DIRECTION INPUT ;
		SHAPE ABUTMENT ;
		PORT
			 LAYER M2 ;
			RECT 0.0714 3.589 0.1097 3.6267 ;
			 LAYER M3 ;
			RECT 0.0714 3.5263 0.1097 3.6267 ;
			 LAYER V2 ;
			RECT 0.0831 3.602 0.098 3.6145 ;
		END

		ANTENNAGATEAREA 0.00027817 ;
		ANTENNADIFFAREA 0.00194719 ;
		ANTENNAPARTIALMETALAREA 0.00195671 ;
	END WEN[2]

	PIN WEN[30]
		USE SIGNAL ;
		DIRECTION INPUT ;
		SHAPE ABUTMENT ;
		PORT
			 LAYER M2 ;
			RECT 0.0714 46.7639 0.1097 46.8016 ;
			 LAYER M3 ;
			RECT 0.0714 46.7639 0.1097 46.8643 ;
			 LAYER V2 ;
			RECT 0.0831 46.7761 0.098 46.7886 ;
		END

		ANTENNAGATEAREA 0.00027817 ;
		ANTENNADIFFAREA 0.00194719 ;
		ANTENNAPARTIALMETALAREA 0.00195671 ;
	END WEN[30]

	PIN WEN[31]
		USE SIGNAL ;
		DIRECTION INPUT ;
		SHAPE ABUTMENT ;
		PORT
			 LAYER M2 ;
			RECT 0.0714 48.0439 0.1097 48.0816 ;
			 LAYER M3 ;
			RECT 0.0714 48.0439 0.1097 48.1443 ;
			 LAYER V2 ;
			RECT 0.0831 48.0561 0.098 48.0686 ;
		END

		ANTENNAGATEAREA 0.00027817 ;
		ANTENNADIFFAREA 0.00194719 ;
		ANTENNAPARTIALMETALAREA 0.00195671 ;
	END WEN[31]

	PIN WEN[3]
		USE SIGNAL ;
		DIRECTION INPUT ;
		SHAPE ABUTMENT ;
		PORT
			 LAYER M2 ;
			RECT 0.0714 4.869 0.1097 4.9067 ;
			 LAYER M3 ;
			RECT 0.0714 4.8063 0.1097 4.9067 ;
			 LAYER V2 ;
			RECT 0.0831 4.882 0.098 4.8945 ;
		END

		ANTENNAGATEAREA 0.00027817 ;
		ANTENNADIFFAREA 0.00194719 ;
		ANTENNAPARTIALMETALAREA 0.00195671 ;
	END WEN[3]

	PIN WEN[4]
		USE SIGNAL ;
		DIRECTION INPUT ;
		SHAPE ABUTMENT ;
		PORT
			 LAYER M2 ;
			RECT 0.0714 6.149 0.1097 6.1867 ;
			 LAYER M3 ;
			RECT 0.0714 6.0863 0.1097 6.1867 ;
			 LAYER V2 ;
			RECT 0.0831 6.162 0.098 6.1745 ;
		END

		ANTENNAGATEAREA 0.00027817 ;
		ANTENNADIFFAREA 0.00194719 ;
		ANTENNAPARTIALMETALAREA 0.00195671 ;
	END WEN[4]

	PIN WEN[5]
		USE SIGNAL ;
		DIRECTION INPUT ;
		SHAPE ABUTMENT ;
		PORT
			 LAYER M2 ;
			RECT 0.0714 7.429 0.1097 7.4667 ;
			 LAYER M3 ;
			RECT 0.0714 7.3663 0.1097 7.4667 ;
			 LAYER V2 ;
			RECT 0.0831 7.442 0.098 7.4545 ;
		END

		ANTENNAGATEAREA 0.00027817 ;
		ANTENNADIFFAREA 0.00194719 ;
		ANTENNAPARTIALMETALAREA 0.00195671 ;
	END WEN[5]

	PIN WEN[6]
		USE SIGNAL ;
		DIRECTION INPUT ;
		SHAPE ABUTMENT ;
		PORT
			 LAYER M2 ;
			RECT 0.0714 8.709 0.1097 8.7467 ;
			 LAYER M3 ;
			RECT 0.0714 8.6463 0.1097 8.7467 ;
			 LAYER V2 ;
			RECT 0.0831 8.722 0.098 8.7345 ;
		END

		ANTENNAGATEAREA 0.00027817 ;
		ANTENNADIFFAREA 0.00194719 ;
		ANTENNAPARTIALMETALAREA 0.00195671 ;
	END WEN[6]

	PIN WEN[7]
		USE SIGNAL ;
		DIRECTION INPUT ;
		SHAPE ABUTMENT ;
		PORT
			 LAYER M2 ;
			RECT 0.0714 9.989 0.1097 10.0267 ;
			 LAYER M3 ;
			RECT 0.0714 9.9263 0.1097 10.0267 ;
			 LAYER V2 ;
			RECT 0.0831 10.002 0.098 10.0145 ;
		END

		ANTENNAGATEAREA 0.00027817 ;
		ANTENNADIFFAREA 0.00194719 ;
		ANTENNAPARTIALMETALAREA 0.00195671 ;
	END WEN[7]

	PIN WEN[8]
		USE SIGNAL ;
		DIRECTION INPUT ;
		SHAPE ABUTMENT ;
		PORT
			 LAYER M2 ;
			RECT 0.0714 11.269 0.1097 11.3067 ;
			 LAYER M3 ;
			RECT 0.0714 11.2063 0.1097 11.3067 ;
			 LAYER V2 ;
			RECT 0.0831 11.282 0.098 11.2945 ;
		END

		ANTENNAGATEAREA 0.00027817 ;
		ANTENNADIFFAREA 0.00194719 ;
		ANTENNAPARTIALMETALAREA 0.00195671 ;
	END WEN[8]

	PIN WEN[9]
		USE SIGNAL ;
		DIRECTION INPUT ;
		SHAPE ABUTMENT ;
		PORT
			 LAYER M2 ;
			RECT 0.0714 12.549 0.1097 12.5867 ;
			 LAYER M3 ;
			RECT 0.0714 12.4863 0.1097 12.5867 ;
			 LAYER V2 ;
			RECT 0.0831 12.562 0.098 12.5745 ;
		END

		ANTENNAGATEAREA 0.00027817 ;
		ANTENNADIFFAREA 0.00194719 ;
		ANTENNAPARTIALMETALAREA 0.00195671 ;
	END WEN[9]

	OBS
		 LAYER M1 SPACING 0.012 ;
		RECT 0 0 21.693 49.1106 ;
		 LAYER M2 SPACING 0.012 ;
		RECT 0.133 0 21.693 49.1106 ;
		RECT 0 0 0.133 0.0439 ;
		RECT 0 0.182 0.133 0.9475 ;
		RECT 0.0714 1.0918 0.133 1.2235 ;
		RECT 0 1.211 0.133 1.2235 ;
		RECT 0.0714 1.2235 0.133 1.349 ;
		RECT 0 1.4871 0.133 2.2275 ;
		RECT 0.0714 2.3718 0.133 2.5035 ;
		RECT 0 2.491 0.133 2.5035 ;
		RECT 0.0714 2.5035 0.133 2.629 ;
		RECT 0 2.7671 0.133 3.5075 ;
		RECT 0.0714 3.6518 0.133 3.7835 ;
		RECT 0 3.771 0.133 3.7835 ;
		RECT 0.0714 3.7835 0.133 3.909 ;
		RECT 0 4.0471 0.133 4.7875 ;
		RECT 0.0714 4.9318 0.133 5.0635 ;
		RECT 0 5.051 0.133 5.0635 ;
		RECT 0.0714 5.0635 0.133 5.189 ;
		RECT 0 5.3271 0.133 6.0675 ;
		RECT 0.0714 6.2118 0.133 6.3435 ;
		RECT 0 6.331 0.133 6.3435 ;
		RECT 0.0714 6.3435 0.133 6.469 ;
		RECT 0 6.6071 0.133 7.3475 ;
		RECT 0.0714 7.4918 0.133 7.6235 ;
		RECT 0 7.611 0.133 7.6235 ;
		RECT 0.0714 7.6235 0.133 7.749 ;
		RECT 0 7.8871 0.133 8.6275 ;
		RECT 0.0714 8.7718 0.133 8.9035 ;
		RECT 0 8.891 0.133 8.9035 ;
		RECT 0.0714 8.9035 0.133 9.029 ;
		RECT 0 9.1671 0.133 9.9075 ;
		RECT 0.0714 10.0518 0.133 10.1835 ;
		RECT 0 10.171 0.133 10.1835 ;
		RECT 0.0714 10.1835 0.133 10.309 ;
		RECT 0 10.4471 0.133 11.1875 ;
		RECT 0.0714 11.3318 0.133 11.4635 ;
		RECT 0 11.451 0.133 11.4635 ;
		RECT 0.0714 11.4635 0.133 11.589 ;
		RECT 0 11.7271 0.133 12.4675 ;
		RECT 0.0714 12.6118 0.133 12.7435 ;
		RECT 0 12.731 0.133 12.7435 ;
		RECT 0.0714 12.7435 0.133 12.869 ;
		RECT 0 13.0071 0.133 13.7475 ;
		RECT 0.0714 13.8918 0.133 14.0235 ;
		RECT 0 14.011 0.133 14.0235 ;
		RECT 0.0714 14.0235 0.133 14.149 ;
		RECT 0 14.2871 0.133 15.0275 ;
		RECT 0.0714 15.1718 0.133 15.3035 ;
		RECT 0 15.291 0.133 15.3035 ;
		RECT 0.0714 15.3035 0.133 15.429 ;
		RECT 0 15.5671 0.133 16.3075 ;
		RECT 0.0714 16.4518 0.133 16.5835 ;
		RECT 0 16.571 0.133 16.5835 ;
		RECT 0.0714 16.5835 0.133 16.709 ;
		RECT 0 16.8471 0.133 17.5875 ;
		RECT 0.0714 17.7318 0.133 17.8635 ;
		RECT 0 17.851 0.133 17.8635 ;
		RECT 0.0714 17.8635 0.133 17.989 ;
		RECT 0 18.1271 0.133 18.8675 ;
		RECT 0.0714 19.0118 0.133 19.1435 ;
		RECT 0 19.131 0.133 19.1435 ;
		RECT 0.0714 19.1435 0.133 19.269 ;
		RECT 0 19.4071 0.133 20.1475 ;
		RECT 0.0714 20.2918 0.133 20.4235 ;
		RECT 0 20.411 0.133 20.4235 ;
		RECT 0.0714 20.4235 0.133 20.549 ;
		RECT 0 20.6871 0.133 21.0008 ;
		RECT 0 21.1388 0.133 21.1514 ;
		RECT 0 21.2894 0.133 21.6031 ;
		RECT 0 21.7412 0.133 21.7537 ;
		RECT 0 21.8918 0.133 21.9043 ;
		RECT 0 22.0424 0.133 22.2055 ;
		RECT 0 22.3435 0.133 22.5067 ;
		RECT 0 22.6447 0.133 22.6573 ;
		RECT 0 22.7953 0.133 22.9584 ;
		RECT 0 23.0965 0.133 23.109 ;
		RECT 0 23.2471 0.133 23.2596 ;
		RECT 0 23.3976 0.133 23.4102 ;
		RECT 0 23.5482 0.133 23.5608 ;
		RECT 0 23.6988 0.133 23.7114 ;
		RECT 0 23.8494 0.133 23.862 ;
		RECT 0 24 0.133 24.0125 ;
		RECT 0 24.1506 0.133 24.1631 ;
		RECT 0 24.3012 0.133 24.3137 ;
		RECT 0 24.4518 0.133 24.4643 ;
		RECT 0 24.6024 0.133 24.6149 ;
		RECT 0 24.7529 0.133 24.7655 ;
		RECT 0 24.9035 0.133 24.9161 ;
		RECT 0 25.0541 0.133 25.0667 ;
		RECT 0 25.2047 0.133 25.2173 ;
		RECT 0 25.3553 0.133 25.3678 ;
		RECT 0 25.5059 0.133 25.5184 ;
		RECT 0 25.6565 0.133 25.669 ;
		RECT 0 25.8071 0.133 25.8196 ;
		RECT 0 25.9576 0.133 25.9702 ;
		RECT 0 26.1082 0.133 26.2714 ;
		RECT 0 26.4094 0.133 26.422 ;
		RECT 0 26.56 0.133 26.5725 ;
		RECT 0 26.7106 0.133 26.7231 ;
		RECT 0 26.8612 0.133 26.8737 ;
		RECT 0 27.0118 0.133 27.3255 ;
		RECT 0 27.4635 0.133 27.4761 ;
		RECT 0 27.6141 0.133 28.0784 ;
		RECT 0 28.2165 0.133 28.4235 ;
		RECT 0.0714 28.5678 0.133 28.6996 ;
		RECT 0 28.6871 0.133 28.6996 ;
		RECT 0.0714 28.6996 0.133 28.8251 ;
		RECT 0 28.9631 0.133 29.7035 ;
		RECT 0.0714 29.8478 0.133 29.9796 ;
		RECT 0 29.9671 0.133 29.9796 ;
		RECT 0.0714 29.9796 0.133 30.1051 ;
		RECT 0 30.2431 0.133 30.9835 ;
		RECT 0.0714 31.1278 0.133 31.2596 ;
		RECT 0 31.2471 0.133 31.2596 ;
		RECT 0.0714 31.2596 0.133 31.3851 ;
		RECT 0 31.5231 0.133 32.2635 ;
		RECT 0.0714 32.4078 0.133 32.5396 ;
		RECT 0 32.5271 0.133 32.5396 ;
		RECT 0.0714 32.5396 0.133 32.6651 ;
		RECT 0 32.8031 0.133 33.5435 ;
		RECT 0.0714 33.6878 0.133 33.8196 ;
		RECT 0 33.8071 0.133 33.8196 ;
		RECT 0.0714 33.8196 0.133 33.9451 ;
		RECT 0 34.0831 0.133 34.8235 ;
		RECT 0.0714 34.9678 0.133 35.0996 ;
		RECT 0 35.0871 0.133 35.0996 ;
		RECT 0.0714 35.0996 0.133 35.2251 ;
		RECT 0 35.3631 0.133 36.1035 ;
		RECT 0.0714 36.2478 0.133 36.3796 ;
		RECT 0 36.3671 0.133 36.3796 ;
		RECT 0.0714 36.3796 0.133 36.5051 ;
		RECT 0 36.6431 0.133 37.3835 ;
		RECT 0.0714 37.5278 0.133 37.6596 ;
		RECT 0 37.6471 0.133 37.6596 ;
		RECT 0.0714 37.6596 0.133 37.7851 ;
		RECT 0 37.9231 0.133 38.6635 ;
		RECT 0.0714 38.8078 0.133 38.9396 ;
		RECT 0 38.9271 0.133 38.9396 ;
		RECT 0.0714 38.9396 0.133 39.0651 ;
		RECT 0 39.2031 0.133 39.9435 ;
		RECT 0.0714 40.0878 0.133 40.2196 ;
		RECT 0 40.2071 0.133 40.2196 ;
		RECT 0.0714 40.2196 0.133 40.3451 ;
		RECT 0 40.4831 0.133 41.2235 ;
		RECT 0.0714 41.3678 0.133 41.4996 ;
		RECT 0 41.4871 0.133 41.4996 ;
		RECT 0.0714 41.4996 0.133 41.6251 ;
		RECT 0 41.7631 0.133 42.5035 ;
		RECT 0.0714 42.6478 0.133 42.7796 ;
		RECT 0 42.7671 0.133 42.7796 ;
		RECT 0.0714 42.7796 0.133 42.9051 ;
		RECT 0 43.0431 0.133 43.7835 ;
		RECT 0.0714 43.9278 0.133 44.0596 ;
		RECT 0 44.0471 0.133 44.0596 ;
		RECT 0.0714 44.0596 0.133 44.1851 ;
		RECT 0 44.3231 0.133 45.0635 ;
		RECT 0.0714 45.2078 0.133 45.3396 ;
		RECT 0 45.3271 0.133 45.3396 ;
		RECT 0.0714 45.3396 0.133 45.4651 ;
		RECT 0 45.6031 0.133 46.3435 ;
		RECT 0.0714 46.4878 0.133 46.6196 ;
		RECT 0 46.6071 0.133 46.6196 ;
		RECT 0.0714 46.6196 0.133 46.7451 ;
		RECT 0 46.8831 0.133 47.6235 ;
		RECT 0.0714 47.7678 0.133 47.8996 ;
		RECT 0 47.8871 0.133 47.8996 ;
		RECT 0.0714 47.8996 0.133 48.0251 ;
		RECT 0 48.1631 0.133 48.9286 ;
		RECT 0 49.0667 0.133 49.1106 ;
		 LAYER M2 ;
		RECT 0.0714 23.5796 0.1097 23.68 ;
		RECT 0.0714 24.9349 0.1097 25.0353 ;
		RECT 0.0714 25.5373 0.1097 25.6376 ;
		RECT 0.0714 25.8384 0.1097 25.9388 ;
		RECT 0.0714 25.989 0.1097 26.0894 ;
		RECT 0.0714 26.5914 0.1097 26.6918 ;
		RECT 0.0714 20.7184 0.1097 20.7561 ;
		RECT 0.0098 20.7812 0.0481 20.8188 ;
		RECT 0.0098 21.8353 0.0481 21.8729 ;
		RECT 0.0714 22.0737 0.1097 22.1114 ;
		RECT 0.0098 22.1365 0.0481 22.1741 ;
		RECT 0.0714 22.2243 0.1097 22.262 ;
		RECT 0.0098 22.3749 0.0481 22.4753 ;
		RECT 0.0714 22.8267 0.1097 22.8643 ;
		RECT 0.0098 22.8894 0.0481 22.9271 ;
		RECT 0.0714 22.9773 0.1097 23.0149 ;
		RECT 0.0098 23.4918 0.0481 23.5294 ;
		RECT 0.0098 23.5796 0.0481 23.6173 ;
		RECT 0.0714 20.869 0.1097 20.9067 ;
		RECT 0.0714 23.7302 0.1097 23.7678 ;
		RECT 0.0714 23.8808 0.1097 23.9184 ;
		RECT 0.0714 24.6337 0.1097 24.6714 ;
		RECT 0.0098 24.8471 0.0481 24.8847 ;
		RECT 0.0098 24.9976 0.0481 25.0353 ;
		RECT 0.0714 25.0855 0.1097 25.1231 ;
		RECT 0.0714 25.3867 0.1097 25.4243 ;
		RECT 0.0098 25.6 0.0481 25.6376 ;
		RECT 0.0098 25.7506 0.0481 25.7882 ;
		RECT 0.0098 25.8384 0.0481 25.8761 ;
		RECT 0.0098 20.9318 0.0481 20.9694 ;
		RECT 0.0098 26.1396 0.0481 26.1773 ;
		RECT 0.0714 26.2024 0.1097 26.24 ;
		RECT 0.0098 26.6541 0.0481 26.6918 ;
		RECT 0.0714 27.0431 0.1097 27.0808 ;
		RECT 0.0098 27.1059 0.0481 27.1435 ;
		RECT 0.0098 27.1937 0.0481 27.2941 ;
		RECT 0.0098 27.4071 0.0481 27.4447 ;
		RECT 0.0098 27.5576 0.0481 27.5953 ;
		RECT 0.0714 27.6455 0.1097 27.6831 ;
		RECT 0.0098 27.7082 0.0481 27.7459 ;
		RECT 0.0098 21.0824 0.0481 21.12 ;
		RECT 0.0098 27.7961 0.0481 27.8965 ;
		RECT 0.0714 27.9467 0.1097 27.9843 ;
		RECT 0.0098 28.0094 0.0481 28.0471 ;
		RECT 0.0714 28.0973 0.1097 28.1349 ;
		RECT 0.0098 28.2478 0.0481 28.3482 ;
		RECT 0.0098 0.1255 0.0481 0.1631 ;
		RECT 0.0098 48.9475 0.0481 48.9851 ;
		RECT 0.0098 21.2329 0.0481 21.2706 ;
		RECT 0.0098 21.3208 0.0481 21.4212 ;
		RECT 0.0714 21.4714 0.1097 21.509 ;
		RECT 0.0098 21.5341 0.0481 21.5718 ;
		RECT 0.0714 21.622 0.1097 21.6596 ;
		 LAYER M2 SPACING 0.012 ;
		RECT 0.0714 23.5796 0.1097 23.68 ;
		RECT 0.0714 24.9349 0.1097 25.0353 ;
		RECT 0.0714 25.5373 0.1097 25.6376 ;
		RECT 0.0714 25.8384 0.1097 25.9388 ;
		RECT 0.0714 25.989 0.1097 26.0894 ;
		RECT 0.0714 26.5914 0.1097 26.6918 ;
		RECT 0.0714 20.7184 0.1097 20.7561 ;
		RECT 0.0098 20.7812 0.0481 20.8188 ;
		RECT 0.0098 21.8353 0.0481 21.8729 ;
		RECT 0.0714 22.0737 0.1097 22.1114 ;
		RECT 0.0098 22.1365 0.0481 22.1741 ;
		RECT 0.0714 22.2243 0.1097 22.262 ;
		RECT 0.0098 22.3749 0.0481 22.4753 ;
		RECT 0.0714 22.8267 0.1097 22.8643 ;
		RECT 0.0098 22.8894 0.0481 22.9271 ;
		RECT 0.0714 22.9773 0.1097 23.0149 ;
		RECT 0.0098 23.4918 0.0481 23.5294 ;
		RECT 0.0098 23.5796 0.0481 23.6173 ;
		RECT 0.0714 20.869 0.1097 20.9067 ;
		RECT 0.0714 23.7302 0.1097 23.7678 ;
		RECT 0.0714 23.8808 0.1097 23.9184 ;
		RECT 0.0714 24.6337 0.1097 24.6714 ;
		RECT 0.0098 24.8471 0.0481 24.8847 ;
		RECT 0.0098 24.9976 0.0481 25.0353 ;
		RECT 0.0714 25.0855 0.1097 25.1231 ;
		RECT 0.0714 25.3867 0.1097 25.4243 ;
		RECT 0.0098 25.6 0.0481 25.6376 ;
		RECT 0.0098 25.7506 0.0481 25.7882 ;
		RECT 0.0098 25.8384 0.0481 25.8761 ;
		RECT 0.0098 20.9318 0.0481 20.9694 ;
		RECT 0.0098 26.1396 0.0481 26.1773 ;
		RECT 0.0714 26.2024 0.1097 26.24 ;
		RECT 0.0098 26.6541 0.0481 26.6918 ;
		RECT 0.0714 27.0431 0.1097 27.0808 ;
		RECT 0.0098 27.1059 0.0481 27.1435 ;
		RECT 0.0098 27.1937 0.0481 27.2941 ;
		RECT 0.0098 27.4071 0.0481 27.4447 ;
		RECT 0.0098 27.5576 0.0481 27.5953 ;
		RECT 0.0714 27.6455 0.1097 27.6831 ;
		RECT 0.0098 27.7082 0.0481 27.7459 ;
		RECT 0.0098 21.0824 0.0481 21.12 ;
		RECT 0.0098 27.7961 0.0481 27.8965 ;
		RECT 0.0714 27.9467 0.1097 27.9843 ;
		RECT 0.0098 28.0094 0.0481 28.0471 ;
		RECT 0.0714 28.0973 0.1097 28.1349 ;
		RECT 0.0098 28.2478 0.0481 28.3482 ;
		RECT 0.0098 0.1255 0.0481 0.1631 ;
		RECT 0.0098 48.9475 0.0481 48.9851 ;
		RECT 0.0098 21.2329 0.0481 21.2706 ;
		RECT 0.0098 21.3208 0.0481 21.4212 ;
		RECT 0.0714 21.4714 0.1097 21.509 ;
		RECT 0.0098 21.5341 0.0481 21.5718 ;
		RECT 0.0714 21.622 0.1097 21.6596 ;
		 LAYER M3 SPACING 0.012 ;
		RECT 0.133 0 21.693 49.1106 ;
		RECT 0 0 0.133 0.0439 ;
		RECT 0 0.182 0.133 0.9475 ;
		RECT 0.0714 1.0918 0.133 1.2235 ;
		RECT 0 1.211 0.133 1.2235 ;
		RECT 0.0714 1.2235 0.133 1.349 ;
		RECT 0 1.4871 0.133 2.2275 ;
		RECT 0.0714 2.3718 0.133 2.5035 ;
		RECT 0 2.491 0.133 2.5035 ;
		RECT 0.0714 2.5035 0.133 2.629 ;
		RECT 0 2.7671 0.133 3.5075 ;
		RECT 0.0714 3.6518 0.133 3.7835 ;
		RECT 0 3.771 0.133 3.7835 ;
		RECT 0.0714 3.7835 0.133 3.909 ;
		RECT 0 4.0471 0.133 4.7875 ;
		RECT 0.0714 4.9318 0.133 5.0635 ;
		RECT 0 5.051 0.133 5.0635 ;
		RECT 0.0714 5.0635 0.133 5.189 ;
		RECT 0 5.3271 0.133 6.0675 ;
		RECT 0.0714 6.2118 0.133 6.3435 ;
		RECT 0 6.331 0.133 6.3435 ;
		RECT 0.0714 6.3435 0.133 6.469 ;
		RECT 0 6.6071 0.133 7.3475 ;
		RECT 0.0714 7.4918 0.133 7.6235 ;
		RECT 0 7.611 0.133 7.6235 ;
		RECT 0.0714 7.6235 0.133 7.749 ;
		RECT 0 7.8871 0.133 8.6275 ;
		RECT 0.0714 8.7718 0.133 8.9035 ;
		RECT 0 8.891 0.133 8.9035 ;
		RECT 0.0714 8.9035 0.133 9.029 ;
		RECT 0 9.1671 0.133 9.9075 ;
		RECT 0.0714 10.0518 0.133 10.1835 ;
		RECT 0 10.171 0.133 10.1835 ;
		RECT 0.0714 10.1835 0.133 10.309 ;
		RECT 0 10.4471 0.133 11.1875 ;
		RECT 0.0714 11.3318 0.133 11.4635 ;
		RECT 0 11.451 0.133 11.4635 ;
		RECT 0.0714 11.4635 0.133 11.589 ;
		RECT 0 11.7271 0.133 12.4675 ;
		RECT 0.0714 12.6118 0.133 12.7435 ;
		RECT 0 12.731 0.133 12.7435 ;
		RECT 0.0714 12.7435 0.133 12.869 ;
		RECT 0 13.0071 0.133 13.7475 ;
		RECT 0.0714 13.8918 0.133 14.0235 ;
		RECT 0 14.011 0.133 14.0235 ;
		RECT 0.0714 14.0235 0.133 14.149 ;
		RECT 0 14.2871 0.133 15.0275 ;
		RECT 0.0714 15.1718 0.133 15.3035 ;
		RECT 0 15.291 0.133 15.3035 ;
		RECT 0.0714 15.3035 0.133 15.429 ;
		RECT 0 15.5671 0.133 16.3075 ;
		RECT 0.0714 16.4518 0.133 16.5835 ;
		RECT 0 16.571 0.133 16.5835 ;
		RECT 0.0714 16.5835 0.133 16.709 ;
		RECT 0 16.8471 0.133 17.5875 ;
		RECT 0.0714 17.7318 0.133 17.8635 ;
		RECT 0 17.851 0.133 17.8635 ;
		RECT 0.0714 17.8635 0.133 17.989 ;
		RECT 0 18.1271 0.133 18.8675 ;
		RECT 0.0714 19.0118 0.133 19.1435 ;
		RECT 0 19.131 0.133 19.1435 ;
		RECT 0.0714 19.1435 0.133 19.269 ;
		RECT 0 19.4071 0.133 20.1475 ;
		RECT 0.0714 20.2918 0.133 20.4235 ;
		RECT 0 20.411 0.133 20.4235 ;
		RECT 0.0714 20.4235 0.133 20.549 ;
		RECT 0 20.6871 0.133 21.0008 ;
		RECT 0 21.1388 0.133 21.1514 ;
		RECT 0 21.2894 0.133 21.6031 ;
		RECT 0 21.7412 0.133 21.7537 ;
		RECT 0 21.8918 0.133 21.9043 ;
		RECT 0 22.0424 0.133 22.2055 ;
		RECT 0 22.3435 0.133 22.5067 ;
		RECT 0 22.6447 0.133 22.6573 ;
		RECT 0 22.7953 0.133 22.9584 ;
		RECT 0 23.0965 0.133 23.109 ;
		RECT 0 23.2471 0.133 23.2596 ;
		RECT 0 23.3976 0.133 23.4102 ;
		RECT 0 23.5482 0.133 23.5608 ;
		RECT 0 23.6988 0.133 23.7114 ;
		RECT 0 23.8494 0.133 23.862 ;
		RECT 0 24 0.133 24.0125 ;
		RECT 0 24.1506 0.133 24.1631 ;
		RECT 0 24.3012 0.133 24.3137 ;
		RECT 0 24.4518 0.133 24.4643 ;
		RECT 0 24.6024 0.133 24.6149 ;
		RECT 0 24.7529 0.133 24.7655 ;
		RECT 0 24.9035 0.133 24.9161 ;
		RECT 0 25.0541 0.133 25.0667 ;
		RECT 0 25.2047 0.133 25.2173 ;
		RECT 0 25.3553 0.133 25.3678 ;
		RECT 0 25.5059 0.133 25.5184 ;
		RECT 0 25.6565 0.133 25.669 ;
		RECT 0 25.8071 0.133 25.8196 ;
		RECT 0 25.9576 0.133 25.9702 ;
		RECT 0 26.1082 0.133 26.2714 ;
		RECT 0 26.4094 0.133 26.422 ;
		RECT 0 26.56 0.133 26.5725 ;
		RECT 0 26.7106 0.133 26.7231 ;
		RECT 0 26.8612 0.133 26.8737 ;
		RECT 0 27.0118 0.133 27.3255 ;
		RECT 0 27.4635 0.133 27.4761 ;
		RECT 0 27.6141 0.133 28.0784 ;
		RECT 0 28.2165 0.133 28.4235 ;
		RECT 0.0714 28.5678 0.133 28.6996 ;
		RECT 0 28.6871 0.133 28.6996 ;
		RECT 0.0714 28.6996 0.133 28.8251 ;
		RECT 0 28.9631 0.133 29.7035 ;
		RECT 0.0714 29.8478 0.133 29.9796 ;
		RECT 0 29.9671 0.133 29.9796 ;
		RECT 0.0714 29.9796 0.133 30.1051 ;
		RECT 0 30.2431 0.133 30.9835 ;
		RECT 0.0714 31.1278 0.133 31.2596 ;
		RECT 0 31.2471 0.133 31.2596 ;
		RECT 0.0714 31.2596 0.133 31.3851 ;
		RECT 0 31.5231 0.133 32.2635 ;
		RECT 0.0714 32.4078 0.133 32.5396 ;
		RECT 0 32.5271 0.133 32.5396 ;
		RECT 0.0714 32.5396 0.133 32.6651 ;
		RECT 0 32.8031 0.133 33.5435 ;
		RECT 0.0714 33.6878 0.133 33.8196 ;
		RECT 0 33.8071 0.133 33.8196 ;
		RECT 0.0714 33.8196 0.133 33.9451 ;
		RECT 0 34.0831 0.133 34.8235 ;
		RECT 0.0714 34.9678 0.133 35.0996 ;
		RECT 0 35.0871 0.133 35.0996 ;
		RECT 0.0714 35.0996 0.133 35.2251 ;
		RECT 0 35.3631 0.133 36.1035 ;
		RECT 0.0714 36.2478 0.133 36.3796 ;
		RECT 0 36.3671 0.133 36.3796 ;
		RECT 0.0714 36.3796 0.133 36.5051 ;
		RECT 0 36.6431 0.133 37.3835 ;
		RECT 0.0714 37.5278 0.133 37.6596 ;
		RECT 0 37.6471 0.133 37.6596 ;
		RECT 0.0714 37.6596 0.133 37.7851 ;
		RECT 0 37.9231 0.133 38.6635 ;
		RECT 0.0714 38.8078 0.133 38.9396 ;
		RECT 0 38.9271 0.133 38.9396 ;
		RECT 0.0714 38.9396 0.133 39.0651 ;
		RECT 0 39.2031 0.133 39.9435 ;
		RECT 0.0714 40.0878 0.133 40.2196 ;
		RECT 0 40.2071 0.133 40.2196 ;
		RECT 0.0714 40.2196 0.133 40.3451 ;
		RECT 0 40.4831 0.133 41.2235 ;
		RECT 0.0714 41.3678 0.133 41.4996 ;
		RECT 0 41.4871 0.133 41.4996 ;
		RECT 0.0714 41.4996 0.133 41.6251 ;
		RECT 0 41.7631 0.133 42.5035 ;
		RECT 0.0714 42.6478 0.133 42.7796 ;
		RECT 0 42.7671 0.133 42.7796 ;
		RECT 0.0714 42.7796 0.133 42.9051 ;
		RECT 0 43.0431 0.133 43.7835 ;
		RECT 0.0714 43.9278 0.133 44.0596 ;
		RECT 0 44.0471 0.133 44.0596 ;
		RECT 0.0714 44.0596 0.133 44.1851 ;
		RECT 0 44.3231 0.133 45.0635 ;
		RECT 0.0714 45.2078 0.133 45.3396 ;
		RECT 0 45.3271 0.133 45.3396 ;
		RECT 0.0714 45.3396 0.133 45.4651 ;
		RECT 0 45.6031 0.133 46.3435 ;
		RECT 0.0714 46.4878 0.133 46.6196 ;
		RECT 0 46.6071 0.133 46.6196 ;
		RECT 0.0714 46.6196 0.133 46.7451 ;
		RECT 0 46.8831 0.133 47.6235 ;
		RECT 0.0714 47.7678 0.133 47.8996 ;
		RECT 0 47.8871 0.133 47.8996 ;
		RECT 0.0714 47.8996 0.133 48.0251 ;
		RECT 0 48.1631 0.133 48.9286 ;
		RECT 0 49.0667 0.133 49.1106 ;
		 LAYER M3 ;
		RECT 0.0098 20.7184 0.0481 20.8188 ;
		RECT 0.0714 20.7184 0.1097 20.8188 ;
		RECT 0.0098 20.869 0.0481 20.9694 ;
		RECT 0.0714 20.869 0.1097 20.9694 ;
		RECT 0.0098 21.0196 0.0481 21.12 ;
		RECT 0.0098 21.1702 0.0481 21.2706 ;
		RECT 0.0098 21.3208 0.0481 21.4212 ;
		RECT 0.0098 21.4714 0.0481 21.5718 ;
		RECT 0.0714 21.4714 0.1097 21.5718 ;
		RECT 0.0714 21.622 0.1097 21.7224 ;
		RECT 0.0098 21.7725 0.0481 21.8729 ;
		RECT 0.0098 22.0737 0.0481 22.1741 ;
		RECT 0.0714 22.0737 0.1097 22.1741 ;
		RECT 0.0714 22.2243 0.1097 22.3247 ;
		RECT 0.0098 22.3749 0.0481 22.4753 ;
		RECT 0.0098 22.8267 0.0481 22.9271 ;
		RECT 0.0714 22.8267 0.1097 22.9271 ;
		RECT 0.0714 22.9773 0.1097 23.0776 ;
		RECT 0.0098 23.429 0.0481 23.5294 ;
		RECT 0.0714 23.5796 0.1097 23.68 ;
		RECT 0.0714 23.7302 0.1097 23.8306 ;
		RECT 0.0714 23.8808 0.1097 23.9812 ;
		RECT 0.0714 24.6337 0.1097 24.7341 ;
		RECT 0.0098 24.7843 0.0481 24.8847 ;
		RECT 0.0714 24.9349 0.1097 25.0353 ;
		RECT 0.0714 25.0855 0.1097 25.1859 ;
		RECT 0.0714 25.3867 0.1097 25.4871 ;
		RECT 0.0098 25.6878 0.0481 25.7882 ;
		RECT 0.0098 26.1396 0.0481 26.24 ;
		RECT 0.0714 26.1396 0.1097 26.24 ;
		RECT 0.0098 27.0431 0.0481 27.1435 ;
		RECT 0.0714 27.0431 0.1097 27.1435 ;
		RECT 0.0098 27.1937 0.0481 27.2941 ;
		RECT 0.0098 27.3443 0.0481 27.4447 ;
		RECT 0.0098 27.4949 0.0481 27.5953 ;
		RECT 0.0098 27.6455 0.0481 27.7459 ;
		RECT 0.0714 27.6455 0.1097 27.7459 ;
		RECT 0.0098 27.7961 0.0481 27.8965 ;
		RECT 0.0098 27.9467 0.0481 28.0471 ;
		RECT 0.0714 27.9467 0.1097 28.0471 ;
		RECT 0.0714 28.0973 0.1097 28.1976 ;
		RECT 0.0098 28.2478 0.0481 28.3482 ;
		RECT 0.0098 0.0627 0.0481 0.1631 ;
		RECT 0.0098 48.9475 0.0481 49.0478 ;
		 LAYER M3 SPACING 0.012 ;
		RECT 0.0098 20.7184 0.0481 20.8188 ;
		RECT 0.0714 20.7184 0.1097 20.8188 ;
		RECT 0.0098 20.869 0.0481 20.9694 ;
		RECT 0.0714 20.869 0.1097 20.9694 ;
		RECT 0.0098 21.0196 0.0481 21.12 ;
		RECT 0.0098 21.1702 0.0481 21.2706 ;
		RECT 0.0098 21.3208 0.0481 21.4212 ;
		RECT 0.0098 21.4714 0.0481 21.5718 ;
		RECT 0.0714 21.4714 0.1097 21.5718 ;
		RECT 0.0714 21.622 0.1097 21.7224 ;
		RECT 0.0098 21.7725 0.0481 21.8729 ;
		RECT 0.0098 22.0737 0.0481 22.1741 ;
		RECT 0.0714 22.0737 0.1097 22.1741 ;
		RECT 0.0714 22.2243 0.1097 22.3247 ;
		RECT 0.0098 22.3749 0.0481 22.4753 ;
		RECT 0.0098 22.8267 0.0481 22.9271 ;
		RECT 0.0714 22.8267 0.1097 22.9271 ;
		RECT 0.0714 22.9773 0.1097 23.0776 ;
		RECT 0.0098 23.429 0.0481 23.5294 ;
		RECT 0.0714 23.5796 0.1097 23.68 ;
		RECT 0.0714 23.7302 0.1097 23.8306 ;
		RECT 0.0714 23.8808 0.1097 23.9812 ;
		RECT 0.0714 24.6337 0.1097 24.7341 ;
		RECT 0.0098 24.7843 0.0481 24.8847 ;
		RECT 0.0714 24.9349 0.1097 25.0353 ;
		RECT 0.0714 25.0855 0.1097 25.1859 ;
		RECT 0.0714 25.3867 0.1097 25.4871 ;
		RECT 0.0098 25.6878 0.0481 25.7882 ;
		RECT 0.0098 26.1396 0.0481 26.24 ;
		RECT 0.0714 26.1396 0.1097 26.24 ;
		RECT 0.0098 27.0431 0.0481 27.1435 ;
		RECT 0.0714 27.0431 0.1097 27.1435 ;
		RECT 0.0098 27.1937 0.0481 27.2941 ;
		RECT 0.0098 27.3443 0.0481 27.4447 ;
		RECT 0.0098 27.4949 0.0481 27.5953 ;
		RECT 0.0098 27.6455 0.0481 27.7459 ;
		RECT 0.0714 27.6455 0.1097 27.7459 ;
		RECT 0.0098 27.7961 0.0481 27.8965 ;
		RECT 0.0098 27.9467 0.0481 28.0471 ;
		RECT 0.0714 27.9467 0.1097 28.0471 ;
		RECT 0.0714 28.0973 0.1097 28.1976 ;
		RECT 0.0098 28.2478 0.0481 28.3482 ;
		RECT 0.0098 0.0627 0.0481 0.1631 ;
		RECT 0.0098 48.9475 0.0481 49.0478 ;
		 LAYER M4 SPACING 0.018 ;
		RECT 0.2105 0.3286 21.546 0.5302 ;
		RECT 21.546 0.3286 21.693 0.5302 ;
		RECT 0.2105 0.64 21.546 0.7631 ;
		RECT 21.546 0.64 21.693 0.7631 ;
		RECT 0.2105 0.9686 21.546 1.1702 ;
		RECT 21.546 0.9686 21.693 1.1702 ;
		RECT 0.2105 1.28 21.546 1.4031 ;
		RECT 21.546 1.28 21.693 1.4031 ;
		RECT 0.2105 1.6086 21.546 1.8102 ;
		RECT 21.546 1.6086 21.693 1.8102 ;
		RECT 0.2105 1.92 21.546 2.0431 ;
		RECT 21.546 1.92 21.693 2.0431 ;
		RECT 0.2105 2.2486 21.546 2.4502 ;
		RECT 21.546 2.2486 21.693 2.4502 ;
		RECT 0.2105 2.56 21.546 2.6831 ;
		RECT 21.546 2.56 21.693 2.6831 ;
		RECT 0.2105 2.8886 21.546 3.0902 ;
		RECT 21.546 2.8886 21.693 3.0902 ;
		RECT 0.2105 3.2 21.546 3.3231 ;
		RECT 21.546 3.2 21.693 3.3231 ;
		RECT 0.2105 3.5286 21.546 3.7302 ;
		RECT 21.546 3.5286 21.693 3.7302 ;
		RECT 0.2105 3.84 21.546 3.9631 ;
		RECT 21.546 3.84 21.693 3.9631 ;
		RECT 0.2105 4.1686 21.546 4.3702 ;
		RECT 21.546 4.1686 21.693 4.3702 ;
		RECT 0.2105 4.48 21.546 4.6031 ;
		RECT 21.546 4.48 21.693 4.6031 ;
		RECT 0.2105 4.8086 21.546 5.0102 ;
		RECT 21.546 4.8086 21.693 5.0102 ;
		RECT 0.2105 5.12 21.546 5.2431 ;
		RECT 21.546 5.12 21.693 5.2431 ;
		RECT 0.2105 5.4486 21.546 5.6502 ;
		RECT 21.546 5.4486 21.693 5.6502 ;
		RECT 0.2105 5.76 21.546 5.8831 ;
		RECT 21.546 5.76 21.693 5.8831 ;
		RECT 0.2105 6.0886 21.546 6.2902 ;
		RECT 21.546 6.0886 21.693 6.2902 ;
		RECT 0.2105 6.4 21.546 6.5231 ;
		RECT 21.546 6.4 21.693 6.5231 ;
		RECT 0.2105 6.7286 21.546 6.9302 ;
		RECT 21.546 6.7286 21.693 6.9302 ;
		RECT 0.2105 7.04 21.546 7.1631 ;
		RECT 21.546 7.04 21.693 7.1631 ;
		RECT 0.2105 7.3686 21.546 7.5702 ;
		RECT 21.546 7.3686 21.693 7.5702 ;
		RECT 0.2105 7.68 21.546 7.8031 ;
		RECT 21.546 7.68 21.693 7.8031 ;
		RECT 0.2105 8.0086 21.546 8.2102 ;
		RECT 21.546 8.0086 21.693 8.2102 ;
		RECT 0.2105 8.32 21.546 8.4431 ;
		RECT 21.546 8.32 21.693 8.4431 ;
		RECT 0.2105 8.6486 21.546 8.8502 ;
		RECT 21.546 8.6486 21.693 8.8502 ;
		RECT 0.2105 8.96 21.546 9.0831 ;
		RECT 21.546 8.96 21.693 9.0831 ;
		RECT 0.2105 9.2886 21.546 9.4902 ;
		RECT 21.546 9.2886 21.693 9.4902 ;
		RECT 0.2105 9.6 21.546 9.7231 ;
		RECT 21.546 9.6 21.693 9.7231 ;
		RECT 0.2105 9.9286 21.546 10.1302 ;
		RECT 21.546 9.9286 21.693 10.1302 ;
		RECT 0.2105 10.24 21.546 10.3631 ;
		RECT 21.546 10.24 21.693 10.3631 ;
		RECT 0.2105 10.5686 21.546 10.7702 ;
		RECT 21.546 10.5686 21.693 10.7702 ;
		RECT 0.2105 10.88 21.546 11.0031 ;
		RECT 21.546 10.88 21.693 11.0031 ;
		RECT 0.2105 11.2086 21.546 11.4102 ;
		RECT 21.546 11.2086 21.693 11.4102 ;
		RECT 0.2105 11.52 21.546 11.6431 ;
		RECT 21.546 11.52 21.693 11.6431 ;
		RECT 0.2105 11.8486 21.546 12.0502 ;
		RECT 21.546 11.8486 21.693 12.0502 ;
		RECT 0.2105 12.16 21.546 12.2831 ;
		RECT 21.546 12.16 21.693 12.2831 ;
		RECT 0.2105 12.4886 21.546 12.6902 ;
		RECT 21.546 12.4886 21.693 12.6902 ;
		RECT 0.2105 12.8 21.546 12.9231 ;
		RECT 21.546 12.8 21.693 12.9231 ;
		RECT 0.2105 13.1286 21.546 13.3302 ;
		RECT 21.546 13.1286 21.693 13.3302 ;
		RECT 0.2105 13.44 21.546 13.5631 ;
		RECT 21.546 13.44 21.693 13.5631 ;
		RECT 0.2105 13.7686 21.546 13.9702 ;
		RECT 21.546 13.7686 21.693 13.9702 ;
		RECT 0.2105 14.08 21.546 14.2031 ;
		RECT 21.546 14.08 21.693 14.2031 ;
		RECT 0.2105 14.4086 21.546 14.6102 ;
		RECT 21.546 14.4086 21.693 14.6102 ;
		RECT 0.2105 14.72 21.546 14.8431 ;
		RECT 21.546 14.72 21.693 14.8431 ;
		RECT 0.2105 15.0486 21.546 15.2502 ;
		RECT 21.546 15.0486 21.693 15.2502 ;
		RECT 0.2105 15.36 21.546 15.4831 ;
		RECT 21.546 15.36 21.693 15.4831 ;
		RECT 0.2105 15.6886 21.546 15.8902 ;
		RECT 21.546 15.6886 21.693 15.8902 ;
		RECT 0.2105 16 21.546 16.1231 ;
		RECT 21.546 16 21.693 16.1231 ;
		RECT 0.2105 16.3286 21.546 16.5302 ;
		RECT 21.546 16.3286 21.693 16.5302 ;
		RECT 0.2105 16.64 21.546 16.7631 ;
		RECT 21.546 16.64 21.693 16.7631 ;
		RECT 0.2105 16.9686 21.546 17.1702 ;
		RECT 21.546 16.9686 21.693 17.1702 ;
		RECT 0.2105 17.28 21.546 17.4031 ;
		RECT 21.546 17.28 21.693 17.4031 ;
		RECT 0.2105 17.6086 21.546 17.8102 ;
		RECT 21.546 17.6086 21.693 17.8102 ;
		RECT 0.2105 17.92 21.546 18.0431 ;
		RECT 21.546 17.92 21.693 18.0431 ;
		RECT 0.2105 18.2486 21.546 18.4502 ;
		RECT 21.546 18.2486 21.693 18.4502 ;
		RECT 0.2105 18.56 21.546 18.6831 ;
		RECT 21.546 18.56 21.693 18.6831 ;
		RECT 0.2105 18.8886 21.546 19.0902 ;
		RECT 21.546 18.8886 21.693 19.0902 ;
		RECT 0.2105 19.2 21.546 19.3231 ;
		RECT 21.546 19.2 21.693 19.3231 ;
		RECT 0.2105 19.5286 21.546 19.7302 ;
		RECT 21.546 19.5286 21.693 19.7302 ;
		RECT 0.2105 19.84 21.546 19.9631 ;
		RECT 21.546 19.84 21.693 19.9631 ;
		RECT 0.2105 20.1686 21.546 20.3702 ;
		RECT 21.546 20.1686 21.693 20.3702 ;
		RECT 0.2105 20.48 21.546 20.6031 ;
		RECT 21.546 20.48 21.693 20.6031 ;
		RECT 0.2105 21.0667 21.546 21.3161 ;
		RECT 21.546 21.0667 21.693 21.3161 ;
		RECT 0.2105 21.7961 21.546 22.1349 ;
		RECT 21.546 21.7961 21.693 22.1349 ;
		RECT 0.2105 22.3231 21.546 22.662 ;
		RECT 21.546 22.3231 21.693 22.662 ;
		RECT 0.2105 22.8502 21.546 23.189 ;
		RECT 21.546 22.8502 21.693 23.189 ;
		RECT 0.2105 23.3773 21.546 23.7161 ;
		RECT 21.546 23.3773 21.693 23.7161 ;
		RECT 0.2105 23.9043 21.546 24.7702 ;
		RECT 21.546 23.9043 21.693 24.7702 ;
		RECT 0.2105 24.9584 21.546 25.8243 ;
		RECT 21.546 24.9584 21.693 25.8243 ;
		RECT 0.2105 26.0125 21.546 26.3514 ;
		RECT 21.546 26.0125 21.693 26.3514 ;
		RECT 0.2105 26.5396 21.546 26.8784 ;
		RECT 21.546 26.5396 21.693 26.8784 ;
		RECT 0.2105 27.0667 21.546 27.4055 ;
		RECT 21.546 27.0667 21.693 27.4055 ;
		RECT 0.2105 27.9639 21.546 28.2043 ;
		RECT 21.546 27.9639 21.693 28.2043 ;
		RECT 0.2105 28.5075 21.546 28.6306 ;
		RECT 21.546 28.5075 21.693 28.6306 ;
		RECT 0.2105 28.7404 21.546 28.942 ;
		RECT 21.546 28.7404 21.693 28.942 ;
		RECT 0.2105 29.1475 21.546 29.2706 ;
		RECT 21.546 29.1475 21.693 29.2706 ;
		RECT 0.2105 29.3804 21.546 29.582 ;
		RECT 21.546 29.3804 21.693 29.582 ;
		RECT 0.2105 29.7875 21.546 29.9106 ;
		RECT 21.546 29.7875 21.693 29.9106 ;
		RECT 0.2105 30.0204 21.546 30.222 ;
		RECT 21.546 30.0204 21.693 30.222 ;
		RECT 0.2105 30.4275 21.546 30.5506 ;
		RECT 21.546 30.4275 21.693 30.5506 ;
		RECT 0.2105 30.6604 21.546 30.862 ;
		RECT 21.546 30.6604 21.693 30.862 ;
		RECT 0.2105 31.0675 21.546 31.1906 ;
		RECT 21.546 31.0675 21.693 31.1906 ;
		RECT 0.2105 31.3004 21.546 31.502 ;
		RECT 21.546 31.3004 21.693 31.502 ;
		RECT 0.2105 31.7075 21.546 31.8306 ;
		RECT 21.546 31.7075 21.693 31.8306 ;
		RECT 0.2105 31.9404 21.546 32.142 ;
		RECT 21.546 31.9404 21.693 32.142 ;
		RECT 0.2105 32.3475 21.546 32.4706 ;
		RECT 21.546 32.3475 21.693 32.4706 ;
		RECT 0.2105 32.5804 21.546 32.782 ;
		RECT 21.546 32.5804 21.693 32.782 ;
		RECT 0.2105 32.9875 21.546 33.1106 ;
		RECT 21.546 32.9875 21.693 33.1106 ;
		RECT 0.2105 33.2204 21.546 33.422 ;
		RECT 21.546 33.2204 21.693 33.422 ;
		RECT 0.2105 33.6275 21.546 33.7506 ;
		RECT 21.546 33.6275 21.693 33.7506 ;
		RECT 0.2105 33.8604 21.546 34.062 ;
		RECT 21.546 33.8604 21.693 34.062 ;
		RECT 0.2105 34.2675 21.546 34.3906 ;
		RECT 21.546 34.2675 21.693 34.3906 ;
		RECT 0.2105 34.5004 21.546 34.702 ;
		RECT 21.546 34.5004 21.693 34.702 ;
		RECT 0.2105 34.9075 21.546 35.0306 ;
		RECT 21.546 34.9075 21.693 35.0306 ;
		RECT 0.2105 35.1404 21.546 35.342 ;
		RECT 21.546 35.1404 21.693 35.342 ;
		RECT 0.2105 35.5475 21.546 35.6706 ;
		RECT 21.546 35.5475 21.693 35.6706 ;
		RECT 0.2105 35.7804 21.546 35.982 ;
		RECT 21.546 35.7804 21.693 35.982 ;
		RECT 0.2105 36.1875 21.546 36.3106 ;
		RECT 21.546 36.1875 21.693 36.3106 ;
		RECT 0.2105 36.4204 21.546 36.622 ;
		RECT 21.546 36.4204 21.693 36.622 ;
		RECT 0.2105 36.8275 21.546 36.9506 ;
		RECT 21.546 36.8275 21.693 36.9506 ;
		RECT 0.2105 37.0604 21.546 37.262 ;
		RECT 21.546 37.0604 21.693 37.262 ;
		RECT 0.2105 37.4675 21.546 37.5906 ;
		RECT 21.546 37.4675 21.693 37.5906 ;
		RECT 0.2105 37.7004 21.546 37.902 ;
		RECT 21.546 37.7004 21.693 37.902 ;
		RECT 0.2105 38.1075 21.546 38.2306 ;
		RECT 21.546 38.1075 21.693 38.2306 ;
		RECT 0.2105 38.3404 21.546 38.542 ;
		RECT 21.546 38.3404 21.693 38.542 ;
		RECT 0.2105 38.7475 21.546 38.8706 ;
		RECT 21.546 38.7475 21.693 38.8706 ;
		RECT 0.2105 38.9804 21.546 39.182 ;
		RECT 21.546 38.9804 21.693 39.182 ;
		RECT 0.2105 39.3875 21.546 39.5106 ;
		RECT 21.546 39.3875 21.693 39.5106 ;
		RECT 0.2105 39.6204 21.546 39.822 ;
		RECT 21.546 39.6204 21.693 39.822 ;
		RECT 0.2105 40.0275 21.546 40.1506 ;
		RECT 21.546 40.0275 21.693 40.1506 ;
		RECT 0.2105 40.2604 21.546 40.462 ;
		RECT 21.546 40.2604 21.693 40.462 ;
		RECT 0.2105 40.6675 21.546 40.7906 ;
		RECT 21.546 40.6675 21.693 40.7906 ;
		RECT 0.2105 40.9004 21.546 41.102 ;
		RECT 21.546 40.9004 21.693 41.102 ;
		RECT 0.2105 41.3075 21.546 41.4306 ;
		RECT 21.546 41.3075 21.693 41.4306 ;
		RECT 0.2105 41.5404 21.546 41.742 ;
		RECT 21.546 41.5404 21.693 41.742 ;
		RECT 0.2105 41.9475 21.546 42.0706 ;
		RECT 21.546 41.9475 21.693 42.0706 ;
		RECT 0.2105 42.1804 21.546 42.382 ;
		RECT 21.546 42.1804 21.693 42.382 ;
		RECT 0.2105 42.5875 21.546 42.7106 ;
		RECT 21.546 42.5875 21.693 42.7106 ;
		RECT 0.2105 42.8204 21.546 43.022 ;
		RECT 21.546 42.8204 21.693 43.022 ;
		RECT 0.2105 43.2275 21.546 43.3506 ;
		RECT 21.546 43.2275 21.693 43.3506 ;
		RECT 0.2105 43.4604 21.546 43.662 ;
		RECT 21.546 43.4604 21.693 43.662 ;
		RECT 0.2105 43.8675 21.546 43.9906 ;
		RECT 21.546 43.8675 21.693 43.9906 ;
		RECT 0.2105 44.1004 21.546 44.302 ;
		RECT 21.546 44.1004 21.693 44.302 ;
		RECT 0.2105 44.5075 21.546 44.6306 ;
		RECT 21.546 44.5075 21.693 44.6306 ;
		RECT 0.2105 44.7404 21.546 44.942 ;
		RECT 21.546 44.7404 21.693 44.942 ;
		RECT 0.2105 45.1475 21.546 45.2706 ;
		RECT 21.546 45.1475 21.693 45.2706 ;
		RECT 0.2105 45.3804 21.546 45.582 ;
		RECT 21.546 45.3804 21.693 45.582 ;
		RECT 0.2105 45.7875 21.546 45.9106 ;
		RECT 21.546 45.7875 21.693 45.9106 ;
		RECT 0.2105 46.0204 21.546 46.222 ;
		RECT 21.546 46.0204 21.693 46.222 ;
		RECT 0.2105 46.4275 21.546 46.5506 ;
		RECT 21.546 46.4275 21.693 46.5506 ;
		RECT 0.2105 46.6604 21.546 46.862 ;
		RECT 21.546 46.6604 21.693 46.862 ;
		RECT 0.2105 47.0675 21.546 47.1906 ;
		RECT 21.546 47.0675 21.693 47.1906 ;
		RECT 0.2105 47.3004 21.546 47.502 ;
		RECT 21.546 47.3004 21.693 47.502 ;
		RECT 0.2105 47.7075 21.546 47.8306 ;
		RECT 21.546 47.7075 21.693 47.8306 ;
		RECT 0.2105 47.9404 21.546 48.142 ;
		RECT 21.546 47.9404 21.693 48.142 ;
		RECT 0.2105 48.3475 21.546 48.4706 ;
		RECT 21.546 48.3475 21.693 48.4706 ;
		RECT 0.2105 48.5804 21.546 48.782 ;
		RECT 21.546 48.5804 21.693 48.782 ;
		 LAYER M4 ;
		RECT 0.2105 0 21.546 0.022 ;
		RECT 21.546 0 21.693 0.022 ;
		RECT 0.2105 21.5043 21.546 21.5294 ;
		RECT 21.546 21.5043 21.693 21.5294 ;
		RECT 0.2105 27.7506 21.546 27.7757 ;
		RECT 21.546 27.7506 21.693 27.7757 ;
		RECT 0.2105 49.0886 21.546 49.1106 ;
		RECT 21.546 49.0886 21.693 49.1106 ;
		 LAYER M4 SPACING 0.018 ;
		RECT 0.2105 0 21.546 0.022 ;
		RECT 21.546 0 21.693 0.022 ;
		RECT 0.2105 21.5043 21.546 21.5294 ;
		RECT 21.546 21.5043 21.693 21.5294 ;
		RECT 0.2105 27.7506 21.546 27.7757 ;
		RECT 21.546 27.7506 21.693 27.7757 ;
		RECT 0.2105 49.0886 21.546 49.1106 ;
		RECT 21.546 49.0886 21.693 49.1106 ;
		 LAYER V1 SPACING 0 ;
		RECT 0 0 21.693 49.1106 ;
		 LAYER V2 SPACING 0 ;
		RECT 0.1097 0 21.693 49.1106 ;
		RECT 0 0 0.1097 0.0627 ;
		RECT 0 0.1631 0.1097 0.9663 ;
		RECT 0 1.0667 0.1097 1.0918 ;
		RECT 0 1.1922 0.1097 1.2424 ;
		RECT 0 1.3427 0.1097 1.3678 ;
		RECT 0 1.4682 0.1097 2.2463 ;
		RECT 0 2.3467 0.1097 2.3718 ;
		RECT 0 2.4722 0.1097 2.5224 ;
		RECT 0 2.6227 0.1097 2.6478 ;
		RECT 0 2.7482 0.1097 3.5263 ;
		RECT 0 3.6267 0.1097 3.6518 ;
		RECT 0 3.7522 0.1097 3.8024 ;
		RECT 0 3.9027 0.1097 3.9278 ;
		RECT 0 4.0282 0.1097 4.8063 ;
		RECT 0 4.9067 0.1097 4.9318 ;
		RECT 0 5.0322 0.1097 5.0824 ;
		RECT 0 5.1827 0.1097 5.2078 ;
		RECT 0 5.3082 0.1097 6.0863 ;
		RECT 0 6.1867 0.1097 6.2118 ;
		RECT 0 6.3122 0.1097 6.3624 ;
		RECT 0 6.4627 0.1097 6.4878 ;
		RECT 0 6.5882 0.1097 7.3663 ;
		RECT 0 7.4667 0.1097 7.4918 ;
		RECT 0 7.5922 0.1097 7.6424 ;
		RECT 0 7.7427 0.1097 7.7678 ;
		RECT 0 7.8682 0.1097 8.6463 ;
		RECT 0 8.7467 0.1097 8.7718 ;
		RECT 0 8.8722 0.1097 8.9224 ;
		RECT 0 9.0227 0.1097 9.0478 ;
		RECT 0 9.1482 0.1097 9.9263 ;
		RECT 0 10.0267 0.1097 10.0518 ;
		RECT 0 10.1522 0.1097 10.2024 ;
		RECT 0 10.3027 0.1097 10.3278 ;
		RECT 0 10.4282 0.1097 11.2063 ;
		RECT 0 11.3067 0.1097 11.3318 ;
		RECT 0 11.4322 0.1097 11.4824 ;
		RECT 0 11.5827 0.1097 11.6078 ;
		RECT 0 11.7082 0.1097 12.4863 ;
		RECT 0 12.5867 0.1097 12.6118 ;
		RECT 0 12.7122 0.1097 12.7624 ;
		RECT 0 12.8627 0.1097 12.8878 ;
		RECT 0 12.9882 0.1097 13.7663 ;
		RECT 0 13.8667 0.1097 13.8918 ;
		RECT 0 13.9922 0.1097 14.0424 ;
		RECT 0 14.1427 0.1097 14.1678 ;
		RECT 0 14.2682 0.1097 15.0463 ;
		RECT 0 15.1467 0.1097 15.1718 ;
		RECT 0 15.2722 0.1097 15.3224 ;
		RECT 0 15.4227 0.1097 15.4478 ;
		RECT 0 15.5482 0.1097 16.3263 ;
		RECT 0 16.4267 0.1097 16.4518 ;
		RECT 0 16.5522 0.1097 16.6024 ;
		RECT 0 16.7027 0.1097 16.7278 ;
		RECT 0 16.8282 0.1097 17.6063 ;
		RECT 0 17.7067 0.1097 17.7318 ;
		RECT 0 17.8322 0.1097 17.8824 ;
		RECT 0 17.9827 0.1097 18.0078 ;
		RECT 0 18.1082 0.1097 18.8863 ;
		RECT 0 18.9867 0.1097 19.0118 ;
		RECT 0 19.1122 0.1097 19.1624 ;
		RECT 0 19.2627 0.1097 19.2878 ;
		RECT 0 19.3882 0.1097 20.1663 ;
		RECT 0 20.2667 0.1097 20.2918 ;
		RECT 0 20.3922 0.1097 20.4424 ;
		RECT 0 20.5427 0.1097 20.5678 ;
		RECT 0 20.6682 0.1097 21.0196 ;
		RECT 0 21.12 0.1097 21.1702 ;
		RECT 0 21.2706 0.1097 21.622 ;
		RECT 0 21.7224 0.1097 21.7725 ;
		RECT 0 21.8729 0.1097 21.9231 ;
		RECT 0 22.0235 0.1097 22.2243 ;
		RECT 0 22.3247 0.1097 22.5255 ;
		RECT 0 22.6259 0.1097 22.6761 ;
		RECT 0 22.7765 0.1097 22.9773 ;
		RECT 0 23.0776 0.1097 23.1278 ;
		RECT 0 23.2282 0.1097 23.2784 ;
		RECT 0 23.3788 0.1097 23.429 ;
		RECT 0 23.5294 0.1097 23.5796 ;
		RECT 0 23.5796 0.0098 23.68 ;
		RECT 0 23.68 0.1097 23.7302 ;
		RECT 0 23.8306 0.1097 23.8808 ;
		RECT 0 23.9812 0.1097 24.0314 ;
		RECT 0 24.1318 0.1097 24.182 ;
		RECT 0 24.2824 0.1097 24.3325 ;
		RECT 0 24.4329 0.1097 24.4831 ;
		RECT 0 24.5835 0.1097 24.6337 ;
		RECT 0 24.7341 0.1097 24.7843 ;
		RECT 0 24.8847 0.1097 24.9349 ;
		RECT 0 24.9349 0.0098 25.0353 ;
		RECT 0 25.0353 0.1097 25.0855 ;
		RECT 0 25.1859 0.1097 25.2361 ;
		RECT 0 25.3365 0.1097 25.3867 ;
		RECT 0 25.4871 0.1097 25.5373 ;
		RECT 0 25.5373 0.0098 25.6376 ;
		RECT 0 25.6376 0.1097 25.6878 ;
		RECT 0 25.7882 0.1097 25.8384 ;
		RECT 0 25.8384 0.0098 25.9388 ;
		RECT 0 25.9388 0.1097 25.989 ;
		RECT 0 25.989 0.0098 26.0894 ;
		RECT 0 26.0894 0.1097 26.2902 ;
		RECT 0 26.3906 0.1097 26.4408 ;
		RECT 0 26.5412 0.1097 26.5914 ;
		RECT 0 26.5914 0.0098 26.6918 ;
		RECT 0 26.6918 0.1097 26.742 ;
		RECT 0 26.8424 0.1097 26.8925 ;
		RECT 0 26.9929 0.1097 27.3443 ;
		RECT 0 27.4447 0.1097 27.4949 ;
		RECT 0 27.5953 0.1097 28.0973 ;
		RECT 0 28.1976 0.1097 28.4424 ;
		RECT 0 28.5427 0.1097 28.5678 ;
		RECT 0 28.6682 0.1097 28.7184 ;
		RECT 0 28.8188 0.1097 28.8439 ;
		RECT 0 28.9443 0.1097 29.7224 ;
		RECT 0 29.8227 0.1097 29.8478 ;
		RECT 0 29.9482 0.1097 29.9984 ;
		RECT 0 30.0988 0.1097 30.1239 ;
		RECT 0 30.2243 0.1097 31.0024 ;
		RECT 0 31.1027 0.1097 31.1278 ;
		RECT 0 31.2282 0.1097 31.2784 ;
		RECT 0 31.3788 0.1097 31.4039 ;
		RECT 0 31.5043 0.1097 32.2824 ;
		RECT 0 32.3827 0.1097 32.4078 ;
		RECT 0 32.5082 0.1097 32.5584 ;
		RECT 0 32.6588 0.1097 32.6839 ;
		RECT 0 32.7843 0.1097 33.5624 ;
		RECT 0 33.6627 0.1097 33.6878 ;
		RECT 0 33.7882 0.1097 33.8384 ;
		RECT 0 33.9388 0.1097 33.9639 ;
		RECT 0 34.0643 0.1097 34.8424 ;
		RECT 0 34.9427 0.1097 34.9678 ;
		RECT 0 35.0682 0.1097 35.1184 ;
		RECT 0 35.2188 0.1097 35.2439 ;
		RECT 0 35.3443 0.1097 36.1224 ;
		RECT 0 36.2227 0.1097 36.2478 ;
		RECT 0 36.3482 0.1097 36.3984 ;
		RECT 0 36.4988 0.1097 36.5239 ;
		RECT 0 36.6243 0.1097 37.4024 ;
		RECT 0 37.5027 0.1097 37.5278 ;
		RECT 0 37.6282 0.1097 37.6784 ;
		RECT 0 37.7788 0.1097 37.8039 ;
		RECT 0 37.9043 0.1097 38.6824 ;
		RECT 0 38.7827 0.1097 38.8078 ;
		RECT 0 38.9082 0.1097 38.9584 ;
		RECT 0 39.0588 0.1097 39.0839 ;
		RECT 0 39.1843 0.1097 39.9624 ;
		RECT 0 40.0627 0.1097 40.0878 ;
		RECT 0 40.1882 0.1097 40.2384 ;
		RECT 0 40.3388 0.1097 40.3639 ;
		RECT 0 40.4643 0.1097 41.2424 ;
		RECT 0 41.3427 0.1097 41.3678 ;
		RECT 0 41.4682 0.1097 41.5184 ;
		RECT 0 41.6188 0.1097 41.6439 ;
		RECT 0 41.7443 0.1097 42.5224 ;
		RECT 0 42.6227 0.1097 42.6478 ;
		RECT 0 42.7482 0.1097 42.7984 ;
		RECT 0 42.8988 0.1097 42.9239 ;
		RECT 0 43.0243 0.1097 43.8024 ;
		RECT 0 43.9027 0.1097 43.9278 ;
		RECT 0 44.0282 0.1097 44.0784 ;
		RECT 0 44.1788 0.1097 44.2039 ;
		RECT 0 44.3043 0.1097 45.0824 ;
		RECT 0 45.1827 0.1097 45.2078 ;
		RECT 0 45.3082 0.1097 45.3584 ;
		RECT 0 45.4588 0.1097 45.4839 ;
		RECT 0 45.5843 0.1097 46.3624 ;
		RECT 0 46.4627 0.1097 46.4878 ;
		RECT 0 46.5882 0.1097 46.6384 ;
		RECT 0 46.7388 0.1097 46.7639 ;
		RECT 0 46.8643 0.1097 47.6424 ;
		RECT 0 47.7427 0.1097 47.7678 ;
		RECT 0 47.8682 0.1097 47.9184 ;
		RECT 0 48.0188 0.1097 48.0439 ;
		RECT 0 48.1443 0.1097 48.9475 ;
		RECT 0 49.0478 0.1097 49.1106 ;
		 LAYER V2 ;
		RECT 0.0481 1.0918 0.1097 1.2424 ;
		RECT 0.0481 1.2424 0.1097 1.3678 ;
		RECT 0.0481 2.3718 0.1097 2.5224 ;
		RECT 0.0481 2.5224 0.1097 2.6478 ;
		RECT 0.0481 3.6518 0.1097 3.8024 ;
		RECT 0.0481 3.8024 0.1097 3.9278 ;
		RECT 0.0481 4.9318 0.1097 5.0824 ;
		RECT 0.0481 5.0824 0.1097 5.2078 ;
		RECT 0.0481 6.2118 0.1097 6.3624 ;
		RECT 0.0481 6.3624 0.1097 6.4878 ;
		RECT 0.0481 7.4918 0.1097 7.6424 ;
		RECT 0.0481 7.6424 0.1097 7.7678 ;
		RECT 0.0481 8.7718 0.1097 8.9224 ;
		RECT 0.0481 8.9224 0.1097 9.0478 ;
		RECT 0.0481 10.0518 0.1097 10.2024 ;
		RECT 0.0481 10.2024 0.1097 10.3278 ;
		RECT 0.0481 11.3318 0.1097 11.4824 ;
		RECT 0.0481 11.4824 0.1097 11.6078 ;
		RECT 0.0481 12.6118 0.1097 12.7624 ;
		RECT 0.0481 12.7624 0.1097 12.8878 ;
		RECT 0.0481 13.8918 0.1097 14.0424 ;
		RECT 0.0481 14.0424 0.1097 14.1678 ;
		RECT 0.0481 15.1718 0.1097 15.3224 ;
		RECT 0.0481 15.3224 0.1097 15.4478 ;
		RECT 0.0481 16.4518 0.1097 16.6024 ;
		RECT 0.0481 16.6024 0.1097 16.7278 ;
		RECT 0.0481 17.7318 0.1097 17.8824 ;
		RECT 0.0481 17.8824 0.1097 18.0078 ;
		RECT 0.0481 19.0118 0.1097 19.1624 ;
		RECT 0.0481 19.1624 0.1097 19.2878 ;
		RECT 0.0481 20.2918 0.1097 20.4424 ;
		RECT 0.0481 20.4424 0.1097 20.5678 ;
		RECT 0.0481 28.5678 0.1097 28.7184 ;
		RECT 0.0481 28.7184 0.1097 28.8439 ;
		RECT 0.0481 29.8478 0.1097 29.9984 ;
		RECT 0.0481 29.9984 0.1097 30.1239 ;
		RECT 0.0481 31.1278 0.1097 31.2784 ;
		RECT 0.0481 31.2784 0.1097 31.4039 ;
		RECT 0.0481 32.4078 0.1097 32.5584 ;
		RECT 0.0481 32.5584 0.1097 32.6839 ;
		RECT 0.0481 33.6878 0.1097 33.8384 ;
		RECT 0.0481 33.8384 0.1097 33.9639 ;
		RECT 0.0481 34.9678 0.1097 35.1184 ;
		RECT 0.0481 35.1184 0.1097 35.2439 ;
		RECT 0.0481 36.2478 0.1097 36.3984 ;
		RECT 0.0481 36.3984 0.1097 36.5239 ;
		RECT 0.0481 37.5278 0.1097 37.6784 ;
		RECT 0.0481 37.6784 0.1097 37.8039 ;
		RECT 0.0481 38.8078 0.1097 38.9584 ;
		RECT 0.0481 38.9584 0.1097 39.0839 ;
		RECT 0.0481 40.0878 0.1097 40.2384 ;
		RECT 0.0481 40.2384 0.1097 40.3639 ;
		RECT 0.0481 41.3678 0.1097 41.5184 ;
		RECT 0.0481 41.5184 0.1097 41.6439 ;
		RECT 0.0481 42.6478 0.1097 42.7984 ;
		RECT 0.0481 42.7984 0.1097 42.9239 ;
		RECT 0.0481 43.9278 0.1097 44.0784 ;
		RECT 0.0481 44.0784 0.1097 44.2039 ;
		RECT 0.0481 45.2078 0.1097 45.3584 ;
		RECT 0.0481 45.3584 0.1097 45.4839 ;
		RECT 0.0481 46.4878 0.1097 46.6384 ;
		RECT 0.0481 46.6384 0.1097 46.7639 ;
		RECT 0.0481 47.7678 0.1097 47.9184 ;
		RECT 0.0481 47.9184 0.1097 48.0439 ;
		RECT 0.0831 20.7306 0.098 20.7431 ;
		RECT 0.0215 20.7933 0.0364 20.8059 ;
		RECT 0.0831 20.8812 0.098 20.8937 ;
		RECT 0.0215 20.9439 0.0364 20.9565 ;
		RECT 0.0215 21.0945 0.0364 21.1071 ;
		RECT 0.0215 21.2451 0.0364 21.2576 ;
		RECT 0.021 21.3337 0.0359 21.3463 ;
		RECT 0.0831 21.4835 0.098 21.4961 ;
		RECT 0.0215 21.5463 0.0364 21.5588 ;
		RECT 0.0831 21.6341 0.098 21.6467 ;
		RECT 0.0215 21.8475 0.0364 21.86 ;
		RECT 0.0831 22.0859 0.098 22.0984 ;
		RECT 0.0215 22.1486 0.0364 22.1612 ;
		RECT 0.0831 22.2365 0.098 22.249 ;
		RECT 0.021 22.3878 0.0359 22.4004 ;
		RECT 0.0831 22.8388 0.098 22.8514 ;
		RECT 0.0215 22.9016 0.0364 22.9141 ;
		RECT 0.0831 22.9894 0.098 23.002 ;
		RECT 0.0215 23.5039 0.0364 23.5165 ;
		RECT 0.0831 23.6239 0.098 23.6365 ;
		RECT 0.0831 23.7424 0.098 23.7549 ;
		RECT 0.0831 23.8929 0.098 23.9055 ;
		RECT 0.0831 24.6459 0.098 24.6584 ;
		RECT 0.0215 24.8592 0.0364 24.8718 ;
		RECT 0.0831 24.9792 0.098 24.9918 ;
		RECT 0.0831 25.0976 0.098 25.1102 ;
		RECT 0.0831 25.3988 0.098 25.4114 ;
		RECT 0.0831 25.5816 0.098 25.5941 ;
		RECT 0.0215 25.7627 0.0364 25.7753 ;
		RECT 0.0831 25.8827 0.098 25.8953 ;
		RECT 0.0831 26.0325 0.098 26.0451 ;
		RECT 0.0215 26.1525 0.0364 26.1651 ;
		RECT 0.0831 26.2153 0.098 26.2278 ;
		RECT 0.0831 26.6357 0.098 26.6482 ;
		RECT 0.0831 27.0553 0.098 27.0678 ;
		RECT 0.0215 27.118 0.0364 27.1306 ;
		RECT 0.021 27.2067 0.0359 27.2192 ;
		RECT 0.0215 27.4192 0.0364 27.4318 ;
		RECT 0.0215 27.5698 0.0364 27.5824 ;
		RECT 0.0831 27.6576 0.098 27.6702 ;
		RECT 0.0215 27.7204 0.0364 27.7329 ;
		RECT 0.021 27.871 0.0359 27.8835 ;
		RECT 0.0831 27.9588 0.098 27.9714 ;
		RECT 0.0215 28.0216 0.0364 28.0341 ;
		RECT 0.0831 28.1094 0.098 28.122 ;
		RECT 0.021 28.3227 0.0359 28.3353 ;
		RECT 0.0215 0.1376 0.0364 0.1502 ;
		RECT 0.0215 48.9604 0.0364 48.9729 ;
		 LAYER V2 SPACING 0 ;
		RECT 0.0481 1.0918 0.1097 1.2424 ;
		RECT 0.0481 1.2424 0.1097 1.3678 ;
		RECT 0.0481 2.3718 0.1097 2.5224 ;
		RECT 0.0481 2.5224 0.1097 2.6478 ;
		RECT 0.0481 3.6518 0.1097 3.8024 ;
		RECT 0.0481 3.8024 0.1097 3.9278 ;
		RECT 0.0481 4.9318 0.1097 5.0824 ;
		RECT 0.0481 5.0824 0.1097 5.2078 ;
		RECT 0.0481 6.2118 0.1097 6.3624 ;
		RECT 0.0481 6.3624 0.1097 6.4878 ;
		RECT 0.0481 7.4918 0.1097 7.6424 ;
		RECT 0.0481 7.6424 0.1097 7.7678 ;
		RECT 0.0481 8.7718 0.1097 8.9224 ;
		RECT 0.0481 8.9224 0.1097 9.0478 ;
		RECT 0.0481 10.0518 0.1097 10.2024 ;
		RECT 0.0481 10.2024 0.1097 10.3278 ;
		RECT 0.0481 11.3318 0.1097 11.4824 ;
		RECT 0.0481 11.4824 0.1097 11.6078 ;
		RECT 0.0481 12.6118 0.1097 12.7624 ;
		RECT 0.0481 12.7624 0.1097 12.8878 ;
		RECT 0.0481 13.8918 0.1097 14.0424 ;
		RECT 0.0481 14.0424 0.1097 14.1678 ;
		RECT 0.0481 15.1718 0.1097 15.3224 ;
		RECT 0.0481 15.3224 0.1097 15.4478 ;
		RECT 0.0481 16.4518 0.1097 16.6024 ;
		RECT 0.0481 16.6024 0.1097 16.7278 ;
		RECT 0.0481 17.7318 0.1097 17.8824 ;
		RECT 0.0481 17.8824 0.1097 18.0078 ;
		RECT 0.0481 19.0118 0.1097 19.1624 ;
		RECT 0.0481 19.1624 0.1097 19.2878 ;
		RECT 0.0481 20.2918 0.1097 20.4424 ;
		RECT 0.0481 20.4424 0.1097 20.5678 ;
		RECT 0.0481 28.5678 0.1097 28.7184 ;
		RECT 0.0481 28.7184 0.1097 28.8439 ;
		RECT 0.0481 29.8478 0.1097 29.9984 ;
		RECT 0.0481 29.9984 0.1097 30.1239 ;
		RECT 0.0481 31.1278 0.1097 31.2784 ;
		RECT 0.0481 31.2784 0.1097 31.4039 ;
		RECT 0.0481 32.4078 0.1097 32.5584 ;
		RECT 0.0481 32.5584 0.1097 32.6839 ;
		RECT 0.0481 33.6878 0.1097 33.8384 ;
		RECT 0.0481 33.8384 0.1097 33.9639 ;
		RECT 0.0481 34.9678 0.1097 35.1184 ;
		RECT 0.0481 35.1184 0.1097 35.2439 ;
		RECT 0.0481 36.2478 0.1097 36.3984 ;
		RECT 0.0481 36.3984 0.1097 36.5239 ;
		RECT 0.0481 37.5278 0.1097 37.6784 ;
		RECT 0.0481 37.6784 0.1097 37.8039 ;
		RECT 0.0481 38.8078 0.1097 38.9584 ;
		RECT 0.0481 38.9584 0.1097 39.0839 ;
		RECT 0.0481 40.0878 0.1097 40.2384 ;
		RECT 0.0481 40.2384 0.1097 40.3639 ;
		RECT 0.0481 41.3678 0.1097 41.5184 ;
		RECT 0.0481 41.5184 0.1097 41.6439 ;
		RECT 0.0481 42.6478 0.1097 42.7984 ;
		RECT 0.0481 42.7984 0.1097 42.9239 ;
		RECT 0.0481 43.9278 0.1097 44.0784 ;
		RECT 0.0481 44.0784 0.1097 44.2039 ;
		RECT 0.0481 45.2078 0.1097 45.3584 ;
		RECT 0.0481 45.3584 0.1097 45.4839 ;
		RECT 0.0481 46.4878 0.1097 46.6384 ;
		RECT 0.0481 46.6384 0.1097 46.7639 ;
		RECT 0.0481 47.7678 0.1097 47.9184 ;
		RECT 0.0481 47.9184 0.1097 48.0439 ;
		RECT 0.0831 20.7306 0.098 20.7431 ;
		RECT 0.0215 20.7933 0.0364 20.8059 ;
		RECT 0.0831 20.8812 0.098 20.8937 ;
		RECT 0.0215 20.9439 0.0364 20.9565 ;
		RECT 0.0215 21.0945 0.0364 21.1071 ;
		RECT 0.0215 21.2451 0.0364 21.2576 ;
		RECT 0.021 21.3337 0.0359 21.3463 ;
		RECT 0.0831 21.4835 0.098 21.4961 ;
		RECT 0.0215 21.5463 0.0364 21.5588 ;
		RECT 0.0831 21.6341 0.098 21.6467 ;
		RECT 0.0215 21.8475 0.0364 21.86 ;
		RECT 0.0831 22.0859 0.098 22.0984 ;
		RECT 0.0215 22.1486 0.0364 22.1612 ;
		RECT 0.0831 22.2365 0.098 22.249 ;
		RECT 0.021 22.3878 0.0359 22.4004 ;
		RECT 0.0831 22.8388 0.098 22.8514 ;
		RECT 0.0215 22.9016 0.0364 22.9141 ;
		RECT 0.0831 22.9894 0.098 23.002 ;
		RECT 0.0215 23.5039 0.0364 23.5165 ;
		RECT 0.0831 23.6239 0.098 23.6365 ;
		RECT 0.0831 23.7424 0.098 23.7549 ;
		RECT 0.0831 23.8929 0.098 23.9055 ;
		RECT 0.0831 24.6459 0.098 24.6584 ;
		RECT 0.0215 24.8592 0.0364 24.8718 ;
		RECT 0.0831 24.9792 0.098 24.9918 ;
		RECT 0.0831 25.0976 0.098 25.1102 ;
		RECT 0.0831 25.3988 0.098 25.4114 ;
		RECT 0.0831 25.5816 0.098 25.5941 ;
		RECT 0.0215 25.7627 0.0364 25.7753 ;
		RECT 0.0831 25.8827 0.098 25.8953 ;
		RECT 0.0831 26.0325 0.098 26.0451 ;
		RECT 0.0215 26.1525 0.0364 26.1651 ;
		RECT 0.0831 26.2153 0.098 26.2278 ;
		RECT 0.0831 26.6357 0.098 26.6482 ;
		RECT 0.0831 27.0553 0.098 27.0678 ;
		RECT 0.0215 27.118 0.0364 27.1306 ;
		RECT 0.021 27.2067 0.0359 27.2192 ;
		RECT 0.0215 27.4192 0.0364 27.4318 ;
		RECT 0.0215 27.5698 0.0364 27.5824 ;
		RECT 0.0831 27.6576 0.098 27.6702 ;
		RECT 0.0215 27.7204 0.0364 27.7329 ;
		RECT 0.021 27.871 0.0359 27.8835 ;
		RECT 0.0831 27.9588 0.098 27.9714 ;
		RECT 0.0215 28.0216 0.0364 28.0341 ;
		RECT 0.0831 28.1094 0.098 28.122 ;
		RECT 0.021 28.3227 0.0359 28.3353 ;
		RECT 0.0215 0.1376 0.0364 0.1502 ;
		RECT 0.0215 48.9604 0.0364 48.9729 ;
	END

END HD_1024X32M8B2

END LIBRARY

